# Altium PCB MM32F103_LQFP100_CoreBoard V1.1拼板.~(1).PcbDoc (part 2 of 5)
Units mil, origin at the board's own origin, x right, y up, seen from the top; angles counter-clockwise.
Board outline 7436.93 x 4329.96 mil, 2 copper layers (Top Layer, Bottom Layer); 260 components, 116 nets, 1796 pads, 448 vias.

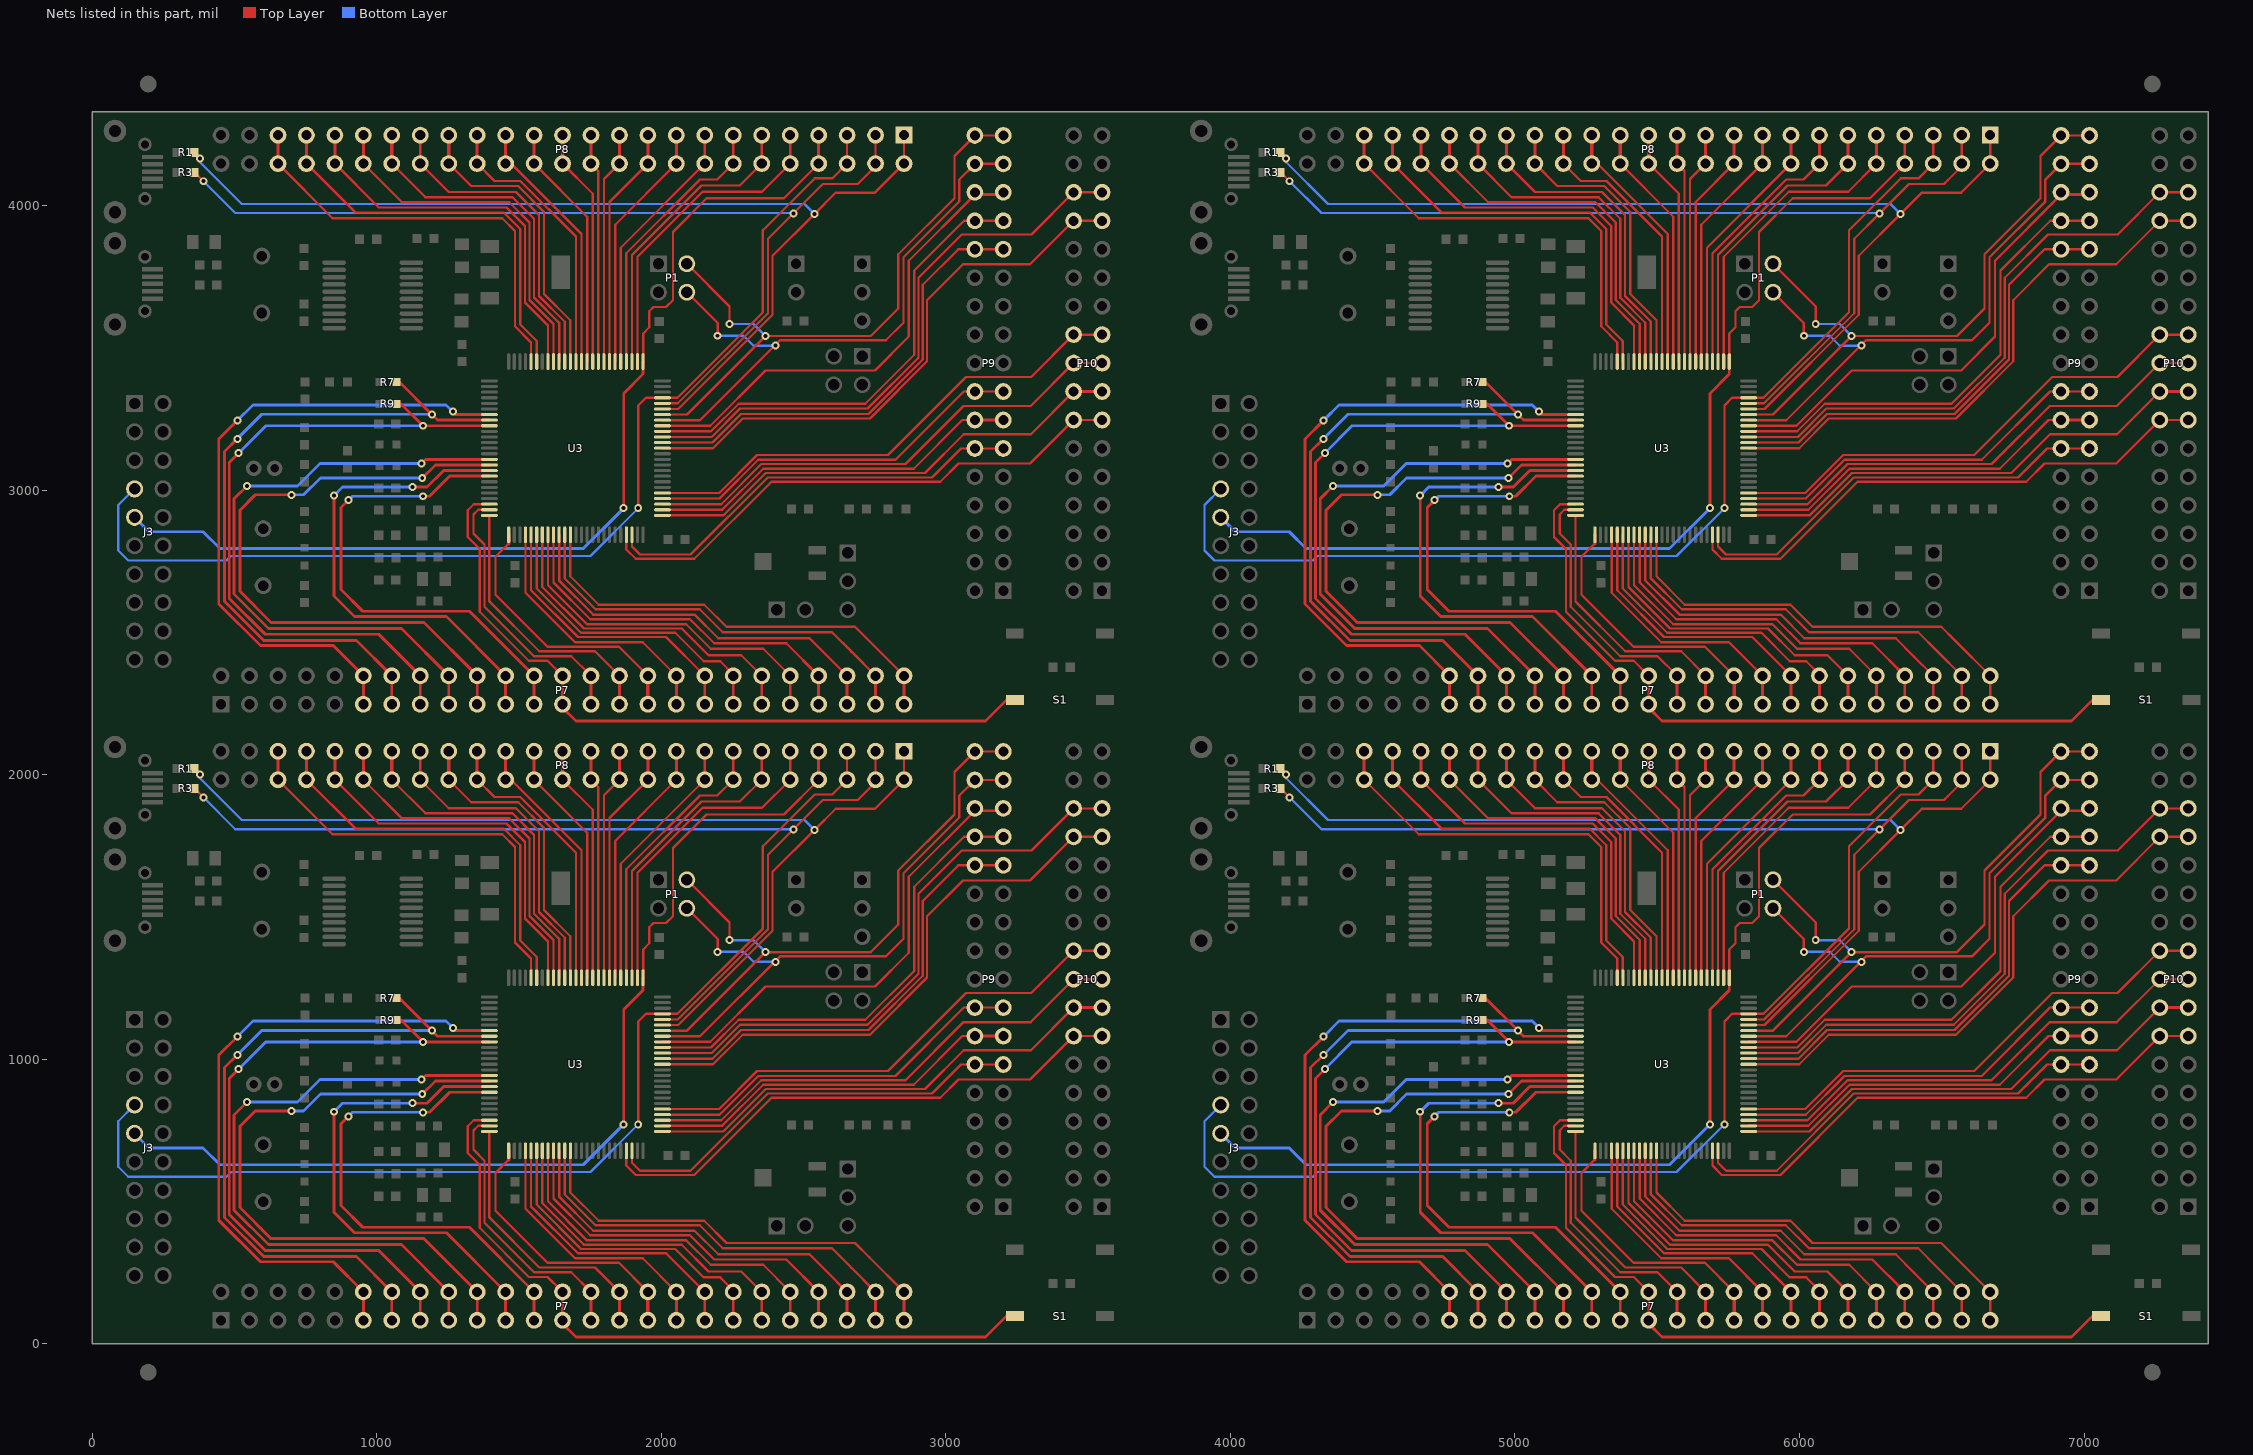
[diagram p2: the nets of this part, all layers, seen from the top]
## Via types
v1: diameter 28, hole 14, Top Layer to Bottom Layer, 228 vias
v2: diameter 24, hole 12, Top Layer to Bottom Layer, 220 vias

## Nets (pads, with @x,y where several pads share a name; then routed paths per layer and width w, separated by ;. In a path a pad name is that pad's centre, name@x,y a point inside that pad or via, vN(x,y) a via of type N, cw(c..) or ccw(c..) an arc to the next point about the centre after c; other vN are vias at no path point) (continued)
PA0: P7.25 P7.26 S1.1 U3.23 | length 10381.6
  Top Layer w8: U3.23@1395.87,786.15 1341.15,786.15 1320,765 1320,671 1362,629 1362,408 1534.5,235.5 1600.5,235.5 P7.26@1647.38,188.62 ; U3.23@1395.87,2951.15 1341.15,2951.15 1320,2930 1320,2836 1362,2794 1362,2573 1534.5,2400.5 1600.5,2400.5 P7.26@1647.38,2353.62 ; U3.23@5212.79,786.15 5158.08,786.15 5136.93,765 5136.93,671 5178.93,629 5178.93,408 5351.43,235.5 5417.43,235.5 P7.26@5464.31,188.62 ; U3.23@5212.79,2951.15 5158.08,2951.15 5136.93,2930 5136.93,2836 5178.93,2794 5178.93,2573 5351.43,2400.5 5417.43,2400.5 P7.26@5464.31,2353.62
  Top Layer w10: P7.26@1647.38,188.62 P7.26@1653,183 P7.25@1653,83 1653,71 1700,24 3139,24 3213.17,98.17 S1.1@3243,98.17 ; P7.26@1647.38,2353.62 P7.26@1653,2348 P7.25@1653,2248 1653,2236 1700,2189 3139,2189 3213.17,2263.17 S1.1@3243,2263.17 ; P7.26@5464.31,188.62 P7.26@5469.93,183 P7.25@5469.93,83 5469.93,71 5516.93,24 6955.93,24 7030.09,98.17 S1.1@7059.93,98.17 ; P7.26@5464.31,2353.62 P7.26@5469.93,2348 P7.25@5469.93,2248 5469.93,2236 5516.93,2189 6955.93,2189 7030.09,2263.17 S1.1@7059.93,2263.17
PA1: P7.27 P7.28 U3.24 | length 3910
  Top Layer w8: U3.24@1395.87,766.47 1356.47,766.47 1340,750 1340,683 1379,644 1379,426 1553,252 1684,252 P7.28@1753,183 ; U3.24@1395.87,2931.47 1356.47,2931.47 1340,2915 1340,2848 1379,2809 1379,2591 1553,2417 1684,2417 P7.28@1753,2348 ; U3.24@5212.79,766.47 5173.39,766.47 5156.93,750 5156.93,683 5195.93,644 5195.93,426 5369.93,252 5500.93,252 P7.28@5569.93,183 ; U3.24@5212.79,2931.47 5173.39,2931.47 5156.93,2915 5156.93,2848 5195.93,2809 5195.93,2591 5369.93,2417 5500.93,2417 P7.28@5569.93,2348
  Top Layer w10: P7.27@1753,83 P7.28@1753,183 ; P7.27@1753,2248 P7.28@1753,2348 ; P7.27@5569.93,83 P7.28@5569.93,183 ; P7.27@5569.93,2248 P7.28@5569.93,2348
PA2: P7.29 P7.30 U3.25 | length 3871.8
  Top Layer w8: U3.25@1395.87,746.78 1395.87,444.13 1571,269 1767,269 P7.30@1853,183 ; U3.25@1395.87,2911.78 1395.87,2609.13 1571,2434 1767,2434 P7.30@1853,2348 ; U3.25@5212.79,746.78 5212.79,444.13 5387.93,269 5583.93,269 P7.30@5669.93,183 ; U3.25@5212.79,2911.78 5212.79,2609.13 5387.93,2434 5583.93,2434 P7.30@5669.93,2348
  Top Layer w10: P7.29@1853,83 P7.30@1853,183 ; P7.29@1853,2248 P7.30@1853,2348 ; P7.29@5669.93,83 P7.30@5669.93,183 ; P7.29@5669.93,2248 P7.30@5669.93,2348
PA3: P7.31 P7.32 U3.26 | length 3996.2
  Top Layer w8: 1463.78,421.22 1474.21,410.79 ; 1463.78,647.78 1417,601 1417,468 1474.21,410.79 ; 1463.78,2586.22 1474.21,2575.79 ; 1463.78,2812.78 1417,2766 1417,2633 1474.21,2575.79 ; P7.32@1953,183 1851,285 1600,285 1474.21,410.79 ; P7.32@1953,2348 1851,2450 1600,2450 1474.21,2575.79 ; 5280.71,421.22 5291.14,410.79 ; 5280.71,647.78 5233.93,601 5233.93,468 5291.14,410.79 ; 5280.71,2586.22 5291.14,2575.79 ; 5280.71,2812.78 5233.93,2766 5233.93,2633 5291.14,2575.79 ; P7.32@5769.93,183 5667.93,285 5416.93,285 5291.14,410.79 ; P7.32@5769.93,2348 5667.93,2450 5416.93,2450 5291.14,2575.79
  Top Layer w12: 1463.78,647.78 U3.26@1463.78,678.87 ; 1463.78,2812.78 U3.26@1463.78,2843.87 ; P7.31@1953,83 P7.32@1953,183 ; P7.31@1953,2248 P7.32@1953,2348 ; 5280.71,647.78 U3.26@5280.71,678.87 ; 5280.71,2812.78 U3.26@5280.71,2843.87 ; P7.31@5769.93,83 P7.32@5769.93,183 ; P7.31@5769.93,2248 P7.32@5769.93,2348
PA4: P7.33 P7.34 U3.29 | length 3819.5
  Top Layer w8: U3.29@1522.83,678.87 1522.83,475.17 1697,301 1935,301 P7.34@2053,183 ; U3.29@1522.83,2843.87 1522.83,2640.17 1697,2466 1935,2466 P7.34@2053,2348 ; U3.29@5339.76,678.87 5339.76,475.17 5513.93,301 5751.93,301 P7.34@5869.93,183 ; U3.29@5339.76,2843.87 5339.76,2640.17 5513.93,2466 5751.93,2466 P7.34@5869.93,2348
  Top Layer w10: P7.33@2053,83 P7.34@2053,183 ; P7.33@2053,2248 P7.34@2053,2348 ; P7.33@5869.93,83 P7.34@5869.93,183 ; P7.33@5869.93,2248 P7.34@5869.93,2348
PA5: P7.35 P7.36 U3.30 | length 4121.3
  Top Layer w8: U3.30@1542.52,678.87 1542.52,483.48 1707,319 1894,319 2017,319 P7.36@2153,183 ; U3.30@1542.52,2843.87 1542.52,2648.48 1707,2484 1894,2484 2017,2484 P7.36@2153,2348 ; U3.30@5359.45,678.87 5359.45,483.48 5523.93,319 5710.93,319 5833.93,319 P7.36@5969.93,183 ; U3.30@5359.45,2843.87 5359.45,2648.48 5523.93,2484 5710.93,2484 5833.93,2484 P7.36@5969.93,2348
  Top Layer w10: P7.35@2153,83 P7.36@2153,183 ; P7.35@2153,2248 P7.36@2153,2348 ; P7.35@5969.93,83 P7.36@5969.93,183 ; P7.35@5969.93,2248 P7.36@5969.93,2348
PA6: P7.37 P7.38 U3.31 | length 4439.5
  Top Layer w8: U3.31@1562.2,678.86 1562.2,489.79 1717.99,334 2049,334 2149,234 2207,234 P7.38@2253,188 ; U3.31@1562.2,2843.86 1562.2,2654.79 1717.99,2499 2049,2499 2149,2399 2207,2399 P7.38@2253,2353 ; U3.31@5379.13,678.86 5379.13,489.79 5534.92,334 5865.93,334 5965.93,234 6023.93,234 P7.38@6069.93,188 ; U3.31@5379.13,2843.86 5379.13,2654.79 5534.92,2499 5865.93,2499 5965.93,2399 6023.93,2399 P7.38@6069.93,2353
  Top Layer w10: P7.37@2253,83 2253,176 P7.38@2253,183 P7.38@2253,188 ; P7.37@2253,2248 2253,2341 P7.38@2253,2348 P7.38@2253,2353 ; P7.37@6069.93,83 6069.93,176 P7.38@6069.93,183 P7.38@6069.93,188 ; P7.37@6069.93,2248 6069.93,2341 P7.38@6069.93,2348 P7.38@6069.93,2353
PA7: P7.39 P7.40 U3.32 | length 4736.6
  Top Layer w8: U3.32@1581.89,678.87 1581.89,495.11 1728,349 2072,349 2166,255 2281,255 P7.40@2353,183 ; U3.32@1581.89,2843.87 1581.89,2660.11 1728,2514 2072,2514 2166,2420 2281,2420 P7.40@2353,2348 ; U3.32@5398.82,678.87 5398.82,495.11 5544.93,349 5888.93,349 5982.93,255 6097.93,255 P7.40@6169.93,183 ; U3.32@5398.82,2843.87 5398.82,2660.11 5544.93,2514 5888.93,2514 5982.93,2420 6097.93,2420 P7.40@6169.93,2348
  Top Layer w10: P7.39@2353,83 P7.40@2353,183 ; P7.39@2353,2248 P7.40@2353,2348 ; P7.39@6169.93,83 P7.40@6169.93,183 ; P7.39@6169.93,2248 P7.40@6169.93,2348
PA8: P9.29 P9.30 U3.67 | length 6776.1
  Top Layer w8: U3.67@2004.13,1061.74 2172.11,1061.74 2366.37,1256 2751,1256 2870,1375 2870,1642 P9.30@3102,1874 ; U3.67@2004.13,3226.74 2172.11,3226.74 2366.37,3421 2751,3421 2870,3540 2870,3807 P9.30@3102,4039 ; U3.67@5821.06,1061.74 5989.04,1061.74 6183.3,1256 6567.93,1256 6686.93,1375 6686.93,1642 P9.30@6918.93,1874 ; U3.67@5821.06,3226.74 5989.04,3226.74 6183.3,3421 6567.93,3421 6686.93,3540 6686.93,3807 P9.30@6918.93,4039
  Top Layer w10: P9.30@3102,1874 3194,1874 P9.29@3202,1882 ; P9.30@3102,4039 3194,4039 P9.29@3202,4047 ; P9.30@6918.93,1874 7010.93,1874 P9.29@7018.93,1882 ; P9.30@6918.93,4039 7010.93,4039 P9.29@7018.93,4047
PA9: P1.4 P9.31 P9.32 U3.68 | length 8663.9
  Top Layer w8: U3.68@2004.13,1081.43 2136.43,1081.43 2417,1362 2789,1362 2851,1424 2851,1654 3047,1850 3047,1927 P9.32@3102,1982 P9.31@3202,1982 ; U3.68@2004.13,3246.43 2136.43,3246.43 2417,3527 2789,3527 2851,3589 2851,3819 3047,4015 3047,4092 P9.32@3102,4147 P9.31@3202,4147 ; P1.4@2090,1531 2198,1423 v1(2198,1378) ; P1.4@2090,3696 2198,3588 v1(2198,3543) ; U3.68@5821.06,1081.43 5953.35,1081.43 6233.93,1362 6605.93,1362 6667.93,1424 6667.93,1654 6863.93,1850 6863.93,1927 P9.32@6918.93,1982 P9.31@7018.93,1982 ; U3.68@5821.06,3246.43 5953.35,3246.43 6233.93,3527 6605.93,3527 6667.93,3589 6667.93,3819 6863.93,4015 6863.93,4092 P9.32@6918.93,4147 P9.31@7018.93,4147 ; P1.4@5906.93,1531 6014.93,1423 v1(6014.93,1378) ; P1.4@5906.93,3696 6014.93,3588 v1(6014.93,3543)
  Bottom Layer w8: v1(2198,1378) 2289,1378 2324,1343 v1(2401,1343) ; v1(2198,3543) 2289,3543 2324,3508 v1(2401,3508) ; v1(6014.93,1378) 6105.93,1378 6140.93,1343 v1(6217.93,1343) ; v1(6014.93,3543) 6105.93,3543 6140.93,3508 v1(6217.93,3508)
PA10: P1.2 P9.33 P9.34 U3.69 | length 8881.1
  Top Layer w8: U3.69@2004.13,1101.11 2090.11,1101.11 v1(2366,1377) 2736,1377 2833,1474 2833,1664 3030,1861 3030,2010 P9.34@3102,2082 P9.33@3202,2082 ; U3.69@2004.13,3266.11 2090.11,3266.11 v1(2366,3542) 2736,3542 2833,3639 2833,3829 3030,4026 3030,4175 P9.34@3102,4247 P9.33@3202,4247 ; P1.2@2090,1631 2240,1481 v1(2240,1419) ; P1.2@2090,3796 2240,3646 v1(2240,3584) ; U3.69@5821.06,1101.11 5907.04,1101.11 v1(6182.93,1377) 6552.93,1377 6649.93,1474 6649.93,1664 6846.93,1861 6846.93,2010 P9.34@6918.93,2082 P9.33@7018.93,2082 ; U3.69@5821.06,3266.11 5907.04,3266.11 v1(6182.93,3542) 6552.93,3542 6649.93,3639 6649.93,3829 6846.93,4026 6846.93,4175 P9.34@6918.93,4247 P9.33@7018.93,4247 ; P1.2@5906.93,1631 6056.93,1481 v1(6056.93,1419) ; P1.2@5906.93,3796 6056.93,3646 v1(6056.93,3584)
  Bottom Layer w8: v1(2240,1419) 2324,1419 v1(2366,1377) ; v1(2240,3584) 2324,3584 v1(2366,3542) ; v1(6056.93,1419) 6140.93,1419 v1(6182.93,1377) ; v1(6056.93,3584) 6140.93,3584 v1(6182.93,3542)
PA11: P8.1 P8.2 R1.2 U3.70 | length 14765.4
  Top Layer w8: R1.2@358,2022 v1(379,2001) ; R1.2@358,4187 v1(379,4166) ; U3.70@2004.13,1120.79 2059.79,1120.79 2391,1452 2391,1659 v1(2538,1806) 2613,1881 2648,1881 2751,1881 P8.2@2853,1983 P8.1@2853,2083 ; U3.70@2004.13,3285.79 2059.79,3285.79 2391,3617 2391,3824 v1(2538,3971) 2613,4046 2648,4046 2751,4046 P8.2@2853,4148 P8.1@2853,4248 ; R1.2@4174.93,2022 v1(4195.93,2001) ; R1.2@4174.93,4187 v1(4195.93,4166) ; U3.70@5821.06,1120.79 5876.72,1120.79 6207.93,1452 6207.93,1659 v1(6354.93,1806) 6429.93,1881 6464.93,1881 6567.93,1881 P8.2@6669.93,1983 P8.1@6669.93,2083 ; U3.70@5821.06,3285.79 5876.72,3285.79 6207.93,3617 6207.93,3824 v1(6354.93,3971) 6429.93,4046 6464.93,4046 6567.93,4046 P8.2@6669.93,4148 P8.1@6669.93,4248
  Bottom Layer w8: v1@379,1988 526,1841 2503,1841 v1(2538,1806) ; v1@379,4153 526,4006 2503,4006 v1(2538,3971) ; v1@4195.93,1988 4342.93,1841 6319.93,1841 v1(6354.93,1806) ; v1@4195.93,4153 4342.93,4006 6319.93,4006 v1(6354.93,3971)
PA12: P8.3 P8.4 R3.2 U3.71 | length 14090.1
  Top Layer w8: R3.2@358,1954 v1(391,1921) ; R3.2@358,4119 v1(391,4086) ; U3.71@2004.13,1140.48 2058.27,1140.48 2375,1457.21 2375,1719 v1(2464,1808) 2567.5,1911.5 2690.5,1911.5 2703.56,1924.56 2753,1974 P8.4@2753,1983 P8.3@2753,2083 ; U3.71@2004.13,3305.48 2058.27,3305.48 2375,3622.21 2375,3884 v1(2464,3973) 2567.5,4076.5 2690.5,4076.5 2703.56,4089.56 2753,4139 P8.4@2753,4148 P8.3@2753,4248 ; R3.2@4174.93,1954 v1(4207.93,1921) ; R3.2@4174.93,4119 v1(4207.93,4086) ; U3.71@5821.06,1140.48 5875.2,1140.48 6191.93,1457.21 6191.93,1719 v1(6280.93,1808) 6384.43,1911.5 6507.43,1911.5 6520.49,1924.56 6569.93,1974 P8.4@6569.93,1983 P8.3@6569.93,2083 ; U3.71@5821.06,3305.48 5875.2,3305.48 6191.93,3622.21 6191.93,3884 v1(6280.93,3973) 6384.43,4076.5 6507.43,4076.5 6520.49,4089.56 6569.93,4139 P8.4@6569.93,4148 P8.3@6569.93,4248
  Bottom Layer w8: v1(391,1921) 503,1809 v1@2464,1809 ; v1(391,4086) 503,3974 v1@2464,3974 ; v1(4207.93,1921) 4319.93,1809 v1@6280.93,1809 ; v1(4207.93,4086) 4319.93,3974 v1@6280.93,3974
PA13: J3.7 P8.5 P8.6 U3.72 | length 15497.8
  Top Layer w8: v1(1919,772) 1919,1133 1946.17,1160.17 U3.72@2004.13,1160.17 2056.74,1160.17 2357,1460.43 2357,1668 2357,1749 2539.07,1931.07 2601.07,1931.07 P8.6@2653,1983 P8.5@2653,2083 ; v1(1919,2937) 1919,3298 1946.17,3325.17 U3.72@2004.13,3325.17 2056.74,3325.17 2357,3625.43 2357,3833 2357,3914 2539.07,4096.07 2601.07,4096.07 P8.6@2653,4148 P8.5@2653,4248 ; v1(5735.93,772) 5735.93,1133 5763.09,1160.17 U3.72@5821.06,1160.17 5873.67,1160.17 6173.93,1460.43 6173.93,1668 6173.93,1749 6356,1931.07 6418,1931.07 P8.6@6469.93,1983 P8.5@6469.93,2083 ; v1(5735.93,2937) 5735.93,3298 5763.09,3325.17 U3.72@5821.06,3325.17 5873.67,3325.17 6173.93,3625.43 6173.93,3833 6173.93,3914 6356,4096.07 6418,4096.07 P8.6@6469.93,4148 P8.5@6469.93,4248
  Bottom Layer w8: J3.7@149,840 92,783 92,623 127,588 472,588 488,604 1751,604 v1(1919,772) ; J3.7@149,3005 92,2948 92,2788 127,2753 472,2753 488,2769 1751,2769 v1(1919,2937) ; J3.7@3965.93,840 3908.93,783 3908.93,623 3943.93,588 4288.93,588 4304.93,604 5567.93,604 v1(5735.93,772) ; J3.7@3965.93,3005 3908.93,2948 3908.93,2788 3943.93,2753 4288.93,2753 4304.93,2769 5567.93,2769 v1(5735.93,2937)
PA14: J3.9 P8.7 P8.8 U3.76 | length 14417.3
  Top Layer w8: U3.76@1936.22,1287.13 1936.22,1386.22 1958,1408 1958,1464 1973,1479 2017,1479 2041,1503 2041,1743 2159,1861 2431,1861 P8.8@2553,1983 ; U3.76@1936.22,3452.13 1936.22,3551.22 1958,3573 1958,3629 1973,3644 2017,3644 2041,3668 2041,3908 2159,4026 2431,4026 P8.8@2553,4148 ; U3.76@5753.15,1287.13 5753.15,1386.22 5774.93,1408 5774.93,1464 5789.93,1479 5833.93,1479 5857.93,1503 5857.93,1743 5975.93,1861 6247.93,1861 P8.8@6369.93,1983 ; U3.76@5753.15,3452.13 5753.15,3551.22 5774.93,3573 5774.93,3629 5789.93,3644 5833.93,3644 5857.93,3668 5857.93,3908 5975.93,4026 6247.93,4026 P8.8@6369.93,4148
  Top Layer w10: v1(1868,772) 1868,1175 1936.22,1243.22 U3.76@1936.22,1287.13 U3.76@1937,1286.35 ; v1(1868,2937) 1868,3340 1936.22,3408.22 U3.76@1936.22,3452.13 U3.76@1937,3451.35 ; P8.8@2553,1983 P8.7@2553,2083 ; P8.8@2553,4148 P8.7@2553,4248 ; v1(5684.93,772) 5684.93,1175 5753.15,1243.22 U3.76@5753.15,1287.13 U3.76@5753.93,1286.35 ; v1(5684.93,2937) 5684.93,3340 5753.15,3408.22 U3.76@5753.15,3452.13 U3.76@5753.93,3451.35 ; P8.8@6369.93,1983 P8.7@6369.93,2083 ; P8.8@6369.93,4148 P8.7@6369.93,4248
  Bottom Layer w10: J3.9@149,740 200,689 390,689 449,630 1726,630 v1(1868,772) ; J3.9@149,2905 200,2854 390,2854 449,2795 1726,2795 v1(1868,2937) ; J3.9@3965.93,740 4016.93,689 4206.93,689 4265.93,630 5542.93,630 v1(5684.93,772) ; J3.9@3965.93,2905 4016.93,2854 4206.93,2854 4265.93,2795 5542.93,2795 v1(5684.93,2937)
PA15: P8.9 P8.10 U3.77 | length 4562
  Top Layer w8: U3.77@1916.53,1287.13 1916.53,1395.53 1916.53,1655.53 2145,1884 2354,1884 P8.10@2453,1983 ; U3.77@1916.53,3452.13 1916.53,3560.53 1916.53,3820.53 2145,4049 2354,4049 P8.10@2453,4148 ; U3.77@5733.46,1287.13 5733.46,1395.53 5733.46,1655.53 5961.93,1884 6170.93,1884 P8.10@6269.93,1983 ; U3.77@5733.46,3452.13 5733.46,3560.53 5733.46,3820.53 5961.93,4049 6170.93,4049 P8.10@6269.93,4148
  Top Layer w10: P8.10@2453,1983 P8.9@2453,2083 ; P8.10@2453,4148 P8.9@2453,4248 ; P8.10@6269.93,1983 P8.9@6269.93,2083 ; P8.10@6269.93,4148 P8.9@6269.93,4248
PB0: P7.45 P7.46 U3.35 | length 5701.7
  Top Layer w8: U3.35@1640.94,678.87 1640.94,518.06 1761,398 2117,398 2200,315 2521,315 2585.74,250.26 ; U3.35@1640.94,2843.87 1640.94,2683.06 1761,2563 2117,2563 2200,2480 2521,2480 2585.74,2415.26 ; 2576,260 2585.74,250.26 ; 2576,2425 2585.74,2415.26 ; P7.46@2653,183 2585.74,250.26 ; P7.46@2653,2348 2585.74,2415.26 ; U3.35@5457.87,678.87 5457.87,518.06 5577.93,398 5933.93,398 6016.93,315 6337.93,315 6402.67,250.26 ; U3.35@5457.87,2843.87 5457.87,2683.06 5577.93,2563 5933.93,2563 6016.93,2480 6337.93,2480 6402.67,2415.26 ; 6392.93,260 6402.67,250.26 ; 6392.93,2425 6402.67,2415.26 ; P7.46@6469.93,183 6402.67,250.26 ; P7.46@6469.93,2348 6402.67,2415.26
  Top Layer w10: P7.45@2653,83 P7.46@2653,183 ; P7.45@2653,2248 P7.46@2653,2348 ; P7.45@6469.93,83 P7.46@6469.93,183 ; P7.45@6469.93,2248 P7.46@6469.93,2348
PB1: P7.47 P7.48 U3.36 | length 6029.9
  Top Layer w8: U3.36@1660.63,678.87 1660.63,525.37 1769,417 1995,417 2135,417 2216,336 2600,336 2668,268 ; U3.36@1660.63,2843.87 1660.63,2690.37 1769,2582 1995,2582 2135,2582 2216,2501 2600,2501 2668,2433 ; 2654,282 2668,268 ; 2654,2447 2668,2433 ; P7.48@2753,183 2668,268 ; P7.48@2753,2348 2668,2433 ; U3.36@5477.56,678.87 5477.56,525.37 5585.93,417 5811.93,417 5951.93,417 6032.93,336 6416.93,336 6484.93,268 ; U3.36@5477.56,2843.87 5477.56,2690.37 5585.93,2582 5811.93,2582 5951.93,2582 6032.93,2501 6416.93,2501 6484.93,2433 ; 6470.93,282 6484.93,268 ; 6470.93,2447 6484.93,2433 ; P7.48@6569.93,183 6484.93,268 ; P7.48@6569.93,2348 6484.93,2433
  Top Layer w10: P7.47@2753,83 P7.48@2753,183 ; P7.47@2753,2248 P7.48@2753,2348 ; P7.47@6569.93,83 P7.48@6569.93,183 ; P7.47@6569.93,2248 P7.48@6569.93,2348
PB2: P7.49 P7.50 U3.37 | length 6254.8
  Top Layer w8: U3.37@1680.32,678.87 1680.32,532.68 1780,433 2151,433 2229,355 2681,355 2731,305 P7.50@2853,183 ; U3.37@1680.32,2843.87 1680.32,2697.68 1780,2598 2151,2598 2229,2520 2681,2520 2731,2470 P7.50@2853,2348 ; U3.37@5497.24,678.87 5497.24,532.68 5596.93,433 5967.93,433 6045.93,355 6497.93,355 6547.93,305 P7.50@6669.93,183 ; U3.37@5497.24,2843.87 5497.24,2697.68 5596.93,2598 5967.93,2598 6045.93,2520 6497.93,2520 6547.93,2470 P7.50@6669.93,2348
  Top Layer w10: P7.49@2853,83 P7.50@2853,183 ; P7.49@2853,2248 P7.50@2853,2348 ; P7.49@6669.93,83 P7.50@6669.93,183 ; P7.49@6669.93,2248 P7.50@6669.93,2348
PB3: P8.33 P8.34 U3.89 | length 4278.1
  Top Layer w8: P8.34@1253,1983 1332,1904 1497,1904 1588,1813 1588,1525 1680.32,1432.68 U3.89@1680.32,1287.13 ; P8.34@1253,4148 1332,4069 1497,4069 1588,3978 1588,3690 1680.32,3597.68 U3.89@1680.32,3452.13 ; P8.34@5069.93,1983 5148.93,1904 5313.93,1904 5404.93,1813 5404.93,1525 5497.24,1432.68 U3.89@5497.24,1287.13 ; P8.34@5069.93,4148 5148.93,4069 5313.93,4069 5404.93,3978 5404.93,3690 5497.24,3597.68 U3.89@5497.24,3452.13
  Top Layer w11: P8.34@1253,1983 P8.33@1253,2083 ; P8.34@1253,4148 P8.33@1253,4248 ; P8.34@5069.93,1983 P8.33@5069.93,2083 ; P8.34@5069.93,4148 P8.33@5069.93,4248
PB4: P8.35 P8.36 U3.90 | length 4577.5
  Top Layer w8: P8.36@1153,1983 1253,1883 1489,1883 1570,1802 1570,1518 1660.63,1427.37 U3.90@1660.63,1287.13 ; P8.36@1153,4148 1253,4048 1489,4048 1570,3967 1570,3683 1660.63,3592.37 U3.90@1660.63,3452.13 ; P8.36@4969.93,1983 5069.93,1883 5305.93,1883 5386.93,1802 5386.93,1518 5477.56,1427.37 U3.90@5477.56,1287.13 ; P8.36@4969.93,4148 5069.93,4048 5305.93,4048 5386.93,3967 5386.93,3683 5477.56,3592.37 U3.90@5477.56,3452.13
  Top Layer w10: P8.36@1153,1983 P8.35@1153,2083 ; P8.36@1153,4148 P8.35@1153,4248 ; P8.36@4969.93,1983 P8.35@4969.93,2083 ; P8.36@4969.93,4148 P8.35@4969.93,4248
PB5: P8.37 P8.38 U3.91 | length 4874.6
  Top Layer w8: P8.38@1053,1983 1171,1865 1477,1865 1553,1789 1553,1512 1640.94,1424.06 U3.91@1640.94,1287.13 ; P8.38@1053,4148 1171,4030 1477,4030 1553,3954 1553,3677 1640.94,3589.06 U3.91@1640.94,3452.13 ; P8.38@4869.93,1983 4987.93,1865 5293.93,1865 5369.93,1789 5369.93,1512 5457.87,1424.06 U3.91@5457.87,1287.13 ; P8.38@4869.93,4148 4987.93,4030 5293.93,4030 5369.93,3954 5369.93,3677 5457.87,3589.06 U3.91@5457.87,3452.13
  Top Layer w11: P8.38@1053,1983 P8.37@1053,2083 ; P8.38@1053,4148 P8.37@1053,4248 ; P8.38@4869.93,1983 P8.37@4869.93,2083 ; P8.38@4869.93,4148 P8.37@4869.93,4248
PB6: P8.39 P8.40 U3.92 | length 5174
  Top Layer w8: P8.40@953,1983 1089,1847 1466,1847 1537,1776 1537,1504 1621.26,1419.74 U3.92@1621.26,1287.13 ; P8.40@953,4148 1089,4012 1466,4012 1537,3941 1537,3669 1621.26,3584.74 U3.92@1621.26,3452.13 ; P8.40@4769.93,1983 4905.93,1847 5282.93,1847 5353.93,1776 5353.93,1504 5438.19,1419.74 U3.92@5438.19,1287.13 ; P8.40@4769.93,4148 4905.93,4012 5282.93,4012 5353.93,3941 5353.93,3669 5438.19,3584.74 U3.92@5438.19,3452.13
  Top Layer w11: P8.40@953,1983 P8.39@953,2083 ; P8.40@953,4148 P8.39@953,4248 ; P8.40@4769.93,1983 P8.39@4769.93,2083 ; P8.40@4769.93,4148 P8.39@4769.93,4248
PB7: P8.41 P8.42 U3.93 | length 5475.8
  Top Layer w8: P8.42@853,1983 1007,1829 1456,1829 1521,1764 1521,1495 1601.58,1414.42 U3.93@1601.58,1287.13 ; P8.42@853,4148 1007,3994 1456,3994 1521,3929 1521,3660 1601.58,3579.42 U3.93@1601.58,3452.13 ; P8.42@4669.93,1983 4823.93,1829 5272.93,1829 5337.93,1764 5337.93,1495 5418.5,1414.42 U3.93@5418.5,1287.13 ; P8.42@4669.93,4148 4823.93,3994 5272.93,3994 5337.93,3929 5337.93,3660 5418.5,3579.42 U3.93@5418.5,3452.13
  Top Layer w11: P8.42@853,1983 P8.41@853,2083 ; P8.42@853,4148 P8.41@853,4248 ; P8.42@4669.93,1983 P8.41@4669.93,2083 ; P8.42@4669.93,4148 P8.41@4669.93,4248
PB8: P8.43 P8.44 U3.95 | length 5744.9
  Top Layer w8: P8.44@753,1983 925,1811 1445.95,1811 1504,1752.95 1504,1417.95 1562.2,1359.75 U3.95@1562.2,1287.14 ; P8.44@753,4148 925,3976 1445.95,3976 1504,3917.95 1504,3582.95 1562.2,3524.75 U3.95@1562.2,3452.14 ; P8.44@4569.93,1983 4741.93,1811 5262.88,1811 5320.93,1752.95 5320.93,1417.95 5379.13,1359.75 U3.95@5379.13,1287.14 ; P8.44@4569.93,4148 4741.93,3976 5262.88,3976 5320.93,3917.95 5320.93,3582.95 5379.13,3524.75 U3.95@5379.13,3452.14
  Top Layer w11: P8.44@753,1983 P8.43@753,2083 ; P8.44@753,4148 P8.43@753,4248 ; P8.44@4569.93,1983 P8.43@4569.93,2083 ; P8.44@4569.93,4148 P8.43@4569.93,4248
PB9: P8.45 P8.46 U3.96 | length 6054.3
  Top Layer w8: P8.46@653,1983 845,1791 1441.2,1791 1486,1746.2 1486,1411.2 1542.52,1354.68 U3.96@1542.52,1287.13 ; P8.46@653,4148 845,3956 1441.2,3956 1486,3911.2 1486,3576.2 1542.52,3519.68 U3.96@1542.52,3452.13 ; P8.46@4469.93,1983 4661.93,1791 5258.13,1791 5302.93,1746.2 5302.93,1411.2 5359.45,1354.68 U3.96@5359.45,1287.13 ; P8.46@4469.93,4148 4661.93,3956 5258.13,3956 5302.93,3911.2 5302.93,3576.2 5359.45,3519.68 U3.96@5359.45,3452.13
  Top Layer w10: P8.46@653,1983 P8.45@653,2083 ; P8.46@653,4148 P8.45@653,4248 ; P8.46@4469.93,1983 P8.45@4469.93,2083 ; P8.46@4469.93,4148 P8.45@4469.93,4248
PB10: P10.13 P10.14 U3.47 | length 7758.4
  Top Layer w8: U3.47@1877.17,678.87 1877.17,626.83 1910,594 2097.79,594 2116,594 2387,865 2980,865 3044,929 3296,929 P10.14@3449,1082 P10.13@3549,1082 ; U3.47@1877.17,2843.87 1877.17,2791.83 1910,2759 2097.79,2759 2116,2759 2387,3030 2980,3030 3044,3094 3296,3094 P10.14@3449,3247 P10.13@3549,3247 ; U3.47@5694.09,678.87 5694.09,626.83 5726.93,594 5914.72,594 5932.93,594 6203.93,865 6796.93,865 6860.93,929 7112.93,929 P10.14@7265.93,1082 P10.13@7365.93,1082 ; U3.47@5694.09,2843.87 5694.09,2791.83 5726.93,2759 5914.72,2759 5932.93,2759 6203.93,3030 6796.93,3030 6860.93,3094 7112.93,3094 P10.14@7265.93,3247 P10.13@7365.93,3247
PB11: P9.11 P9.12 U3.48 | length 6052.1
  Top Layer w8: U3.48@1896.85,678.87 1896.85,637.15 1925,609 2091,609 2103,609 2374,880 2951,880 3053,982 P9.12@3102,982 P9.11@3202,982 ; U3.48@1896.85,2843.87 1896.85,2802.15 1925,2774 2091,2774 2103,2774 2374,3045 2951,3045 3053,3147 P9.12@3102,3147 P9.11@3202,3147 ; U3.48@5713.78,678.87 5713.78,637.15 5741.93,609 5907.93,609 5919.93,609 6190.93,880 6767.93,880 6869.93,982 P9.12@6918.93,982 P9.11@7018.93,982 ; U3.48@5713.78,2843.87 5713.78,2802.15 5741.93,2774 5907.93,2774 5919.93,2774 6190.93,3045 6767.93,3045 6869.93,3147 P9.12@6918.93,3147 P9.11@7018.93,3147
PB12: P10.15 P10.16 U3.51 | length 6900.6
  Top Layer w8: U3.51@2004.13,746.78 2218.15,746.78 2367.37,896 2927,896 3063,1032 3299,1032 P10.16@3449,1182 ; U3.51@2004.13,2911.78 2218.15,2911.78 2367.37,3061 2927,3061 3063,3197 3299,3197 P10.16@3449,3347 ; U3.51@5821.06,746.78 6035.08,746.78 6184.3,896 6743.93,896 6879.93,1032 7115.93,1032 P10.16@7265.93,1182 ; U3.51@5821.06,2911.78 6035.08,2911.78 6184.3,3061 6743.93,3061 6879.93,3197 7115.93,3197 P10.16@7265.93,3347
  Top Layer w10: P10.16@3449,1182 P10.15@3549,1182 ; P10.16@3449,3347 P10.15@3549,3347 ; P10.16@7265.93,1182 P10.15@7365.93,1182 ; P10.16@7265.93,3347 P10.15@7365.93,3347
PB13: P9.13 P9.14 U3.52 | length 5314.3
  Top Layer w8: U3.52@2004.13,766.47 2213.8,766.47 2358.33,911 2887,911 3058,1082 P9.14@3102,1082 ; U3.52@2004.13,2931.47 2213.8,2931.47 2358.33,3076 2887,3076 3058,3247 P9.14@3102,3247 ; U3.52@5821.06,766.47 6030.73,766.47 6175.26,911 6703.93,911 6874.93,1082 P9.14@6918.93,1082 ; U3.52@5821.06,2931.47 6030.73,2931.47 6175.26,3076 6703.93,3076 6874.93,3247 P9.14@6918.93,3247
  Top Layer w10: P9.14@3102,1082 P9.13@3202,1082 ; P9.14@3102,3247 P9.13@3202,3247 ; P9.14@6918.93,1082 P9.13@7018.93,1082 ; P9.14@6918.93,3247 P9.13@7018.93,3247
PB14: P10.17 P10.18 U3.53 | length 7001
  Top Layer w8: U3.53@2004.13,786.15 2210.85,786.15 2351.7,927 2858,927 3062,1131 3298,1131 P10.18@3449,1282 P10.17@3549,1282 ; U3.53@2004.13,2951.15 2210.85,2951.15 2351.7,3092 2858,3092 3062,3296 3298,3296 P10.18@3449,3447 P10.17@3549,3447 ; U3.53@5821.06,786.15 6027.78,786.15 6168.63,927 6674.93,927 6878.93,1131 7114.93,1131 P10.18@7265.93,1282 P10.17@7365.93,1282 ; U3.53@5821.06,2951.15 6027.78,2951.15 6168.63,3092 6674.93,3092 6878.93,3296 7114.93,3296 P10.18@7265.93,3447 P10.17@7365.93,3447
PB15: P9.15 P9.16 U3.54 | length 5414.7
  Top Layer w8: U3.54@2004.13,805.83 2204.83,805.83 2341,942 2823,942 3063,1182 P9.16@3102,1182 P9.15@3202,1182 ; U3.54@2004.13,2970.83 2204.83,2970.83 2341,3107 2823,3107 3063,3347 P9.16@3102,3347 P9.15@3202,3347 ; U3.54@5821.06,805.83 6021.76,805.83 6157.93,942 6639.93,942 6879.93,1182 P9.16@6918.93,1182 P9.15@7018.93,1182 ; U3.54@5821.06,2970.83 6021.76,2970.83 6157.93,3107 6639.93,3107 6879.93,3347 P9.16@6918.93,3347 P9.15@7018.93,3347
PC0: P7.17 P7.18 U3.15 | length 9048.7
  Top Layer w10: v1(544,850) 499,805 499,470 620,349 1087,349 P7.18@1253,183 P7.17@1253,83 ; v1(544,3015) 499,2970 499,2635 620,2514 1087,2514 P7.18@1253,2348 P7.17@1253,2248 ; v1(1157,929) 1171.63,943.63 U3.15@1395.87,943.63 ; v1(1157,3094) 1171.63,3108.63 U3.15@1395.87,3108.63 ; v1(4360.93,850) 4315.93,805 4315.93,470 4436.93,349 4903.93,349 P7.18@5069.93,183 P7.17@5069.93,83 ; v1(4360.93,3015) 4315.93,2970 4315.93,2635 4436.93,2514 4903.93,2514 P7.18@5069.93,2348 P7.17@5069.93,2248 ; v1(4973.93,929) 4988.56,943.63 U3.15@5212.79,943.63 ; v1(4973.93,3094) 4988.56,3108.63 U3.15@5212.79,3108.63
  Bottom Layer w10: v1(544,850) 722,850 801,929 v1(1157,929) ; v1(544,3015) 722,3015 801,3094 v1(1157,3094) ; v1(4360.93,850) 4538.93,850 4617.93,929 v1(4973.93,929) ; v1(4360.93,3015) 4538.93,3015 4617.93,3094 v1(4973.93,3094)
PC1: P7.19 P7.20 U3.16 | length 9138.9
  Top Layer w10: v1(700,819) 573,819 519,765 519,480 629,370 1166,370 P7.20@1353,183 P7.19@1353,83 ; v1(700,2984) 573,2984 519,2930 519,2645 629,2535 1166,2535 P7.20@1353,2348 P7.19@1353,2248 ; v1(1160,878) 1205.94,923.94 U3.16@1395.87,923.94 ; v1(1160,3043) 1205.94,3088.94 U3.16@1395.87,3088.94 ; v1(4516.93,819) 4389.93,819 4335.93,765 4335.93,480 4445.93,370 4982.93,370 P7.20@5169.93,183 P7.19@5169.93,83 ; v1(4516.93,2984) 4389.93,2984 4335.93,2930 4335.93,2645 4445.93,2535 4982.93,2535 P7.20@5169.93,2348 P7.19@5169.93,2248 ; v1(4976.93,878) 5022.87,923.94 U3.16@5212.79,923.94 ; v1(4976.93,3043) 5022.87,3088.94 U3.16@5212.79,3088.94
  Bottom Layer w10: v1(700,819) 743,819 802,878 v1(1160,878) ; v1(700,2984) 743,2984 802,3043 v1(1160,3043) ; v1(4516.93,819) 4559.93,819 4618.93,878 v1(4976.93,878) ; v1(4516.93,2984) 4559.93,2984 4618.93,3043 v1(4976.93,3043)
PC2: P7.21 P7.22 U3.17 | length 7017.6
  Top Layer w10: v1(850,816) 850,463 922,391 1245,391 P7.22@1453,183 P7.21@1453,83 ; v1(850,2981) 850,2628 922,2556 1245,2556 P7.22@1453,2348 P7.21@1453,2248 ; v1(1125,846) 1177,846 1235.26,904.26 U3.17@1395.87,904.26 ; v1(1125,3011) 1177,3011 1235.26,3069.26 U3.17@1395.87,3069.26 ; v1(4666.93,816) 4666.93,463 4738.93,391 5061.93,391 P7.22@5269.93,183 P7.21@5269.93,83 ; v1(4666.93,2981) 4666.93,2628 4738.93,2556 5061.93,2556 P7.22@5269.93,2348 P7.21@5269.93,2248 ; v1(4941.93,846) 4993.93,846 5052.19,904.26 U3.17@5212.79,904.26 ; v1(4941.93,3011) 4993.93,3011 5052.19,3069.26 U3.17@5212.79,3069.26
  Bottom Layer w10: v1(850,816) 880,846 v1(1125,846) ; v1(850,2981) 880,3011 v1(1125,3011) ; v1(4666.93,816) 4696.93,846 v1(4941.93,846) ; v1(4666.93,2981) 4696.93,3011 v1(4941.93,3011)
PC3: P7.23 P7.24 U3.18 | length 7032.7
  Top Layer w10: v1(901,800) 875,774 875,486 951,410 1326,410 P7.24@1553,183 P7.23@1553,83 ; v1(901,2965) 875,2939 875,2651 951,2575 1326,2575 P7.24@1553,2348 P7.23@1553,2248 ; v1(1163,814) 1186,814 1256.58,884.58 U3.18@1395.87,884.58 ; v1(1163,2979) 1186,2979 1256.58,3049.58 U3.18@1395.87,3049.58 ; v1(4717.93,800) 4691.93,774 4691.93,486 4767.93,410 5142.93,410 P7.24@5369.93,183 P7.23@5369.93,83 ; v1(4717.93,2965) 4691.93,2939 4691.93,2651 4767.93,2575 5142.93,2575 P7.24@5369.93,2348 P7.23@5369.93,2248 ; v1(4979.93,814) 5002.93,814 5073.5,884.58 U3.18@5212.79,884.58 ; v1(4979.93,2979) 5002.93,2979 5073.5,3049.58 U3.18@5212.79,3049.58
  Bottom Layer w10: v1(901,800) 915,814 v1(1163,814) ; v1(901,2965) 915,2979 v1(1163,2979) ; v1(4717.93,800) 4731.93,814 v1(4979.93,814) ; v1(4717.93,2965) 4731.93,2979 v1(4979.93,2979)
PC4: P7.41 P7.42 U3.33 | length 5043
  Top Layer w8: U3.33@1601.58,678.87 1601.58,501.42 1739,364 2088,364 2174,278 2358,278 P7.42@2453,183 ; U3.33@1601.58,2843.87 1601.58,2666.42 1739,2529 2088,2529 2174,2443 2358,2443 P7.42@2453,2348 ; U3.33@5418.5,678.87 5418.5,501.42 5555.93,364 5904.93,364 5990.93,278 6174.93,278 P7.42@6269.93,183 ; U3.33@5418.5,2843.87 5418.5,2666.42 5555.93,2529 5904.93,2529 5990.93,2443 6174.93,2443 P7.42@6269.93,2348
  Top Layer w10: P7.41@2453,83 P7.42@2453,183 ; P7.41@2453,2248 P7.42@2453,2348 ; P7.41@6269.93,83 P7.42@6269.93,183 ; P7.41@6269.93,2248 P7.42@6269.93,2348
PC5: P7.43 P7.44 U3.34 | length 5648
  Top Layer w8: U3.34@1621.26,678.87 1621.26,510.74 1750,382 2101,382 2186,297 2439,297 P7.44@2553,183 ; U3.34@1621.26,2843.87 1621.26,2675.74 1750,2547 2101,2547 2186,2462 2439,2462 P7.44@2553,2348 ; U3.34@5438.19,678.87 5438.19,510.74 5566.93,382 5917.93,382 6002.93,297 6255.93,297 P7.44@6369.93,183 ; U3.34@5438.19,2843.87 5438.19,2675.74 5566.93,2547 5917.93,2547 6002.93,2462 6255.93,2462 P7.44@6369.93,2348
  Top Layer w10: 2499,237 P7.44@2553,183 P7.43@2553,83 ; 2499,2402 P7.44@2553,2348 P7.43@2553,2248 ; 6315.93,237 P7.44@6369.93,183 P7.43@6369.93,83 ; 6315.93,2402 P7.44@6369.93,2348 P7.43@6369.93,2248
PC6: P10.27 P10.28 U3.63 | length 8007.1
  Top Layer w8: U3.63@2004.14,983 2182,983 2286,1087 2733,1087 2934,1288 2934,1503 3060,1629 3296,1629 P10.28@3449,1782 P10.27@3549,1782 ; U3.63@2004.14,3148 2182,3148 2286,3252 2733,3252 2934,3453 2934,3668 3060,3794 3296,3794 P10.28@3449,3947 P10.27@3549,3947 ; U3.63@5821.06,983 5998.93,983 6102.93,1087 6549.93,1087 6750.93,1288 6750.93,1503 6876.93,1629 7112.93,1629 P10.28@7265.93,1782 P10.27@7365.93,1782 ; U3.63@5821.06,3148 5998.93,3148 6102.93,3252 6549.93,3252 6750.93,3453 6750.93,3668 6876.93,3794 7112.93,3794 P10.28@7265.93,3947 P10.27@7365.93,3947
PC7: P9.25 P9.26 U3.64 | length 6532.7
  Top Layer w8: U3.64@2004.13,1002.68 2179.68,1002.68 2280,1103 2727.79,1103 2919,1294.21 2919,1557 3044,1682 P9.26@3102,1682 P9.25@3202,1682 ; U3.64@2004.13,3167.68 2179.68,3167.68 2280,3268 2727.79,3268 2919,3459.21 2919,3722 3044,3847 P9.26@3102,3847 P9.25@3202,3847 ; U3.64@5821.06,1002.68 5996.61,1002.68 6096.93,1103 6544.72,1103 6735.93,1294.21 6735.93,1557 6860.93,1682 P9.26@6918.93,1682 P9.25@7018.93,1682 ; U3.64@5821.06,3167.68 5996.61,3167.68 6096.93,3268 6544.72,3268 6735.93,3459.21 6735.93,3722 6860.93,3847 P9.26@6918.93,3847 P9.25@7018.93,3847
PC8: P10.29 P10.30 U3.65 | length 8262.2
  Top Layer w8: U3.65@2004.13,1022.37 2177.37,1022.37 2277,1122 2725,1122 2904,1301 2904,1582 3056,1734 3301,1734 P10.30@3449,1882 P10.29@3549,1882 ; U3.65@2004.13,3187.37 2177.37,3187.37 2277,3287 2725,3287 2904,3466 2904,3747 3056,3899 3301,3899 P10.30@3449,4047 P10.29@3549,4047 ; U3.65@5821.06,1022.37 5994.3,1022.37 6093.93,1122 6541.93,1122 6720.93,1301 6720.93,1582 6872.93,1734 7117.93,1734 P10.30@7265.93,1882 P10.29@7365.93,1882 ; U3.65@5821.06,3187.37 5994.3,3187.37 6093.93,3287 6541.93,3287 6720.93,3466 6720.93,3747 6872.93,3899 7117.93,3899 P10.30@7265.93,4047 P10.29@7365.93,4047
PC9: P9.27 P9.28 U3.66 | length 6711
  Top Layer w8: U3.66@2004.13,1042.06 2175.06,1042.06 2272,1139 2717,1139 2889,1311 2889,1607 3064,1782 P9.28@3102,1782 P9.27@3202,1782 ; U3.66@2004.13,3207.06 2175.06,3207.06 2272,3304 2717,3304 2889,3476 2889,3772 3064,3947 P9.28@3102,3947 P9.27@3202,3947 ; U3.66@5821.06,1042.06 5991.98,1042.06 6088.93,1139 6533.93,1139 6705.93,1311 6705.93,1607 6880.93,1782 P9.28@6918.93,1782 P9.27@7018.93,1782 ; U3.66@5821.06,3207.06 5991.98,3207.06 6088.93,3304 6533.93,3304 6705.93,3476 6705.93,3772 6880.93,3947 P9.28@6918.93,3947 P9.27@7018.93,3947
PC10: P8.11 P8.12 U3.78 | length 4255.6
  Top Layer w8: U3.78@1896.85,1287.13 1896.85,1400.85 1896.85,1661.85 2141,1906 2276,1906 P8.12@2353,1983 ; U3.78@1896.85,3452.13 1896.85,3565.85 1896.85,3826.85 2141,4071 2276,4071 P8.12@2353,4148 ; U3.78@5713.78,1287.13 5713.78,1400.85 5713.78,1661.85 5957.93,1906 6092.93,1906 P8.12@6169.93,1983 ; U3.78@5713.78,3452.13 5713.78,3565.85 5713.78,3826.85 5957.93,4071 6092.93,4071 P8.12@6169.93,4148
  Top Layer w10: P8.12@2353,1983 P8.11@2353,2083 ; P8.12@2353,4148 P8.11@2353,4248 ; P8.12@6169.93,1983 P8.11@6169.93,2083 ; P8.12@6169.93,4148 P8.11@6169.93,4248
PC11: P8.13 P8.14 U3.79 | length 3949.1
  Top Layer w8: U3.79@1877.17,1287.13 1877.17,1410.17 1877.17,1668.17 2136,1927 2197,1927 P8.14@2253,1983 ; U3.79@1877.17,3452.13 1877.17,3575.17 1877.17,3833.17 2136,4092 2197,4092 P8.14@2253,4148 ; U3.79@5694.09,1287.13 5694.09,1410.17 5694.09,1668.17 5952.93,1927 6013.93,1927 P8.14@6069.93,1983 ; U3.79@5694.09,3452.13 5694.09,3575.17 5694.09,3833.17 5952.93,4092 6013.93,4092 P8.14@6069.93,4148
  Top Layer w10: P8.14@2253,1983 P8.13@2253,2083 ; P8.14@2253,4148 P8.13@2253,4248 ; P8.14@6069.93,1983 P8.13@6069.93,2083 ; P8.14@6069.93,4148 P8.13@6069.93,4248
PC12: P8.15 P8.16 U3.80 | length 3673.1
  Top Layer w8: U3.80@1857.48,1287.13 1857.48,1419.44 1857.48,1687.48 P8.16@2153,1983 ; U3.80@1857.48,3452.13 1857.48,3584.44 1857.48,3852.48 P8.16@2153,4148 ; U3.80@5674.41,1287.13 5674.41,1419.44 5674.41,1687.48 P8.16@5969.93,1983 ; U3.80@5674.41,3452.13 5674.41,3584.44 5674.41,3852.48 P8.16@5969.93,4148
  Top Layer w10: P8.16@2153,1983 P8.15@2153,2083 ; P8.16@2153,4148 P8.15@2153,4248 ; P8.16@5969.93,1983 P8.15@5969.93,2083 ; P8.16@5969.93,4148 P8.15@5969.93,4248
PC13: P7.11 P7.12 U3.7 | length 9228
  Top Layer w10: v1(511,1081) 445,1015 445,435 591,289 847,289 P7.12@953,183 P7.11@953,83 ; v1(511,3246) 445,3180 445,2600 591,2454 847,2454 P7.12@953,2348 P7.11@953,2248 ; v1(1268,1111) 1277.89,1101.11 U3.7@1395.87,1101.11 ; v1(1268,3276) 1277.89,3266.11 U3.7@1395.87,3266.11 ; v1(4327.93,1081) 4261.93,1015 4261.93,435 4407.93,289 4663.93,289 P7.12@4769.93,183 P7.11@4769.93,83 ; v1(4327.93,3246) 4261.93,3180 4261.93,2600 4407.93,2454 4663.93,2454 P7.12@4769.93,2348 P7.11@4769.93,2248 ; v1(5084.93,1111) 5094.82,1101.11 U3.7@5212.79,1101.11 ; v1(5084.93,3276) 5094.82,3266.11 U3.7@5212.79,3266.11
  Bottom Layer w10: v1(511,1081) 565,1135 1244,1135 v1(1268,1111) ; v1(511,3246) 565,3300 1244,3300 v1(1268,3276) ; v1(4327.93,1081) 4381.93,1135 5060.93,1135 v1(5084.93,1111) ; v1(4327.93,3246) 4381.93,3300 5060.93,3300 v1(5084.93,3276)
PC14: P7.13 P7.14 R7.2 U3.8 | length 10015
  Top Layer w10: v1(510,1016) 465,971 465,445 603,307 929,307 P7.14@1053,183 P7.13@1053,83 ; v1(510,3181) 465,3136 465,2610 603,2472 929,2472 P7.14@1053,2348 P7.13@1053,2248 ; R7.2@1069,1215.14 1079.86,1215.14 v1@1193.5,1101.5 ; R7.2@1069,3380.14 1079.86,3380.14 v1@1193.5,3266.5 ; v1(1194,1102) v1@1193.5,1101.5 ; v1(1194,3267) v1@1193.5,3266.5 ; U3.8@1395.87,1081.43 1213.57,1081.43 v1@1193.5,1101.5 ; U3.8@1395.87,3246.43 1213.57,3246.43 v1@1193.5,3266.5 ; v1(4326.93,1016) 4281.93,971 4281.93,445 4419.93,307 4745.93,307 P7.14@4869.93,183 P7.13@4869.93,83 ; v1(4326.93,3181) 4281.93,3136 4281.93,2610 4419.93,2472 4745.93,2472 P7.14@4869.93,2348 P7.13@4869.93,2248 ; R7.2@4885.93,1215.14 4896.79,1215.14 v1@5010.43,1101.5 ; R7.2@4885.93,3380.14 4896.79,3380.14 v1@5010.43,3266.5 ; v1(5010.93,1102) v1@5010.43,1101.5 ; v1(5010.93,3267) v1@5010.43,3266.5 ; U3.8@5212.79,1081.43 5030.5,1081.43 v1@5010.43,1101.5 ; U3.8@5212.79,3246.43 5030.5,3246.43 v1@5010.43,3266.5
  Bottom Layer w10: v1(510,1016) 596,1102 674,1102 ; v1(510,3181) 596,3267 674,3267 ; 659,1102 674,1102 ; 659,3267 674,3267 ; v1(1194,1102) 674,1102 ; v1(1194,3267) 674,3267 ; v1(4326.93,1016) 4412.93,1102 4490.93,1102 ; v1(4326.93,3181) 4412.93,3267 4490.93,3267 ; 4475.93,1102 4490.93,1102 ; 4475.93,3267 4490.93,3267 ; v1(5010.93,1102) 4490.93,1102 ; v1(5010.93,3267) 4490.93,3267
PC15: P7.15 P7.16 R9.2 U3.9 | length 9831.3
  Top Layer w10: v1@515,962 v1(515,966) 482,933 482,455 608,329 1007,329 P7.16@1153,183 P7.15@1153,83 ; v1@515,3127 v1(515,3131) 482,3098 482,2620 608,2494 1007,2494 P7.16@1153,2348 P7.15@1153,2248 ; R9.2@1069,1138.29 1085.71,1138.29 v1(1162.26,1061.74) U3.9@1395.87,1061.74 ; R9.2@1069,3303.29 1085.71,3303.29 v1(1162.26,3226.74) U3.9@1395.87,3226.74 ; v1@4331.93,962 v1(4331.93,966) 4298.93,933 4298.93,455 4424.93,329 4823.93,329 P7.16@4969.93,183 P7.15@4969.93,83 ; v1@4331.93,3127 v1(4331.93,3131) 4298.93,3098 4298.93,2620 4424.93,2494 4823.93,2494 P7.16@4969.93,2348 P7.15@4969.93,2248 ; R9.2@4885.93,1138.29 4902.64,1138.29 v1(4979.19,1061.74) U3.9@5212.79,1061.74 ; R9.2@4885.93,3303.29 4902.64,3303.29 v1(4979.19,3226.74) U3.9@5212.79,3226.74
  Bottom Layer w10: v1(515,966) 610.74,1061.74 v1(1162.26,1061.74) ; v1(515,3131) 610.74,3226.74 v1(1162.26,3226.74) ; v1(4331.93,966) 4427.67,1061.74 v1(4979.19,1061.74) ; v1(4331.93,3131) 4427.67,3226.74 v1(4979.19,3226.74)
PD0: P8.17 P8.18 U3.81 | length 3540
  Top Layer w8: U3.81@1837.8,1287.14 1837.8,1423.8 1837.8,1767.8 P8.18@2053,1983 ; U3.81@1837.8,3452.14 1837.8,3588.8 1837.8,3932.8 P8.18@2053,4148 ; U3.81@5654.72,1287.14 5654.72,1423.8 5654.72,1767.8 P8.18@5869.93,1983 ; U3.81@5654.72,3452.14 5654.72,3588.8 5654.72,3932.8 P8.18@5869.93,4148
  Top Layer w10: P8.18@2053,1983 P8.17@2053,2083 ; P8.18@2053,4148 P8.17@2053,4248 ; P8.18@5869.93,1983 P8.17@5869.93,2083 ; P8.18@5869.93,4148 P8.17@5869.93,4248
PD1: P8.19 P8.20 U3.82 | length 3407
  Top Layer w8: U3.82@1818.11,1287.13 1818.11,1431.11 1818.11,1848.11 P8.20@1953,1983 ; U3.82@1818.11,3452.13 1818.11,3596.11 1818.11,4013.11 P8.20@1953,4148 ; U3.82@5635.04,1287.13 5635.04,1431.11 5635.04,1848.11 P8.20@5769.93,1983 ; U3.82@5635.04,3452.13 5635.04,3596.11 5635.04,4013.11 P8.20@5769.93,4148
  Top Layer w10: P8.20@1953,1983 P8.19@1953,2083 ; P8.20@1953,4148 P8.19@1953,4248 ; P8.20@5769.93,1983 P8.19@5769.93,2083 ; P8.20@5769.93,4148 P8.19@5769.93,4248
PD2: P8.21 P8.22 U3.83 | length 3273.9
  Top Layer w8: U3.83@1798.43,1287.13 1798.43,1440.43 1798.43,1928.43 P8.22@1853,1983 ; U3.83@1798.43,3452.13 1798.43,3605.43 1798.43,4093.43 P8.22@1853,4148 ; U3.83@5615.35,1287.13 5615.35,1440.43 5615.35,1928.43 P8.22@5669.93,1983 ; U3.83@5615.35,3452.13 5615.35,3605.43 5615.35,4093.43 P8.22@5669.93,4148
  Top Layer w10: P8.22@1853,1983 P8.21@1853,2083 ; P8.22@1853,4148 P8.21@1853,4248 ; P8.22@5669.93,1983 P8.21@5669.93,2083 ; P8.22@5669.93,4148 P8.21@5669.93,4248
PD3: P8.23 P8.24 U3.84 | length 3226.1
  Top Layer w8: P8.24@1753,1983 1778.74,1957.26 1778.74,1448.74 U3.84@1778.74,1287.13 ; P8.24@1753,4148 1778.74,4122.26 1778.74,3613.74 U3.84@1778.74,3452.13 ; P8.24@5569.93,1983 5595.67,1957.26 5595.67,1448.74 U3.84@5595.67,1287.13 ; P8.24@5569.93,4148 5595.67,4122.26 5595.67,3613.74 U3.84@5595.67,3452.13
  Top Layer w11: P8.24@1753,1983 P8.23@1753,2083 ; P8.24@1753,4148 P8.23@1753,4248 ; P8.24@5569.93,1983 P8.23@5569.93,2083 ; P8.24@5569.93,4148 P8.23@5569.93,4248
PD4: P8.25 P8.26 U3.85 | length 3359.2
  Top Layer w8: P8.26@1653,1983 1759.05,1876.95 1759.05,1462.05 U3.85@1759.05,1287.14 ; P8.26@1653,4148 1759.05,4041.95 1759.05,3627.05 U3.85@1759.05,3452.14 ; P8.26@5469.93,1983 5575.98,1876.95 5575.98,1462.05 U3.85@5575.98,1287.14 ; P8.26@5469.93,4148 5575.98,4041.95 5575.98,3627.05 U3.85@5575.98,3452.14
  Top Layer w11: P8.26@1653,1983 P8.25@1653,2083 ; P8.26@1653,4148 P8.25@1653,4248 ; P8.26@5469.93,1983 P8.25@5469.93,2083 ; P8.26@5469.93,4148 P8.25@5469.93,4248
PD5: P8.27 P8.28 U3.86 | length 3492.3
  Top Layer w8: P8.28@1553,1983 1739.37,1796.63 1739.37,1476.37 U3.86@1739.37,1287.13 ; P8.28@1553,4148 1739.37,3961.63 1739.37,3641.37 U3.86@1739.37,3452.13 ; P8.28@5369.93,1983 5556.3,1796.63 5556.3,1476.37 U3.86@5556.3,1287.13 ; P8.28@5369.93,4148 5556.3,3961.63 5556.3,3641.37 U3.86@5556.3,3452.13
  Top Layer w11: P8.28@1553,1983 P8.27@1553,2083 ; P8.28@1553,4148 P8.27@1553,4248 ; P8.28@5369.93,1983 P8.27@5369.93,2083 ; P8.28@5369.93,4148 P8.27@5369.93,4248
PD6: P8.29 P8.30 U3.87 | length 3669.8
  Top Layer w8: P8.30@1472,1983 1719.68,1735.32 1719.68,1483.68 U3.87@1719.68,1287.13 ; P8.30@1472,4148 1719.68,3900.32 1719.68,3648.68 U3.87@1719.68,3452.13 ; P8.30@5288.93,1983 5536.61,1735.32 5536.61,1483.68 U3.87@5536.61,1287.13 ; P8.30@5288.93,4148 5536.61,3900.32 5536.61,3648.68 U3.87@5536.61,3452.13
  Top Layer w11: P8.29@1453,2083 P8.30@1453,1983 P8.30@1472,1983 ; P8.29@1453,4248 P8.30@1453,4148 P8.30@1472,4148 ; P8.29@5269.93,2083 P8.30@5269.93,1983 P8.30@5288.93,1983 ; P8.29@5269.93,4248 P8.30@5269.93,4148 P8.30@5288.93,4148
PD7: P8.31 P8.32 U3.88 | length 3970.3
  Top Layer w8: P8.32@1353,1983 1414,1922 1504.46,1922 1700,1726.46 1700,1491 U3.88@1700,1287.14 ; P8.32@1353,4148 1414,4087 1504.46,4087 1700,3891.46 1700,3656 U3.88@1700,3452.14 ; P8.32@5169.93,1983 5230.93,1922 5321.38,1922 5516.93,1726.46 5516.93,1491 U3.88@5516.93,1287.14 ; P8.32@5169.93,4148 5230.93,4087 5321.38,4087 5516.93,3891.46 5516.93,3656 U3.88@5516.93,3452.14
  Top Layer w11: P8.32@1353,1983 P8.31@1353,2083 ; P8.32@1353,4148 P8.31@1353,4248 ; P8.32@5169.93,1983 P8.31@5169.93,2083 ; P8.32@5169.93,4148 P8.31@5169.93,4248
PD8: P10.19 P10.20 U3.55 | length 7101.5
  Top Layer w8: U3.55@2004.13,825.52 2203.31,825.52 2336.79,959 2797,959 3071,1233 3300,1233 P10.20@3449,1382 P10.19@3549,1382 ; U3.55@2004.13,2990.52 2203.31,2990.52 2336.79,3124 2797,3124 3071,3398 3300,3398 P10.20@3449,3547 P10.19@3549,3547 ; U3.55@5821.06,825.52 6020.24,825.52 6153.72,959 6613.93,959 6887.93,1233 7116.93,1233 P10.20@7265.93,1382 P10.19@7365.93,1382 ; U3.55@5821.06,2990.52 6020.24,2990.52 6153.72,3124 6613.93,3124 6887.93,3398 7116.93,3398 P10.20@7265.93,3547 P10.19@7365.93,3547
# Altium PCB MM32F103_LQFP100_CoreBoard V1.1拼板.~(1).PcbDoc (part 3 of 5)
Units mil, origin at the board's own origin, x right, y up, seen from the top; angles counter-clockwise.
Board outline 7436.93 x 4329.96 mil, 2 copper layers (Top Layer, Bottom Layer); 260 components, 116 nets, 1796 pads, 448 vias.

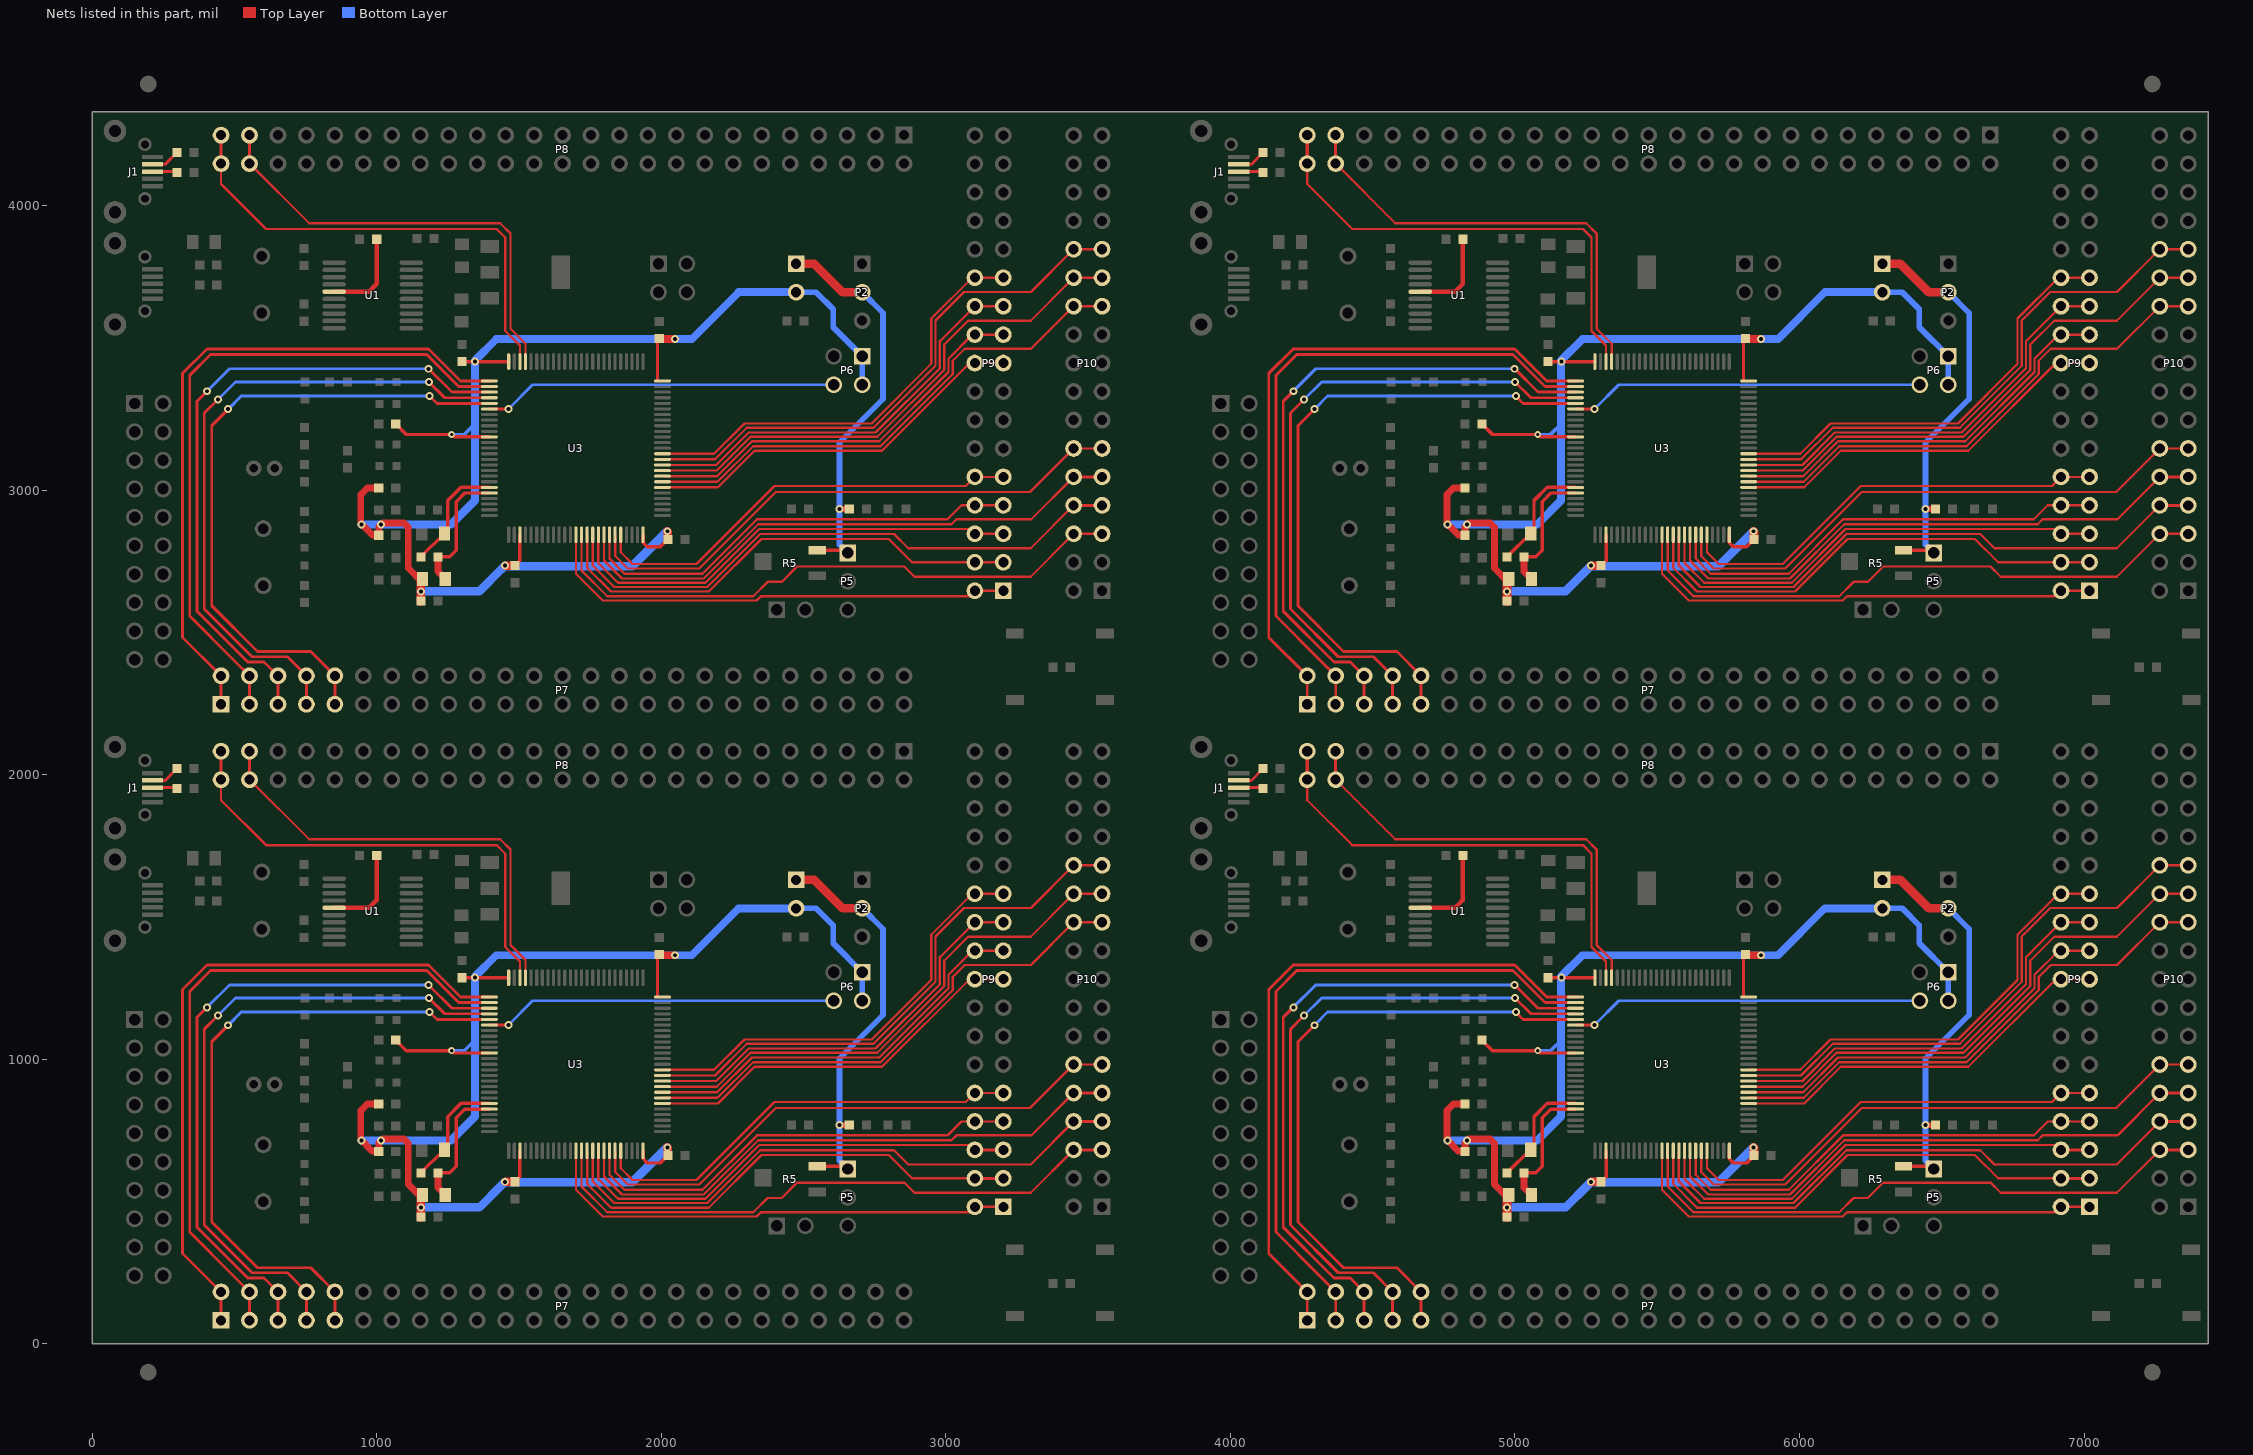
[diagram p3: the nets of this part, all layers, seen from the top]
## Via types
v1: diameter 28, hole 14, Top Layer to Bottom Layer, 228 vias
v2: diameter 24, hole 12, Top Layer to Bottom Layer, 220 vias

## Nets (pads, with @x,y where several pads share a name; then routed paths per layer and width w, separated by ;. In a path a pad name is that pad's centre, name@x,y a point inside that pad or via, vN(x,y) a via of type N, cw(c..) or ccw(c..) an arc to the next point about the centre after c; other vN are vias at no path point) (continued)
PD9: P9.17 P9.18 U3.56 | length 5515.2
  Top Layer w8: U3.56@2004.14,845.2 2199.2,845.2 2328,974 2776,974 3084,1282 P9.18@3102,1282 P9.17@3202,1282 ; U3.56@2004.14,3010.2 2199.2,3010.2 2328,3139 2776,3139 3084,3447 P9.18@3102,3447 P9.17@3202,3447 ; U3.56@5821.06,845.2 6016.13,845.2 6144.93,974 6592.93,974 6900.93,1282 P9.18@6918.93,1282 P9.17@7018.93,1282 ; U3.56@5821.06,3010.2 6016.13,3010.2 6144.93,3139 6592.93,3139 6900.93,3447 P9.18@6918.93,3447 P9.17@7018.93,3447
PD10: P10.21 P10.22 U3.57 | length 7309.7
  Top Layer w8: U3.57@2004.13,864.89 2197.68,864.89 2322.79,990 2770,990 3024,1244 3024,1290 3066,1332 3299,1332 P10.22@3449,1482 P10.21@3549,1482 ; U3.57@2004.13,3029.89 2197.68,3029.89 2322.79,3155 2770,3155 3024,3409 3024,3455 3066,3497 3299,3497 P10.22@3449,3647 P10.21@3549,3647 ; U3.57@5821.06,864.89 6014.61,864.89 6139.72,990 6586.93,990 6840.93,1244 6840.93,1290 6882.93,1332 7115.93,1332 P10.22@7265.93,1482 P10.21@7365.93,1482 ; U3.57@5821.06,3029.89 6014.61,3029.89 6139.72,3155 6586.93,3155 6840.93,3409 6840.93,3455 6882.93,3497 7115.93,3497 P10.22@7265.93,3647 P10.21@7365.93,3647
PD11: P9.19 P9.20 U3.58 | length 5725.8
  Top Layer w8: U3.58@2004.13,884.58 2196.15,884.58 2318.57,1007 2765.79,1007 3009,1250.21 3009,1297.21 3093.79,1382 P9.20@3102,1382 P9.19@3202,1382 ; U3.58@2004.13,3049.58 2196.15,3049.58 2318.57,3172 2765.79,3172 3009,3415.21 3009,3462.21 3093.79,3547 P9.20@3102,3547 P9.19@3202,3547 ; U3.58@5821.06,884.58 6013.08,884.58 6135.5,1007 6582.72,1007 6825.93,1250.21 6825.93,1297.21 6910.72,1382 P9.20@6918.93,1382 P9.19@7018.93,1382 ; U3.58@5821.06,3049.58 6013.08,3049.58 6135.5,3172 6582.72,3172 6825.93,3415.21 6825.93,3462.21 6910.72,3547 P9.20@6918.93,3547 P9.19@7018.93,3547
PD12: P10.23 P10.24 U3.59 | length 7510.9
  Top Layer w8: U3.59@2004.13,904.26 2194.62,904.26 2313.36,1023 2759,1023 2994,1258 2994,1347 3078,1431 3298,1431 P10.24@3449,1582 P10.23@3549,1582 ; U3.59@2004.13,3069.26 2194.62,3069.26 2313.36,3188 2759,3188 2994,3423 2994,3512 3078,3596 3298,3596 P10.24@3449,3747 P10.23@3549,3747 ; U3.59@5821.06,904.26 6011.55,904.26 6130.29,1023 6575.93,1023 6810.93,1258 6810.93,1347 6894.93,1431 7114.93,1431 P10.24@7265.93,1582 P10.23@7365.93,1582 ; U3.59@5821.06,3069.26 6011.55,3069.26 6130.29,3188 6575.93,3188 6810.93,3423 6810.93,3512 6894.93,3596 7114.93,3596 P10.24@7265.93,3747 P10.23@7365.93,3747
PD13: P9.21 P9.22 U3.60 | length 5938.2
  Top Layer w8: U3.60@2004.13,923.94 2193.09,923.94 2307.15,1038 2752.79,1038 2979,1264.21 2979,1359 P9.22@3102,1482 P9.21@3202,1482 ; U3.60@2004.13,3088.94 2193.09,3088.94 2307.15,3203 2752.79,3203 2979,3429.21 2979,3524 P9.22@3102,3647 P9.21@3202,3647 ; U3.60@5821.06,923.94 6010.02,923.94 6124.08,1038 6569.72,1038 6795.93,1264.21 6795.93,1359 P9.22@6918.93,1482 P9.21@7018.93,1482 ; U3.60@5821.06,3088.94 6010.02,3088.94 6124.08,3203 6569.72,3203 6795.93,3429.21 6795.93,3524 P9.22@6918.93,3647 P9.21@7018.93,3647
PD14: P10.25 P10.26 U3.61 | length 7775.4
  Top Layer w8: U3.61@2004.13,943.63 2188.63,943.63 2300,1055 2746,1055 2964,1273 2964,1432 3064,1532 3299,1532 P10.26@3449,1682 P10.25@3549,1682 ; U3.61@2004.13,3108.63 2188.63,3108.63 2300,3220 2746,3220 2964,3438 2964,3597 3064,3697 3299,3697 P10.26@3449,3847 P10.25@3549,3847 ; U3.61@5821.06,943.63 6005.56,943.63 6116.93,1055 6562.93,1055 6780.93,1273 6780.93,1432 6880.93,1532 7115.93,1532 P10.26@7265.93,1682 P10.25@7365.93,1682 ; U3.61@5821.06,3108.63 6005.56,3108.63 6116.93,3220 6562.93,3220 6780.93,3438 6780.93,3597 6880.93,3697 7115.93,3697 P10.26@7265.93,3847 P10.25@7365.93,3847
PD15: P9.23 P9.24 U3.62 | length 6189.1
  Top Layer w8: U3.62@2004.13,963.32 2185.32,963.32 2292,1070 2739.79,1070 2949,1279.21 2949,1438.21 3092.79,1582 P9.24@3102,1582 P9.23@3202,1582 ; U3.62@2004.13,3128.32 2185.32,3128.32 2292,3235 2739.79,3235 2949,3444.21 2949,3603.21 3092.79,3747 P9.24@3102,3747 P9.23@3202,3747 ; U3.62@5821.06,963.32 6002.24,963.32 6108.93,1070 6556.72,1070 6765.93,1279.21 6765.93,1438.21 6909.72,1582 P9.24@6918.93,1582 P9.23@7018.93,1582 ; U3.62@5821.06,3128.32 6002.24,3128.32 6108.93,3235 6556.72,3235 6765.93,3444.21 6765.93,3603.21 6909.72,3747 P9.24@6918.93,3747 P9.23@7018.93,3747
PE0: P8.47 P8.48 U3.97 | length 6363.7
  Top Layer w8: P8.48@553,1983 762.5,1773.5 1433.96,1773.5 1470,1737.46 1470,1402.46 1522.83,1349.62 U3.97@1522.83,1287.13 ; P8.48@553,4148 762.5,3938.5 1433.96,3938.5 1470,3902.46 1470,3567.46 1522.83,3514.62 U3.97@1522.83,3452.13 ; P8.48@4369.93,1983 4579.43,1773.5 5250.88,1773.5 5286.93,1737.46 5286.93,1402.46 5339.76,1349.62 U3.97@5339.76,1287.13 ; P8.48@4369.93,4148 4579.43,3938.5 5250.88,3938.5 5286.93,3902.46 5286.93,3567.46 5339.76,3514.62 U3.97@5339.76,3452.13
  Top Layer w11: P8.48@553,1983 P8.47@553,2083 ; P8.48@553,4148 P8.47@553,4248 ; P8.48@4369.93,1983 P8.47@4369.93,2083 ; P8.48@4369.93,4148 P8.47@4369.93,4248
PE1: P8.49 P8.50 U3.98 | length 6823.7
  Top Layer w8: P8.50@453,1983 453,1911 611,1753 1422,1753 1452,1723 1452,1395 1503.15,1343.85 U3.98@1503.15,1287.13 ; P8.50@453,4148 453,4076 611,3918 1422,3918 1452,3888 1452,3560 1503.15,3508.85 U3.98@1503.15,3452.13 ; P8.50@4269.93,1983 4269.93,1911 4427.93,1753 5238.93,1753 5268.93,1723 5268.93,1395 5320.08,1343.85 U3.98@5320.08,1287.13 ; P8.50@4269.93,4148 4269.93,4076 4427.93,3918 5238.93,3918 5268.93,3888 5268.93,3560 5320.08,3508.85 U3.98@5320.08,3452.13
  Top Layer w11: P8.50@453,1983 P8.49@453,2083 ; P8.50@453,4148 P8.49@453,4248 ; P8.50@4269.93,1983 P8.49@4269.93,2083 ; P8.50@4269.93,4148 P8.49@4269.93,4248
PE2: P7.1 P7.2 U3.1 | length 9553
  Top Layer w10: P7.1@453,83 P7.2@453,183 318,318 318,1246 404,1332 1182,1332 1294.78,1219.22 U3.1@1405,1219.22 ; P7.1@453,2248 P7.2@453,2348 318,2483 318,3411 404,3497 1182,3497 1294.78,3384.22 U3.1@1405,3384.22 ; P7.1@4269.93,83 P7.2@4269.93,183 4134.93,318 4134.93,1246 4220.93,1332 4998.93,1332 5111.71,1219.22 U3.1@5221.93,1219.22 ; P7.1@4269.93,2248 P7.2@4269.93,2348 4134.93,2483 4134.93,3411 4220.93,3497 4998.93,3497 5111.71,3384.22 U3.1@5221.93,3384.22
PE3: P7.3 P7.4 U3.2 | length 9490.7
  Top Layer w10: P7.3@553,83 P7.4@553,183 497,239 343,393 343,1239 416,1312 1176,1312 1288.47,1199.53 U3.2@1395.87,1199.53 ; P7.3@553,2248 P7.4@553,2348 497,2404 343,2558 343,3404 416,3477 1176,3477 1288.47,3364.53 U3.2@1395.87,3364.53 ; P7.3@4369.93,83 P7.4@4369.93,183 4313.93,239 4159.93,393 4159.93,1239 4232.93,1312 4992.93,1312 5105.39,1199.53 U3.2@5212.79,1199.53 ; P7.3@4369.93,2248 P7.4@4369.93,2348 4313.93,2404 4159.93,2558 4159.93,3404 4232.93,3477 4992.93,3477 5105.39,3364.53 U3.2@5212.79,3364.53
PE4: P7.5 P7.6 U3.3 | length 9296.6
  Top Layer w10: v1(404,1183) 369,1148 369,410 547,232 604,232 P7.6@653,183 P7.5@653,83 ; v1(404,3348) 369,3313 369,2575 547,2397 604,2397 P7.6@653,2348 P7.5@653,2248 ; v1(1182,1262) 1264.15,1179.85 U3.3@1395.87,1179.85 ; v1(1182,3427) 1264.15,3344.85 U3.3@1395.87,3344.85 ; v1(4220.93,1183) 4185.93,1148 4185.93,410 4363.93,232 4420.93,232 P7.6@4469.93,183 P7.5@4469.93,83 ; v1(4220.93,3348) 4185.93,3313 4185.93,2575 4363.93,2397 4420.93,2397 P7.6@4469.93,2348 P7.5@4469.93,2248 ; v1(4998.93,1262) 5081.08,1179.85 U3.3@5212.79,1179.85 ; v1(4998.93,3427) 5081.08,3344.85 U3.3@5212.79,3344.85
  Bottom Layer w10: v1(404,1183) 483,1262 v1(1182,1262) ; v1(404,3348) 483,3427 v1(1182,3427) ; v1(4220.93,1183) 4299.93,1262 v1(4998.93,1262) ; v1(4220.93,3348) 4299.93,3427 v1(4998.93,3427)
PE5: P7.7 P7.8 U3.4 | length 9259.6
  Top Layer w10: v1(442,1154) 394,1106 394,418 562,250 686,250 P7.8@753,183 P7.7@753,83 ; v1(442,3319) 394,3271 394,2583 562,2415 686,2415 P7.8@753,2348 P7.7@753,2248 ; v1(1183,1216) 1238.83,1160.17 U3.4@1395.87,1160.17 ; v1(1183,3381) 1238.83,3325.17 U3.4@1395.87,3325.17 ; v1(4258.93,1154) 4210.93,1106 4210.93,418 4378.93,250 4502.93,250 P7.8@4569.93,183 P7.7@4569.93,83 ; v1(4258.93,3319) 4210.93,3271 4210.93,2583 4378.93,2415 4502.93,2415 P7.8@4569.93,2348 P7.7@4569.93,2248 ; v1(4999.93,1216) 5055.76,1160.17 U3.4@5212.79,1160.17 ; v1(4999.93,3381) 5055.76,3325.17 U3.4@5212.79,3325.17
  Bottom Layer w10: v1(442,1154) 504,1216 v1(1183,1216) ; v1(442,3319) 504,3381 v1(1183,3381) ; v1(4258.93,1154) 4320.93,1216 v1(4999.93,1216) ; v1(4258.93,3319) 4320.93,3381 v1(4999.93,3381)
PE6: P7.9 P7.10 U3.5 | length 9189.6
  Top Layer w10: v1(478,1120) 420,1062 420,429 581,268 768,268 P7.10@853,183 P7.9@853,83 ; v1(478,3285) 420,3227 420,2594 581,2433 768,2433 P7.10@853,2348 P7.9@853,2248 ; v1(1186,1166) 1211.52,1140.48 U3.5@1395.87,1140.48 ; v1(1186,3331) 1211.52,3305.48 U3.5@1395.87,3305.48 ; v1(4294.93,1120) 4236.93,1062 4236.93,429 4397.93,268 4584.93,268 P7.10@4669.93,183 P7.9@4669.93,83 ; v1(4294.93,3285) 4236.93,3227 4236.93,2594 4397.93,2433 4584.93,2433 P7.10@4669.93,2348 P7.9@4669.93,2248 ; v1(5002.93,1166) 5028.45,1140.48 U3.5@5212.79,1140.48 ; v1(5002.93,3331) 5028.45,3305.48 U3.5@5212.79,3305.48
  Bottom Layer w10: v1(478,1120) 524,1166 v1(1186,1166) ; v1(478,3285) 524,3331 v1(1186,3331) ; v1(4294.93,1120) 4340.93,1166 v1(5002.93,1166) ; v1(4294.93,3285) 4340.93,3331 v1(5002.93,3331)
PE7: P9.1 P9.2 U3.38 | length 6767.5
  Top Layer w8: U3.38@1700,678.86 1700,542 1794,448 2335,448 2350,463 P9.2@3083,463 ; U3.38@1700,2843.86 1700,2707 1794,2613 2335,2613 2350,2628 P9.2@3083,2628 ; U3.38@5516.93,678.86 5516.93,542 5610.93,448 6151.93,448 6166.93,463 P9.2@6899.93,463 ; U3.38@5516.93,2843.86 5516.93,2707 5610.93,2613 6151.93,2613 6166.93,2628 P9.2@6899.93,2628
  Top Layer w10: P9.2@3083,463 P9.2@3102,482 P9.1@3202,482 ; P9.2@3083,2628 P9.2@3102,2647 P9.1@3202,2647 ; P9.2@6899.93,463 P9.2@6918.93,482 P9.1@7018.93,482 ; P9.2@6899.93,2628 P9.2@6918.93,2647 P9.1@7018.93,2647
PE8: P10.5 P10.6 U3.39 | length 8451.2
  Top Layer w8: U3.39@1719.68,678.87 1719.68,553.32 1810,463 2323,463 2373.08,513.08 2423.08,513.08 2477,567 2854,567 2890,531 3298,531 P10.6@3449,682 ; U3.39@1719.68,2843.87 1719.68,2718.32 1810,2628 2323,2628 2373.08,2678.08 2423.08,2678.08 2477,2732 2854,2732 2890,2696 3298,2696 P10.6@3449,2847 ; U3.39@5536.61,678.87 5536.61,553.32 5626.93,463 6139.93,463 6190,513.08 6240,513.08 6293.93,567 6670.93,567 6706.93,531 7114.93,531 P10.6@7265.93,682 ; U3.39@5536.61,2843.87 5536.61,2718.32 5626.93,2628 6139.93,2628 6190,2678.08 6240,2678.08 6293.93,2732 6670.93,2732 6706.93,2696 7114.93,2696 P10.6@7265.93,2847
  Top Layer w10: P10.6@3449,682 P10.5@3549,682 ; P10.6@3449,2847 P10.5@3549,2847 ; P10.6@7265.93,682 P10.5@7365.93,682 ; P10.6@7265.93,2847 P10.5@7365.93,2847
PE9: P9.3 P9.4 U3.40 | length 6896.4
  Top Layer w8: U3.40@1739.37,678.87 1739.37,562.63 1823,479 2167,479 2352,664 2799,664 2881,582 P9.4@3102,582 ; U3.40@1739.37,2843.87 1739.37,2727.63 1823,2644 2167,2644 2352,2829 2799,2829 2881,2747 P9.4@3102,2747 ; U3.40@5556.3,678.87 5556.3,562.63 5639.93,479 5983.93,479 6168.93,664 6615.93,664 6697.93,582 P9.4@6918.93,582 ; U3.40@5556.3,2843.87 5556.3,2727.63 5639.93,2644 5983.93,2644 6168.93,2829 6615.93,2829 6697.93,2747 P9.4@6918.93,2747
  Top Layer w10: P9.4@3102,582 P9.3@3202,582 ; P9.4@3102,2747 P9.3@3202,2747 ; P9.4@6918.93,582 P9.3@7018.93,582 ; P9.4@6918.93,2747 P9.3@7018.93,2747
PE10: P10.7 P10.8 U3.41 | length 8358.5
  Top Layer w8: U3.41@1759.05,678.86 1759.05,570.95 1835,495 2161.79,495 2347.79,681 2818,681 2868,631 3298,631 P10.8@3449,782 ; U3.41@1759.05,2843.86 1759.05,2735.95 1835,2660 2161.79,2660 2347.79,2846 2818,2846 2868,2796 3298,2796 P10.8@3449,2947 ; U3.41@5575.98,678.86 5575.98,570.95 5651.93,495 5978.72,495 6164.72,681 6634.93,681 6684.93,631 7114.93,631 P10.8@7265.93,782 ; U3.41@5575.98,2843.86 5575.98,2735.95 5651.93,2660 5978.72,2660 6164.72,2846 6634.93,2846 6684.93,2796 7114.93,2796 P10.8@7265.93,2947
  Top Layer w10: P10.8@3449,782 P10.7@3549,782 ; P10.8@3449,2947 P10.7@3549,2947 ; P10.8@7265.93,782 P10.7@7365.93,782 ; P10.8@7265.93,2947 P10.7@7365.93,2947
PE11: P9.5 P9.6 U3.42 | length 6547.5
  Top Layer w8: U3.42@1778.74,678.87 1778.74,579.26 1848,510 2155.57,510 2344.57,699 P9.6@3085,699 ; U3.42@1778.74,2843.87 1778.74,2744.26 1848,2675 2155.57,2675 2344.57,2864 P9.6@3085,2864 ; U3.42@5595.67,678.87 5595.67,579.26 5664.93,510 5972.5,510 6161.5,699 P9.6@6901.93,699 ; U3.42@5595.67,2843.87 5595.67,2744.26 5664.93,2675 5972.5,2675 6161.5,2864 P9.6@6901.93,2864
  Top Layer w10: P9.6@3085,699 P9.6@3102,682 P9.5@3202,682 ; P9.6@3085,2864 P9.6@3102,2847 P9.5@3202,2847 ; P9.6@6901.93,699 P9.6@6918.93,682 P9.5@7018.93,682 ; P9.6@6901.93,2864 P9.6@6918.93,2847 P9.5@7018.93,2847
PE12: P10.9 P10.10 U3.43 | length 8060.3
  Top Layer w8: U3.43@1798.43,678.87 1798.43,588.57 1862,525 2149.36,525 2340.36,716 3020,716 3037,733 3300,733 P10.10@3449,882 ; U3.43@1798.43,2843.87 1798.43,2753.57 1862,2690 2149.36,2690 2340.36,2881 3020,2881 3037,2898 3300,2898 P10.10@3449,3047 ; U3.43@5615.35,678.87 5615.35,588.57 5678.93,525 5966.29,525 6157.29,716 6836.93,716 6853.93,733 7116.93,733 P10.10@7265.93,882 ; U3.43@5615.35,2843.87 5615.35,2753.57 5678.93,2690 5966.29,2690 6157.29,2881 6836.93,2881 6853.93,2898 7116.93,2898 P10.10@7265.93,3047
  Top Layer w10: P10.10@3449,882 P10.9@3549,882 ; P10.10@3449,3047 P10.9@3549,3047 ; P10.10@7265.93,882 P10.9@7365.93,882 ; P10.10@7265.93,3047 P10.9@7365.93,3047
PE13: P9.7 P9.8 U3.44 | length 6356.7
  Top Layer w8: U3.44@1818.11,678.87 1818.11,594.89 1871,542 2145.15,542 2336.15,733 3006,733 3055,782 P9.8@3102,782 P9.7@3202,782 ; U3.44@1818.11,2843.87 1818.11,2759.89 1871,2707 2145.15,2707 2336.15,2898 3006,2898 3055,2947 P9.8@3102,2947 P9.7@3202,2947 ; U3.44@5635.04,678.87 5635.04,594.89 5687.93,542 5962.08,542 6153.08,733 6822.93,733 6871.93,782 P9.8@6918.93,782 P9.7@7018.93,782 ; U3.44@5635.04,2843.87 5635.04,2759.89 5687.93,2707 5962.08,2707 6153.08,2898 6822.93,2898 6871.93,2947 P9.8@6918.93,2947 P9.7@7018.93,2947
PE14: P10.11 P10.12 U3.45 | length 7915.9
  Top Layer w8: U3.45@1837.8,678.86 1837.8,604.2 1882,560 2107,560 2133,560 2402,829 3009,829 3296,829 P10.12@3449,982 P10.11@3549,982 ; U3.45@1837.8,2843.86 1837.8,2769.2 1882,2725 2107,2725 2133,2725 2402,2994 3009,2994 3296,2994 P10.12@3449,3147 P10.11@3549,3147 ; U3.45@5654.72,678.86 5654.72,604.2 5698.93,560 5923.93,560 5949.93,560 6218.93,829 6825.93,829 7112.93,829 P10.12@7265.93,982 P10.11@7365.93,982 ; U3.45@5654.72,2843.86 5654.72,2769.2 5698.93,2725 5923.93,2725 5949.93,2725 6218.93,2994 6825.93,2994 7112.93,2994 P10.12@7265.93,3147 P10.11@7365.93,3147
PE15: P9.9 P9.10 U3.46 | length 6199.3
  Top Layer w8: U3.46@1857.48,678.87 1857.48,617.52 1899,576 2101,576 2124,576 2398,850 3070,850 P9.10@3102,882 P9.9@3202,882 ; U3.46@1857.48,2843.87 1857.48,2782.52 1899,2741 2101,2741 2124,2741 2398,3015 3070,3015 P9.10@3102,3047 P9.9@3202,3047 ; U3.46@5674.41,678.87 5674.41,617.52 5715.93,576 5917.93,576 5940.93,576 6214.93,850 6886.93,850 P9.10@6918.93,882 P9.9@7018.93,882 ; U3.46@5674.41,2843.87 5674.41,2782.52 5715.93,2741 5917.93,2741 5940.93,2741 6214.93,3015 6886.93,3015 P9.10@6918.93,3047 P9.9@7018.93,3047
USB_DN: J1.2 R1.1 | length 412.6
  Top Layer w10: J1.2@212,1980.59 256.59,1980.59 R1.1@298,2022 ; J1.2@212,4145.59 256.59,4145.59 R1.1@298,4187 ; J1.2@4028.93,1980.59 4073.52,1980.59 R1.1@4114.93,2022 ; J1.2@4028.93,4145.59 4073.52,4145.59 R1.1@4114.93,4187
USB_DP: J1.3 R3.1 | length 345.6
  Top Layer w10: J1.3@212,1955 297,1955 R3.1@298,1954 ; J1.3@212,4120 297,4120 R3.1@298,4119 ; J1.3@4028.93,1955 4113.93,1955 R3.1@4114.93,1954 ; J1.3@4028.93,4120 4113.93,4120 R3.1@4114.93,4119
VBAT: P6.4 U3.6 | length 4981.6
  Top Layer w10: U3.6@1395.86,1120.8 1396.07,1121 v1(1463,1121) ; U3.6@1395.86,3285.8 1396.07,3286 v1(1463,3286) ; U3.6@5212.79,1120.8 5213,1121 v1(5279.93,1121) ; U3.6@5212.79,3285.8 5213,3286 v1(5279.93,3286)
  Bottom Layer w10: v1(1463,1121) 1547.94,1205.94 P6.4@2606,1205.94 ; v1(1463,3286) 1547.94,3370.94 P6.4@2606,3370.94 ; v1(5279.93,1121) 5364.87,1205.94 P6.4@6422.93,1205.94 ; v1(5279.93,3286) 5364.87,3370.94 P6.4@6422.93,3370.94
VCC_MCU: C6.1 C16.2 C18.1 C19.1 C20.1 C21.1 L1.1 P4.2 P6.1 P6.2 R17.2 R19.2 U3.11 U3.28 U3.50 U3.75 U3.100 | length 21564.9
  Top Layer w11: C6.1@1299,1287 C6.1@1299.13,1287.13 ; C6.1@1299,3452 C6.1@1299.13,3452.13 ; U3.75@1986.13,1219.22 1986.13,1361.13 C18.1@1993,1368 ; U3.75@1986.13,3384.22 1986.13,3526.13 C18.1@1993,3533 ; C6.1@5115.93,1287 C6.1@5116.06,1287.13 ; C6.1@5115.93,3452 C6.1@5116.06,3452.13 ; U3.75@5803.06,1219.22 5803.06,1361.13 C18.1@5809.93,1368 ; U3.75@5803.06,3384.22 5803.06,3526.13 C18.1@5809.93,3533
  Top Layer w12: C20.1@1067,1068 1104,1031 v2(1263,1031) 1271.63,1022.37 U3.11@1395.87,1022.37 ; C20.1@1067,3233 1104,3196 v2(1263,3196) 1271.63,3187.37 U3.11@1395.87,3187.37 ; C6.1@1299.13,1287.13 v1(1346,1287.13) U3.100@1463.78,1287.13 ; C6.1@1299.13,3452.13 v1(1346,3452.13) U3.100@1463.78,3452.13 ; C19.1@1486,570 1503.15,587.15 U3.28@1503.15,678.87 ; C19.1@1486,2735 1503.15,2752.15 U3.28@1503.15,2843.87 ; U3.50@1936.22,678.87 1936.22,650.78 1951,636 1997,636 C16.2@2023,662 ; U3.50@1936.22,2843.87 1936.22,2815.78 1951,2801 1997,2801 C16.2@2023,2827 ; C20.1@4883.93,1068 4920.93,1031 v2(5079.93,1031) 5088.56,1022.37 U3.11@5212.79,1022.37 ; C20.1@4883.93,3233 4920.93,3196 v2(5079.93,3196) 5088.56,3187.37 U3.11@5212.79,3187.37 ; C6.1@5116.06,1287.13 v1(5162.93,1287.13) U3.100@5280.71,1287.13 ; C6.1@5116.06,3452.13 v1(5162.93,3452.13) U3.100@5280.71,3452.13 ; C19.1@5302.93,570 5320.08,587.15 U3.28@5320.08,678.87 ; C19.1@5302.93,2735 5320.08,2752.15 U3.28@5320.08,2843.87 ; U3.50@5753.15,678.87 5753.15,650.78 5767.93,636 5813.93,636 C16.2@5839.93,662 ; U3.50@5753.15,2843.87 5753.15,2815.78 5767.93,2801 5813.93,2801 C16.2@5839.93,2827
  Top Layer w24: R17.2@1007,842.71 966.71,842.71 944,820 944,718 985,677 R19.2@1007,677 1007,707 v1(1014.28,714.28) 1020,720 1096,720 1111,705 1111,561 L1.1@1155,517 ; R17.2@1007,3007.71 966.71,3007.71 944,2985 944,2883 985,2842 R19.2@1007,2842 1007,2872 v1(1014.28,2879.28) 1020,2885 1096,2885 1111,2870 1111,2726 L1.1@1155,2682 ; C18.1@1993,1368 C18.1@1995,1366 ; C18.1@1993,3533 C18.1@1995,3531 ; R17.2@4823.93,842.71 4783.64,842.71 4760.93,820 4760.93,718 4801.93,677 R19.2@4823.93,677 4823.93,707 v1(4831.21,714.28) 4836.93,720 4912.93,720 4927.93,705 4927.93,561 L1.1@4971.93,517 ; R17.2@4823.93,3007.71 4783.64,3007.71 4760.93,2985 4760.93,2883 4801.93,2842 R19.2@4823.93,2842 4823.93,2872 v1(4831.21,2879.28) 4836.93,2885 4912.93,2885 4927.93,2870 4927.93,2726 L1.1@4971.93,2682 ; C18.1@5809.93,1368 C18.1@5811.93,1366 ; C18.1@5809.93,3533 C18.1@5811.93,3531
  Top Layer w28: C18.1@1995,1366 v1(2048,1366) ; C18.1@1995,3531 v1(2048,3531) ; C18.1@5811.93,1366 v1(5864.93,1366) ; C18.1@5811.93,3531 v1(5864.93,3531)
  Top Layer w30: C21.1@1155,443 C21.1@1155,446 v1(1155,480) 1155,517 L1.1@1161,523 ; C21.1@1155,2608 C21.1@1155,2611 v1(1155,2645) 1155,2682 L1.1@1161,2688 ; v1(1451,570) C19.1@1486,570 ; v1(1451,2735) C19.1@1486,2735 ; v1(2021,691) 2023,689 C16.2@2023,662 ; v1(2021,2856) 2023,2854 C16.2@2023,2827 ; C21.1@4971.93,443 C21.1@4971.93,446 v1(4971.93,480) 4971.93,517 L1.1@4977.93,523 ; C21.1@4971.93,2608 C21.1@4971.93,2611 v1(4971.93,2645) 4971.93,2682 L1.1@4977.93,2688 ; v1(5267.93,570) C19.1@5302.93,570 ; v1(5267.93,2735) C19.1@5302.93,2735 ; v1(5837.93,691) 5839.93,689 C16.2@5839.93,662 ; v1(5837.93,2856) 5839.93,2854 C16.2@5839.93,2827
  Bottom Layer w12: v2(1263,1031) 1308,1031 1345,1068 ; v2(1263,3196) 1308,3196 1345,3233 ; v2(5079.93,1031) 5124.93,1031 5161.93,1068 ; v2(5079.93,3196) 5124.93,3196 5161.93,3233
  Bottom Layer w20: P4.2@2474,1531 2544,1531 2604,1471 2604,1407.94 P6.1@2706,1305.94 P6.2@2706,1205.94 ; P4.2@2474,3696 2544,3696 2604,3636 2604,3572.94 P6.1@2706,3470.94 P6.2@2706,3370.94 ; P4.2@6290.93,1531 6360.93,1531 6420.93,1471 6420.93,1407.94 P6.1@6522.93,1305.94 P6.2@6522.93,1205.94 ; P4.2@6290.93,3696 6360.93,3696 6420.93,3636 6420.93,3572.94 P6.1@6522.93,3470.94 P6.2@6522.93,3370.94
  Bottom Layer w28: v1(946,715) 1261,715 1345,799 1345,1068 1345,1291 1420,1366 v1(2048,1366) 2107,1366 2272,1531 P4.2@2474,1531 ; v1(946,2880) 1261,2880 1345,2964 1345,3233 1345,3456 1420,3531 v1(2048,3531) 2107,3531 2272,3696 P4.2@2474,3696 ; v1(4762.93,715) 5077.93,715 5161.93,799 5161.93,1068 5161.93,1291 5236.93,1366 v1(5864.93,1366) 5923.93,1366 6088.93,1531 P4.2@6290.93,1531 ; v1(4762.93,2880) 5077.93,2880 5161.93,2964 5161.93,3233 5161.93,3456 5236.93,3531 v1(5864.93,3531) 5923.93,3531 6088.93,3696 P4.2@6290.93,3696
  Bottom Layer w30: v1(1155,480) 1361,480 1439,558 v1@1449,568 ; v1(1155,2645) 1361,2645 1439,2723 v1@1449,2733 ; v1(1451,570) v1@1449,568 ; v1(1451,2735) v1@1449,2733 ; v1(2021,691) 1898,568 v1@1449,568 ; v1(2021,2856) 1898,2733 v1@1449,2733 ; v1(4971.93,480) 5177.93,480 5255.93,558 v1@5265.93,568 ; v1(4971.93,2645) 5177.93,2645 5255.93,2723 v1@5265.93,2733 ; v1(5267.93,570) v1@5265.93,568 ; v1(5267.93,2735) v1@5265.93,2733 ; v1(5837.93,691) 5714.93,568 v1@5265.93,568 ; v1(5837.93,2856) 5714.93,2733 v1@5265.93,2733
VCC_UART: C2.2 U1.5 | length 1280.4
  Top Layer w16: U1.5@850.17,1532.8 950,1532.8 972.8,1532.8 995,1555 1000,1560 C2.2@1000,1719 ; U1.5@850.17,3697.8 950,3697.8 972.8,3697.8 995,3720 1000,3725 C2.2@1000,3884 ; U1.5@4667.1,1532.8 4766.93,1532.8 4789.72,1532.8 4811.93,1555 4816.93,1560 C2.2@4816.93,1719 ; U1.5@4667.1,3697.8 4766.93,3697.8 4789.72,3697.8 4811.93,3720 4816.93,3725 C2.2@4816.93,3884
VDD: P2.2 P4.1 P5.1 R5.3 R12.2 | length 5761.9
  Top Layer w12: R5.3@2548,624 2646,624 P5.1@2655,615 ; R5.3@2548,2789 2646,2789 P5.1@2655,2780 ; R5.3@6364.93,624 6462.93,624 P5.1@6471.93,615 ; R5.3@6364.93,2789 6462.93,2789 P5.1@6471.93,2780
  Top Layer w20: v1(2626,769) R12.2@2660.7,769 ; v1(2626,2934) R12.2@2660.7,2934 ; v1(6442.93,769) R12.2@6477.63,769 ; v1(6442.93,2934) R12.2@6477.63,2934
  Top Layer w30: P4.1@2474,1631 2537,1631 2637,1531 P2.2@2706,1531 ; P4.1@2474,3796 2537,3796 2637,3696 P2.2@2706,3696 ; P4.1@6290.93,1631 6353.93,1631 6453.93,1531 P2.2@6522.93,1531 ; P4.1@6290.93,3796 6353.93,3796 6453.93,3696 P2.2@6522.93,3696
  Bottom Layer w20: P5.1@2655,615 2626,644 v1(2626,769) 2626,1003 2779,1156 2779,1458 P2.2@2706,1531 ; P5.1@2655,2780 2626,2809 v1(2626,2934) 2626,3168 2779,3321 2779,3623 P2.2@2706,3696 ; P5.1@6471.93,615 6442.93,644 v1(6442.93,769) 6442.93,1003 6595.93,1156 6595.93,1458 P2.2@6522.93,1531 ; P5.1@6471.93,2780 6442.93,2809 v1(6442.93,2934) 6442.93,3168 6595.93,3321 6595.93,3623 P2.2@6522.93,3696
VREF+: C22.1 L1.2 U3.21 | length 1851.2
  Top Layer w12: C22.1@1215,601 1256,601 1279,624 1279,795 1309.52,825.52 U3.21@1395.87,825.52 ; C22.1@1215,2766 1256,2766 1279,2789 1279,2960 1309.52,2990.52 U3.21@1395.87,2990.52 ; C22.1@5031.93,601 5072.93,601 5095.93,624 5095.93,795 5126.45,825.52 U3.21@5212.79,825.52 ; C22.1@5031.93,2766 5072.93,2766 5095.93,2789 5095.93,2960 5126.45,2990.52 U3.21@5212.79,2990.52
  Top Layer w24: C22.1@1215,601 1215,549 L1.2@1241,523 ; C22.1@1215,2766 1215,2714 L1.2@1241,2688 ; C22.1@5031.93,601 5031.93,549 L1.2@5057.93,523 ; C22.1@5031.93,2766 5031.93,2714 L1.2@5057.93,2688
VREF-: C22.2 L2.2 U3.20 | length 1612.1
  Top Layer w12: C22.2@1155,601 1236.86,682.86 L2.2@1238,682.86 1250,694.86 1250,799 1296.2,845.2 U3.20@1395.86,845.2 ; C22.2@1155,2766 1236.86,2847.86 L2.2@1238,2847.86 1250,2859.86 1250,2964 1296.2,3010.2 U3.20@1395.86,3010.2 ; C22.2@4971.93,601 5053.79,682.86 L2.2@5054.93,682.86 5066.93,694.86 5066.93,799 5113.13,845.2 U3.20@5212.79,845.2 ; C22.2@4971.93,2766 5053.79,2847.86 L2.2@5054.93,2847.86 5066.93,2859.86 5066.93,2964 5113.13,3010.2 U3.20@5212.79,3010.2
pads on no net: J3.3 J3.5 J3.11 J3.13 J3.17 U1.1 U1.2 U1.11 U1.12 U1.13 U1.14 U1.15 U1.16 U1.17 U1.18 U1.20 U2.4 U3.73

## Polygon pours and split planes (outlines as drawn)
GND on Top Layer "Top Layer-No Net" (solid, pour order 1000): 5131.93,2796 5131.93,2744.1 5131.18,2743.35 5143.93,2730.61 5143.93,2716 5143.93,2706 5133.93,2696 5142.93,2687 5142.93,2587.24 5164.16,2587.24 5166.93,2590 5167.93,2591 5167.93,2602 5167.93,2792 5163.93,2796 5158.93,2801 5145.93,2801 5136.93,2801 5131.93,2796
GND on Top Layer "Top Layer-No Net" (solid, remove dead copper, pour order 1000): 3816.93,4330 3816.93,2165 7436.93,2165 7436.93,4330
GND on Top Layer "Top Layer-No Net" (solid, pour order 1000): 1315,2796 1315,2744.1 1314.25,2743.35 1327,2730.61 1327,2716 1327,2706 1317,2696 1326,2687 1326,2587.24 1347.24,2587.24 1350,2590 1351,2591 1351,2602 1351,2792 1347,2796 1342,2801 1329,2801 1320,2801 1315,2796
GND on Top Layer "Top Layer-No Net" (solid, remove dead copper, pour order 1000): 0,4330 0,2165 3620,2165 3620,4330
GND on Top Layer "Top Layer-No Net" (solid, pour order 1000): 5131.93,631 5131.93,579.1 5131.18,578.35 5143.93,565.61 5143.93,551 5143.93,541 5133.93,531 5142.93,522 5142.93,422.24 5164.16,422.24 5166.93,425 5167.93,426 5167.93,437 5167.93,627 5163.93,631 5158.93,636 5145.93,636 5136.93,636 5131.93,631
GND on Top Layer "Top Layer-No Net" (solid, remove dead copper, pour order 1000): 3816.93,2165 3816.93,0 7436.93,0 7436.93,2165
GND on Top Layer "Top Layer-No Net" (solid, pour order 1000): 1315,631 1315,579.1 1314.25,578.35 1327,565.61 1327,551 1327,541 1317,531 1326,522 1326,422.24 1347.24,422.24 1350,425 1351,426 1351,437 1351,627 1347,631 1342,636 1329,636 1320,636 1315,631
GND on Top Layer "Top Layer-No Net" (solid, remove dead copper, pour order 1000): 0,2165 0,0 3620,0 3620,2165
GND on Bottom Layer "Top Layer-No Net" (solid, remove dead copper, pour order 1001): 3816.93,4330 3816.93,2165 7436.93,2165 7436.93,4330
GND on Bottom Layer "Top Layer-No Net" (solid, remove dead copper, pour order 1001): 0,4330 0,2165 3620,2165 3620,4330
GND on Bottom Layer "Top Layer-No Net" (solid, remove dead copper, pour order 1001): 3816.93,2165 3816.93,0 7436.93,0 7436.93,2165
GND on Bottom Layer "Top Layer-No Net" (solid, remove dead copper, pour order 1001): 0,2165 0,0 3620,0 3620,2165

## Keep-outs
Keep-Out Layer:
  lines w5: 0,66 ccw(c66.03,65.55) 66,-0.48 ; 0,2231 ccw(c66.03,2230.55) 66,2164.52 ; 0.52,2098.5 cw(c66.55,2098.48) 67,2164.5 ; 0.52,4263.5 cw(c66.55,4263.48) 67,4329.5 ; 3553,0 ccw(c3553.45,66.03) 3619.48,66 ; 3553,2165 ccw(c3553.45,2231.03) 3619.48,2231 ; 3554,2165 cw(c3553.97,2098.97) 3620,2098.52 ; 3554,4330 cw(c3553.97,4263.97) 3620,4263.52 ; 3816.93,66 ccw(c3882.95,65.55) 3882.93,-0.48 ; 3816.93,2231 ccw(c3882.95,2230.55) 3882.93,2164.52 ; 3817.45,2098.5 cw(c3883.48,2098.48) 3883.93,2164.5 ; 3817.45,4263.5 cw(c3883.48,4263.48) 3883.93,4329.5 ; 7369.93,0 ccw(c7370.38,66.03) 7436.41,66 ; 7369.93,2165 ccw(c7370.38,2231.03) 7436.41,2231 ; 7370.93,2165 cw(c7370.9,2098.97) 7436.93,2098.52 ; 7370.93,4330 cw(c7370.9,4263.97) 7436.93,4263.52 ; 0,2165 3620,2165 ; 0,2165 0,4330 3620,4330 3620,2165 ; 0,2165 3620,2165 ; 0,2165 0,0 3620,0 3620,2165 ; 3816.93,2165 7436.93,2165 ; 3816.93,2165 3816.93,4330 7436.93,4330 7436.93,2165 ; 3816.93,2165 7436.93,2165 ; 3816.93,2165 3816.93,0 7436.93,0 7436.93,2165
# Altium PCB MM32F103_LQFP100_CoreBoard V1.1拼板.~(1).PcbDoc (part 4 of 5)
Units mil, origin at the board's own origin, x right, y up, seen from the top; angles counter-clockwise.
Board outline 7436.93 x 4329.96 mil, 2 copper layers (Top Layer, Bottom Layer); 260 components, 116 nets, 1796 pads, 448 vias.

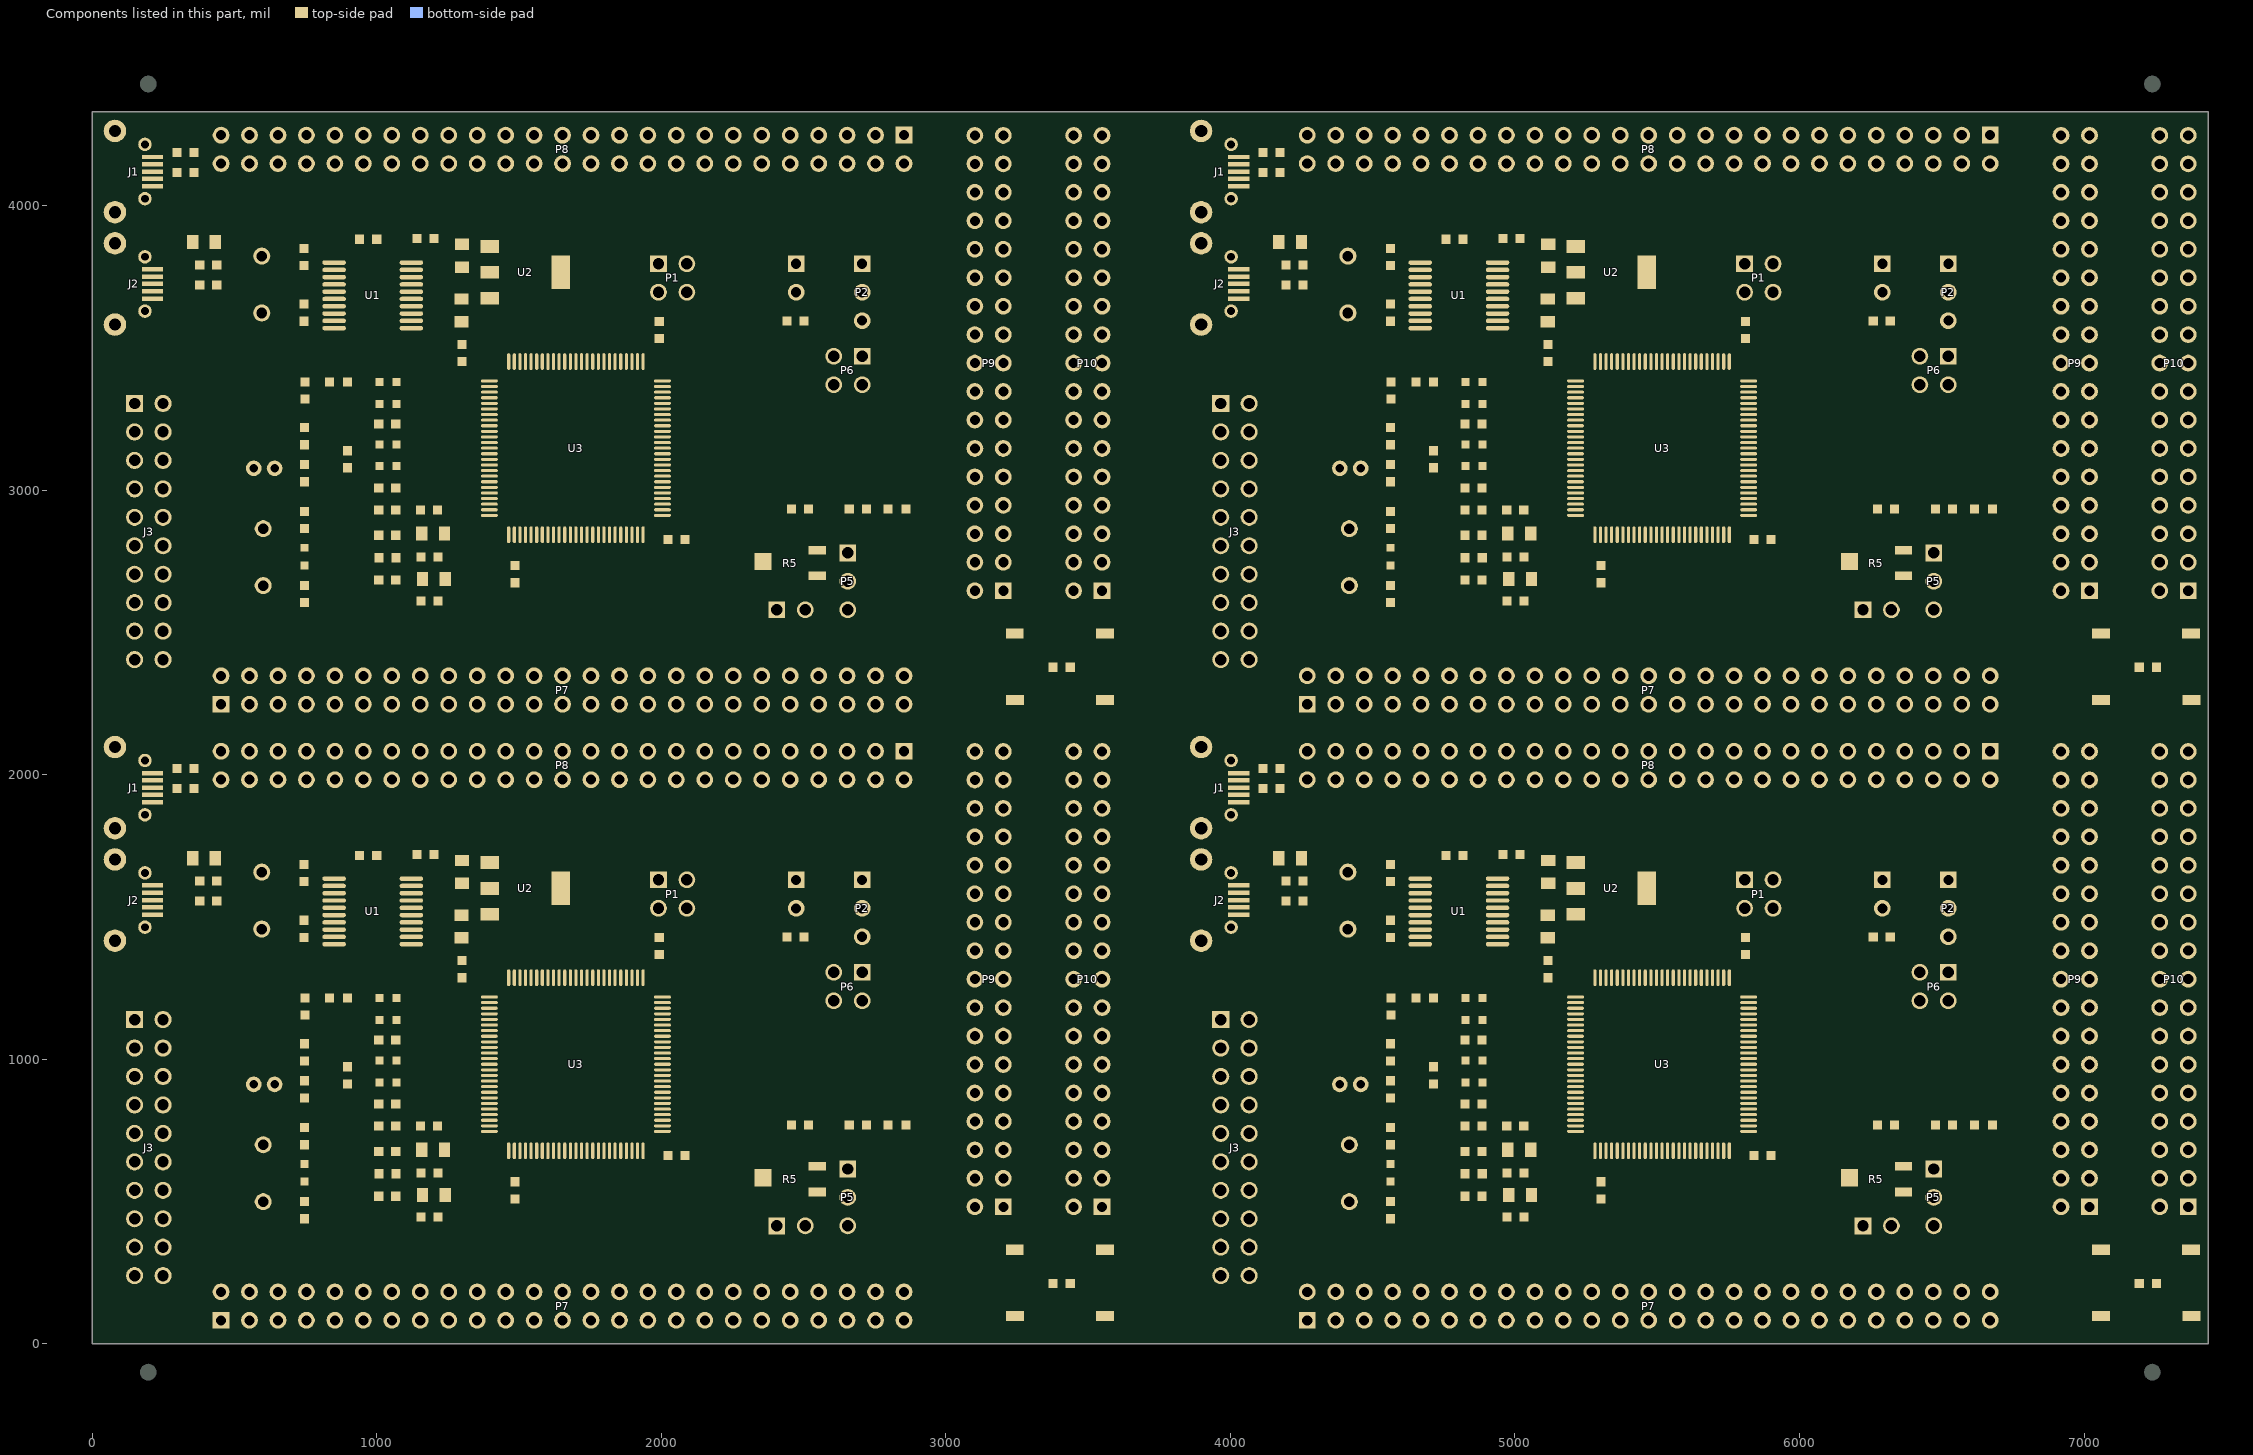
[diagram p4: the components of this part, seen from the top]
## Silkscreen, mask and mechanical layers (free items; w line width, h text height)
Top Overlay:
  lines w8: 403,233 403,349 402,350 2902,350 2903,349 2903,233 ; 403,1933 403,1814 2903,1814 2903,1933 ; 403,2398 403,2514 402,2515 2902,2515 2903,2514 2903,2398 ; 403,4098 403,3979 2903,3979 2903,4098 ; 1700,1481 1940,1481 ; 1700,1681 1940,1681 ; 1700,3646 1940,3646 ; 1700,3846 1940,3846 ; 1701,1481 1701,1681 ; 1701,3646 1701,3846 ; 2424,1481 2166,1481 2166,1681 2424,1681 ; 2424,3646 2166,3646 2166,3846 2424,3846 ; 2562,1156 2112,1156 2112,1356 2562,1356 ; 2562,3321 2112,3321 2112,3521 2562,3521 ; 2656,1381 2550,1381 2550,1681 2656,1681 ; 2656,3546 2550,3546 2550,3846 2656,3846 ; 2706,365 2901,365 2901,665 2706,665 ; 2706,2530 2901,2530 2901,2830 2706,2830 ; 3052,432 2934,432 2934,2132 3052,2132 ; 3052,2597 2934,2597 2934,4297 3052,4297 ; 3399,432 3281,432 3281,2132 3405,2132 ; 3399,2597 3281,2597 3281,4297 3405,4297 ; 4219.93,233 4219.93,349 4218.93,350 6718.93,350 6719.93,349 6719.93,233 ; 4219.93,1933 4219.93,1814 6719.93,1814 6719.93,1933 ; 4219.93,2398 4219.93,2514 4218.93,2515 6718.93,2515 6719.93,2514 6719.93,2398 ; 4219.93,4098 4219.93,3979 6719.93,3979 6719.93,4098 ; 5516.93,1481 5756.93,1481 ; 5516.93,1681 5756.93,1681 ; 5516.93,3646 5756.93,3646 ; 5516.93,3846 5756.93,3846 ; 5517.93,1481 5517.93,1681 ; 5517.93,3646 5517.93,3846 ; 6240.93,1481 5982.93,1481 5982.93,1681 6240.93,1681 ; 6240.93,3646 5982.93,3646 5982.93,3846 6240.93,3846 ; 6378.93,1156 5928.93,1156 5928.93,1356 6378.93,1356 ; 6378.93,3321 5928.93,3321 5928.93,3521 6378.93,3521 ; 6472.93,1381 6366.93,1381 6366.93,1681 6472.93,1681 ; 6472.93,3546 6366.93,3546 6366.93,3846 6472.93,3846 ; 6522.93,365 6717.93,365 6717.93,665 6522.93,665 ; 6522.93,2530 6717.93,2530 6717.93,2830 6522.93,2830 ; 6868.93,432 6750.93,432 6750.93,2132 6868.93,2132 ; 6868.93,2597 6750.93,2597 6750.93,4297 6868.93,4297 ; 7215.93,432 7097.93,432 7097.93,2132 7221.93,2132 ; 7215.93,2597 7097.93,2597 7097.93,4297 7221.93,4297
  text "A10" at 2986,4204 h35 r90
  text "A10" at 3035,4204 h35 r90
  text "A10" at 6802.93,4204 h35 r90
  text "A10" at 6851.93,4204 h35 r90
  text "3V3" at 3335,4200 h35 r90
  text "3V3" at 3384,4200 h35 r90
  text "3V3" at 7151.93,4200 h35 r90
  text "3V3" at 7200.93,4200 h35 r90
  text "A9" at 2986,4117 h35 r90
  text "A9" at 3035,4117 h35 r90
  text "A9" at 6802.93,4117 h35 r90
  text "A9" at 6851.93,4117 h35 r90
  text "5V" at 3335,4116 h35 r90
  text "5V" at 3384,4116 h35 r90
  text "5V" at 7151.93,4116 h35 r90
  text "5V" at 7200.93,4116 h35 r90
  text "E1" at 437,4046 h35
  text "E0" at 529,4046 h35
  text "B9" at 632,4046 h35
  text "B8" at 729,4046 h35
  text "B7" at 834,4046 h35
  text "B6" at 934,4046 h35
  text "B5" at 1029,4046 h35
  text "B4" at 1129,4046 h35
  text "B3" at 1227,4046 h35
  text "D7" at 1326,4046 h35
  text "D6" at 1426,4046 h35
  text "D5" at 1527,4046 h35
  text "D4" at 1628,4046 h35
  text "D3" at 1727,4046 h35
  text "D2" at 1827,4046 h35
  text "D1" at 1933,4046 h35
  text "D0" at 2024,4046 h35
  text "C12" at 2110,4046 h35
  text "C11" at 2216,4046 h35
  text "C10" at 2313,4046 h35
  text "A15" at 2416,4046 h35
  text "A14" at 2514,4046 h35
  text "A13" at 2614,4046 h35
  text "A12" at 2716,4046 h35
  text "A11" at 2817,4046 h35
  text "E1" at 4253.93,4046 h35
  text "E0" at 4345.93,4046 h35
  text "B9" at 4448.93,4046 h35
  text "B8" at 4545.93,4046 h35
  text "B7" at 4650.93,4046 h35
  text "B6" at 4750.93,4046 h35
  text "B5" at 4845.93,4046 h35
  text "B4" at 4945.93,4046 h35
  text "B3" at 5043.93,4046 h35
  text "D7" at 5142.93,4046 h35
  text "D6" at 5242.93,4046 h35
  text "D5" at 5343.93,4046 h35
  text "D4" at 5444.93,4046 h35
  text "D3" at 5543.93,4046 h35
  text "D2" at 5643.93,4046 h35
  text "D1" at 5749.93,4046 h35
  text "D0" at 5840.93,4046 h35
  text "C12" at 5926.93,4046 h35
  text "C11" at 6032.93,4046 h35
  text "C10" at 6129.93,4046 h35
  text "A15" at 6232.93,4046 h35
  text "A14" at 6330.93,4046 h35
  text "A13" at 6430.93,4046 h35
  text "A12" at 6532.93,4046 h35
  text "A11" at 6633.93,4046 h35
  text "A8" at 2986,4020 h35 r90
  text "A8" at 3035,4020 h35 r90
  text "A8" at 6802.93,4020 h35 r90
  text "A8" at 6851.93,4020 h35 r90
  text "C8" at 3335,4019 h35 r90
  text "C8" at 3384,4019 h35 r90
  text "C8" at 7151.93,4019 h35 r90
  text "C8" at 7200.93,4019 h35 r90
  text "E1" at 437,3997 h35
  text "E0" at 529,3997 h35
  text "B9" at 632,3997 h35
  text "B8" at 729,3997 h35
  text "B7" at 834,3997 h35
  text "B6" at 934,3997 h35
  text "B5" at 1029,3997 h35
  text "B4" at 1129,3997 h35
  text "B3" at 1227,3997 h35
  text "D7" at 1326,3997 h35
  text "D6" at 1426,3997 h35
  text "D5" at 1527,3997 h35
  text "D4" at 1628,3997 h35
  text "D3" at 1727,3997 h35
  text "D2" at 1827,3997 h35
  text "D1" at 1933,3997 h35
  text "D0" at 2024,3997 h35
  text "C12" at 2110,3997 h35
  text "C11" at 2216,3997 h35
  text "C10" at 2313,3997 h35
  text "A15" at 2416,3997 h35
  text "A14" at 2514,3997 h35
  text "A13" at 2614,3997 h35
  text "A12" at 2716,3997 h35
  text "A11" at 2817,3997 h35
  text "E1" at 4253.93,3997 h35
  text "E0" at 4345.93,3997 h35
  text "B9" at 4448.93,3997 h35
  text "B8" at 4545.93,3997 h35
  text "B7" at 4650.93,3997 h35
  text "B6" at 4750.93,3997 h35
  text "B5" at 4845.93,3997 h35
  text "B4" at 4945.93,3997 h35
  text "B3" at 5043.93,3997 h35
  text "D7" at 5142.93,3997 h35
  text "D6" at 5242.93,3997 h35
  text "D5" at 5343.93,3997 h35
  text "D4" at 5444.93,3997 h35
  text "D3" at 5543.93,3997 h35
  text "D2" at 5643.93,3997 h35
  text "D1" at 5749.93,3997 h35
  text "D0" at 5840.93,3997 h35
  text "C12" at 5926.93,3997 h35
  text "C11" at 6032.93,3997 h35
  text "C10" at 6129.93,3997 h35
  text "A15" at 6232.93,3997 h35
  text "A14" at 6330.93,3997 h35
  text "A13" at 6430.93,3997 h35
  text "A12" at 6532.93,3997 h35
  text "A11" at 6633.93,3997 h35
  text "USB" at 225,3965 h80
  text "USB" at 4041.93,3965 h80
  text "C9" at 2986,3916 h35 r90
  text "C9" at 3035,3916 h35 r90
  text "C9" at 6802.93,3916 h35 r90
  text "C9" at 6851.93,3916 h35 r90
  text "C6" at 3335,3915 h35 r90
  text "C6" at 3384,3915 h35 r90
  text "C6" at 7151.93,3915 h35 r90
  text "C6" at 7200.93,3915 h35 r90
  text "C7" at 2986,3819 h35 r90
  text "C7" at 3035,3819 h35 r90
  text "C7" at 6802.93,3819 h35 r90
  text "C7" at 6851.93,3819 h35 r90
  text "D14" at 3335,3810 h35 r90
  text "D14" at 3384,3810 h35 r90
  text "D14" at 7151.93,3810 h35 r90
  text "D14" at 7200.93,3810 h35 r90
  text "A10" at 1841,3780 h35
  text "A10" at 5657.93,3780 h35
  text "RXD" at 1716,3779 h35
  text "RXD" at 5532.93,3779 h35
  text "VDD" at 2312,3776 h35
  text "VDD" at 6128.93,3776 h35
  text "5V" at 2585,3775 h35
  text "5V" at 6401.93,3775 h35
  text "D15" at 2986,3713 h35 r90
  text "D15" at 3035,3713 h35 r90
  text "D15" at 6802.93,3713 h35 r90
  text "D15" at 6851.93,3713 h35 r90
  text "D12" at 3335,3707 h35 r90
  text "D12" at 3384,3707 h35 r90
  text "D12" at 7151.93,3707 h35 r90
  text "D12" at 7200.93,3707 h35 r90
  text "VCC_MCU" at 2180,3679 h35
  text "VCC_MCU" at 5996.93,3679 h35
  text "A9" at 1861,3678 h35
  text "A9" at 5677.93,3678 h35
  text "TXD" at 1716,3677 h35
  text "TXD" at 5532.93,3677 h35
  text "VDD" at 2560,3675 h35
  text "VDD" at 6376.93,3675 h35
  text "D13" at 2986,3613 h35 r90
  text "D13" at 3035,3613 h35 r90
  text "D13" at 6802.93,3613 h35 r90
  text "D13" at 6851.93,3613 h35 r90
  text "D10" at 3335,3606 h35 r90
  text "D10" at 3384,3606 h35 r90
  text "D10" at 7151.93,3606 h35 r90
  text "D10" at 7200.93,3606 h35 r90
  text "UART" at 225,3570 h80
  text "3V3" at 2560,3570 h35
  text "UART" at 4041.93,3570 h80
  text "3V3" at 6376.93,3570 h35
  text "D8" at 3335,3519 h35 r90
  text "D8" at 3384,3519 h35 r90
  text "D8" at 7151.93,3519 h35 r90
  text "D8" at 7200.93,3519 h35 r90
  text "D11" at 2986,3508 h35 r90
  text "D11" at 3035,3508 h35 r90
  text "D11" at 6802.93,3508 h35 r90
  text "D11" at 6851.93,3508 h35 r90
  text "BOOT0" at 2124,3450 h35
  text "VCC_MCU" at 2315,3450 h35
  text "BOOT0" at 5940.93,3450 h35
  text "VCC_MCU" at 6131.93,3450 h35
  text "D9" at 2986,3415 h35 r90
  text "D9" at 3035,3415 h35 r90
  text "D9" at 6802.93,3415 h35 r90
  text "D9" at 6851.93,3415 h35 r90
  text "B14" at 3335,3410 h35 r90
  text "B14" at 3384,3410 h35 r90
  text "B14" at 7151.93,3410 h35 r90
  text "B14" at 7200.93,3410 h35 r90
  text "VCC_MCU" at 2317,3353 h35
  text "VCC_MCU" at 6133.93,3353 h35
  text "VBAT" at 2127,3341.34 h35
  text "VBAT" at 5943.93,3341.34 h35
  text "B15" at 2986,3308 h35 r90
  text "B15" at 3035,3308 h35 r90
  text "B15" at 6802.93,3308 h35 r90
  text "B15" at 6851.93,3308 h35 r90
  text "B12" at 3335,3304 h35 r90
  text "B12" at 3384,3304 h35 r90
  text "B12" at 7151.93,3304 h35 r90
  text "B12" at 7200.93,3304 h35 r90
  text "POWER" at 799,3295 h35
  text "POWER" at 4615.93,3295 h35
  text "B13" at 2986,3207 h35 r90
  text "B13" at 3035,3207 h35 r90
  text "B13" at 6802.93,3207 h35 r90
  text "B13" at 6851.93,3207 h35 r90
  text "B10" at 3335,3206 h35 r90
  text "B10" at 3384,3206 h35 r90
  text "B10" at 7151.93,3206 h35 r90
  text "B10" at 7200.93,3206 h35 r90
  text "B11" at 2986,3110 h35 r90
  text "B11" at 3035,3110 h35 r90
  text "B11" at 6802.93,3110 h35 r90
  text "B11" at 6851.93,3110 h35 r90
  text "E14" at 3335,3104 h35 r90
  text "E14" at 3384,3104 h35 r90
  text "E14" at 7151.93,3104 h35 r90
  text "E14" at 7200.93,3104 h35 r90
  text "E15" at 2986,3009 h35 r90
  text "E15" at 3035,3009 h35 r90
  text "E15" at 6802.93,3009 h35 r90
  text "E15" at 6851.93,3009 h35 r90
  text "E12" at 3335,3004 h35 r90
  text "E12" at 3384,3004 h35 r90
  text "E12" at 7151.93,3004 h35 r90
  text "E12" at 7200.93,3004 h35 r90
  text "LD" at 2807,2968 h35
  text "LD" at 6623.93,2968 h35
  text "E13" at 2986,2906 h35 r90
  text "E13" at 3035,2906 h35 r90
  text "E13" at 6802.93,2906 h35 r90
  text "E13" at 6851.93,2906 h35 r90
  text "E10" at 3335,2905 h35 r90
  text "E10" at 3384,2905 h35 r90
  text "E10" at 7151.93,2905 h35 r90
  text "E10" at 7200.93,2905 h35 r90
  text "E8" at 3335,2822 h35 r90
  text "E8" at 3384,2822 h35 r90
  text "E8" at 7151.93,2822 h35 r90
  text "E8" at 7200.93,2822 h35 r90
  text "E11" at 2986,2816 h35 r90
  text "E11" at 3035,2816 h35 r90
  text "E11" at 6802.93,2816 h35 r90
  text "E11" at 6851.93,2816 h35 r90
  text "PUL_UP" at 2716,2760 h35
  text "PUL_UP" at 6532.93,2760 h35
  text "E9" at 2986,2716 h35 r90
  text "E9" at 3035,2716 h35 r90
  text "E9" at 6802.93,2716 h35 r90
  text "E9" at 6851.93,2716 h35 r90
  text "LD-" at 3335,2712 h35 r90
  text "GND" at 3384,2712 h35 r90
  text "LD-" at 7151.93,2712 h35 r90
  text "GND" at 7200.93,2712 h35 r90
  text "WKUP" at 2716,2660 h35
  text "WKUP" at 6532.93,2660 h35
  text "E7" at 2986,2618 h35 r90
  text "E7" at 3035,2618 h35 r90
  text "E7" at 6802.93,2618 h35 r90
  text "E7" at 6851.93,2618 h35 r90
  text "GND" at 3335,2605 h35 r90
  text "GND" at 3384,2605 h35 r90
  text "GND" at 7151.93,2605 h35 r90
  text "GND" at 7200.93,2605 h35 r90
  text "PUL_DN" at 2716,2560 h35
  text "PUL_DN" at 6532.93,2560 h35
  text "ADC" at 2193,2550 h80
  text "ADC" at 6009.93,2550 h80
  text "E2" at 430,2464 h35
  text "E3" at 525,2464 h35
  text "E4" at 625,2464 h35
  text "E5" at 725,2464 h35
  text "E6" at 830,2464 h35
  text "C13" at 910,2464 h35
  text "C14" at 1011,2464 h35
  text "C15" at 1111,2464 h35
  text "C0" at 1223,2464 h35
  text "C1" at 1325,2464 h35
  text "C2" at 1421,2464 h35
  text "C3" at 1519,2464 h35
  text "A0" at 1619,2464 h35
  text "A1" at 1726,2464 h35
  text "A2" at 1818,2464 h35
  text "A3" at 1918,2464 h35
  text "A4" at 2021,2464 h35
  text "A5" at 2119,2464 h35
  text "A6" at 2223,2464 h35
  text "A7" at 2322,2464 h35
  text "C4" at 2424,2464 h35
  text "C5" at 2521,2464 h35
  text "B0" at 2625,2464 h35
  text "B1" at 2728,2464 h35
  text "B2" at 2822,2464 h35
  text "E2" at 4246.93,2464 h35
  text "E3" at 4341.93,2464 h35
  text "E4" at 4441.93,2464 h35
  text "E5" at 4541.93,2464 h35
  text "E6" at 4646.93,2464 h35
  text "C13" at 4726.93,2464 h35
  text "C14" at 4827.93,2464 h35
  text "C15" at 4927.93,2464 h35
  text "C0" at 5039.93,2464 h35
  text "C1" at 5141.93,2464 h35
  text "C2" at 5237.93,2464 h35
  text "C3" at 5335.93,2464 h35
  text "A0" at 5435.93,2464 h35
  text "A1" at 5542.93,2464 h35
  text "A2" at 5634.93,2464 h35
  text "A3" at 5734.93,2464 h35
  text "A4" at 5837.93,2464 h35
  text "A5" at 5935.93,2464 h35
  text "A6" at 6039.93,2464 h35
  text "A7" at 6138.93,2464 h35
  text "C4" at 6240.93,2464 h35
  text "C5" at 6337.93,2464 h35
  text "B0" at 6441.93,2464 h35
  text "B1" at 6544.93,2464 h35
  text "B2" at 6638.93,2464 h35
  text "RESET" at 2959,2457 h80
  text "RESET" at 6775.93,2457 h80
  text "E2" at 430,2415 h35
  text "E3" at 525,2415 h35
  text "E4" at 625,2415 h35
  text "E5" at 725,2415 h35
  text "E6" at 830,2415 h35
  text "C13" at 910,2415 h35
  text "C14" at 1011,2415 h35
  text "C15" at 1111,2415 h35
  text "C0" at 1223,2415 h35
  text "C1" at 1325,2415 h35
  text "C2" at 1421,2415 h35
  text "C3" at 1519,2415 h35
  text "A0" at 1619,2415 h35
  text "A1" at 1726,2415 h35
  text "A2" at 1818,2415 h35
  text "A3" at 1918,2415 h35
  text "A4" at 2021,2415 h35
  text "A5" at 2119,2415 h35
  text "A6" at 2223,2415 h35
  text "A7" at 2322,2415 h35
  text "C4" at 2424,2415 h35
  text "C5" at 2521,2415 h35
  text "B0" at 2625,2415 h35
  text "B1" at 2728,2415 h35
  text "B2" at 2822,2415 h35
  text "E2" at 4246.93,2415 h35
  text "E3" at 4341.93,2415 h35
  text "E4" at 4441.93,2415 h35
  text "E5" at 4541.93,2415 h35
  text "E6" at 4646.93,2415 h35
  text "C13" at 4726.93,2415 h35
  text "C14" at 4827.93,2415 h35
  text "C15" at 4927.93,2415 h35
  text "C0" at 5039.93,2415 h35
  text "C1" at 5141.93,2415 h35
  text "C2" at 5237.93,2415 h35
  text "C3" at 5335.93,2415 h35
  text "A0" at 5435.93,2415 h35
  text "A1" at 5542.93,2415 h35
  text "A2" at 5634.93,2415 h35
  text "A3" at 5734.93,2415 h35
  text "A4" at 5837.93,2415 h35
  text "A5" at 5935.93,2415 h35
  text "A6" at 6039.93,2415 h35
  text "A7" at 6138.93,2415 h35
  text "C4" at 6240.93,2415 h35
  text "C5" at 6337.93,2415 h35
  text "B0" at 6441.93,2415 h35
  text "B1" at 6544.93,2415 h35
  text "B2" at 6638.93,2415 h35
  text "WKUP" at 2959,2242 h80
  text "WKUP" at 6775.93,2242 h80
  text "A10" at 2986,2039 h35 r90
  text "A10" at 3035,2039 h35 r90
  text "A10" at 6802.93,2039 h35 r90
  text "A10" at 6851.93,2039 h35 r90
  text "3V3" at 3335,2035 h35 r90
  text "3V3" at 3384,2035 h35 r90
  text "3V3" at 7151.93,2035 h35 r90
  text "3V3" at 7200.93,2035 h35 r90
  text "A9" at 2986,1952 h35 r90
  text "A9" at 3035,1952 h35 r90
  text "A9" at 6802.93,1952 h35 r90
  text "A9" at 6851.93,1952 h35 r90
  text "5V" at 3335,1951 h35 r90
  text "5V" at 3384,1951 h35 r90
  text "5V" at 7151.93,1951 h35 r90
  text "5V" at 7200.93,1951 h35 r90
  text "E1" at 437,1881 h35
  text "E0" at 529,1881 h35
  text "B9" at 632,1881 h35
  text "B8" at 729,1881 h35
  text "B7" at 834,1881 h35
  text "B6" at 934,1881 h35
  text "B5" at 1029,1881 h35
  text "B4" at 1129,1881 h35
  text "B3" at 1227,1881 h35
  text "D7" at 1326,1881 h35
  text "D6" at 1426,1881 h35
  text "D5" at 1527,1881 h35
  text "D4" at 1628,1881 h35
  text "D3" at 1727,1881 h35
  text "D2" at 1827,1881 h35
  text "D1" at 1933,1881 h35
  text "D0" at 2024,1881 h35
  text "C12" at 2110,1881 h35
  text "C11" at 2216,1881 h35
  text "C10" at 2313,1881 h35
  text "A15" at 2416,1881 h35
  text "A14" at 2514,1881 h35
  text "A13" at 2614,1881 h35
  text "A12" at 2716,1881 h35
  text "A11" at 2817,1881 h35
  text "E1" at 4253.93,1881 h35
  text "E0" at 4345.93,1881 h35
  text "B9" at 4448.93,1881 h35
  text "B8" at 4545.93,1881 h35
  text "B7" at 4650.93,1881 h35
  text "B6" at 4750.93,1881 h35
  text "B5" at 4845.93,1881 h35
  text "B4" at 4945.93,1881 h35
  text "B3" at 5043.93,1881 h35
  text "D7" at 5142.93,1881 h35
  text "D6" at 5242.93,1881 h35
  text "D5" at 5343.93,1881 h35
  text "D4" at 5444.93,1881 h35
  text "D3" at 5543.93,1881 h35
  text "D2" at 5643.93,1881 h35
  text "D1" at 5749.93,1881 h35
  text "D0" at 5840.93,1881 h35
  text "C12" at 5926.93,1881 h35
  text "C11" at 6032.93,1881 h35
  text "C10" at 6129.93,1881 h35
  text "A15" at 6232.93,1881 h35
  text "A14" at 6330.93,1881 h35
  text "A13" at 6430.93,1881 h35
  text "A12" at 6532.93,1881 h35
  text "A11" at 6633.93,1881 h35
  text "A8" at 2986,1855 h35 r90
  text "A8" at 3035,1855 h35 r90
  text "A8" at 6802.93,1855 h35 r90
  text "A8" at 6851.93,1855 h35 r90
  text "C8" at 3335,1854 h35 r90
  text "C8" at 3384,1854 h35 r90
  text "C8" at 7151.93,1854 h35 r90
  text "C8" at 7200.93,1854 h35 r90
  text "E1" at 437,1832 h35
  text "E0" at 529,1832 h35
  text "B9" at 632,1832 h35
  text "B8" at 729,1832 h35
  text "B7" at 834,1832 h35
  text "B6" at 934,1832 h35
  text "B5" at 1029,1832 h35
  text "B4" at 1129,1832 h35
  text "B3" at 1227,1832 h35
  text "D7" at 1326,1832 h35
  text "D6" at 1426,1832 h35
  text "D5" at 1527,1832 h35
  text "D4" at 1628,1832 h35
  text "D3" at 1727,1832 h35
  text "D2" at 1827,1832 h35
  text "D1" at 1933,1832 h35
  text "D0" at 2024,1832 h35
  text "C12" at 2110,1832 h35
  text "C11" at 2216,1832 h35
  text "C10" at 2313,1832 h35
  text "A15" at 2416,1832 h35
  text "A14" at 2514,1832 h35
  text "A13" at 2614,1832 h35
  text "A12" at 2716,1832 h35
  text "A11" at 2817,1832 h35
  text "E1" at 4253.93,1832 h35
  text "E0" at 4345.93,1832 h35
  text "B9" at 4448.93,1832 h35
  text "B8" at 4545.93,1832 h35
  text "B7" at 4650.93,1832 h35
  text "B6" at 4750.93,1832 h35
  text "B5" at 4845.93,1832 h35
  text "B4" at 4945.93,1832 h35
  text "B3" at 5043.93,1832 h35
  text "D7" at 5142.93,1832 h35
  text "D6" at 5242.93,1832 h35
  text "D5" at 5343.93,1832 h35
  text "D4" at 5444.93,1832 h35
  text "D3" at 5543.93,1832 h35
  text "D2" at 5643.93,1832 h35
  text "D1" at 5749.93,1832 h35
  text "D0" at 5840.93,1832 h35
  text "C12" at 5926.93,1832 h35
  text "C11" at 6032.93,1832 h35
  text "C10" at 6129.93,1832 h35
  text "A15" at 6232.93,1832 h35
  text "A14" at 6330.93,1832 h35
  text "A13" at 6430.93,1832 h35
  text "A12" at 6532.93,1832 h35
  text "A11" at 6633.93,1832 h35
  text "USB" at 225,1800 h80
  text "USB" at 4041.93,1800 h80
  text "C9" at 2986,1751 h35 r90
  text "C9" at 3035,1751 h35 r90
  text "C9" at 6802.93,1751 h35 r90
  text "C9" at 6851.93,1751 h35 r90
  text "C6" at 3335,1750 h35 r90
  text "C6" at 3384,1750 h35 r90
  text "C6" at 7151.93,1750 h35 r90
  text "C6" at 7200.93,1750 h35 r90
  text "C7" at 2986,1654 h35 r90
  text "C7" at 3035,1654 h35 r90
  text "C7" at 6802.93,1654 h35 r90
  text "C7" at 6851.93,1654 h35 r90
  text "D14" at 3335,1645 h35 r90
  text "D14" at 3384,1645 h35 r90
  text "D14" at 7151.93,1645 h35 r90
  text "D14" at 7200.93,1645 h35 r90
  text "A10" at 1841,1615 h35
  text "A10" at 5657.93,1615 h35
  text "RXD" at 1716,1614 h35
  text "RXD" at 5532.93,1614 h35
  text "VDD" at 2312,1611 h35
  text "VDD" at 6128.93,1611 h35
  text "5V" at 2585,1610 h35
  text "5V" at 6401.93,1610 h35
  text "D15" at 2986,1548 h35 r90
  text "D15" at 3035,1548 h35 r90
  text "D15" at 6802.93,1548 h35 r90
  text "D15" at 6851.93,1548 h35 r90
  text "D12" at 3335,1542 h35 r90
  text "D12" at 3384,1542 h35 r90
  text "D12" at 7151.93,1542 h35 r90
  text "D12" at 7200.93,1542 h35 r90
  text "VCC_MCU" at 2180,1514 h35
  text "VCC_MCU" at 5996.93,1514 h35
  text "A9" at 1861,1513 h35
  text "A9" at 5677.93,1513 h35
  text "TXD" at 1716,1512 h35
  text "TXD" at 5532.93,1512 h35
  text "VDD" at 2560,1510 h35
  text "VDD" at 6376.93,1510 h35
  text "D13" at 2986,1448 h35 r90
  text "D13" at 3035,1448 h35 r90
  text "D13" at 6802.93,1448 h35 r90
  text "D13" at 6851.93,1448 h35 r90
  text "D10" at 3335,1441 h35 r90
  text "D10" at 3384,1441 h35 r90
  text "D10" at 7151.93,1441 h35 r90
  text "D10" at 7200.93,1441 h35 r90
  text "UART" at 225,1405 h80
  text "3V3" at 2560,1405 h35
  text "UART" at 4041.93,1405 h80
  text "3V3" at 6376.93,1405 h35
  text "D8" at 3335,1354 h35 r90
  text "D8" at 3384,1354 h35 r90
  text "D8" at 7151.93,1354 h35 r90
  text "D8" at 7200.93,1354 h35 r90
  text "D11" at 2986,1343 h35 r90
  text "D11" at 3035,1343 h35 r90
  text "D11" at 6802.93,1343 h35 r90
  text "D11" at 6851.93,1343 h35 r90
  text "BOOT0" at 2124,1285 h35
  text "VCC_MCU" at 2315,1285 h35
  text "BOOT0" at 5940.93,1285 h35
  text "VCC_MCU" at 6131.93,1285 h35
  text "D9" at 2986,1250 h35 r90
  text "D9" at 3035,1250 h35 r90
  text "D9" at 6802.93,1250 h35 r90
  text "D9" at 6851.93,1250 h35 r90
  text "B14" at 3335,1245 h35 r90
  text "B14" at 3384,1245 h35 r90
  text "B14" at 7151.93,1245 h35 r90
  text "B14" at 7200.93,1245 h35 r90
  text "VCC_MCU" at 2317,1188 h35
  text "VCC_MCU" at 6133.93,1188 h35
  text "VBAT" at 2127,1176.34 h35
  text "VBAT" at 5943.93,1176.34 h35
  text "B15" at 2986,1143 h35 r90
  text "B15" at 3035,1143 h35 r90
  text "B15" at 6802.93,1143 h35 r90
  text "B15" at 6851.93,1143 h35 r90
  text "B12" at 3335,1139 h35 r90
  text "B12" at 3384,1139 h35 r90
  text "B12" at 7151.93,1139 h35 r90
  text "B12" at 7200.93,1139 h35 r90
  text "POWER" at 799,1130 h35
  text "POWER" at 4615.93,1130 h35
  text "B13" at 2986,1042 h35 r90
  text "B13" at 3035,1042 h35 r90
  text "B13" at 6802.93,1042 h35 r90
  text "B13" at 6851.93,1042 h35 r90
  text "B10" at 3335,1041 h35 r90
  text "B10" at 3384,1041 h35 r90
  text "B10" at 7151.93,1041 h35 r90
  text "B10" at 7200.93,1041 h35 r90
  text "B11" at 2986,945 h35 r90
  text "B11" at 3035,945 h35 r90
  text "B11" at 6802.93,945 h35 r90
  text "B11" at 6851.93,945 h35 r90
  text "E14" at 3335,939 h35 r90
  text "E14" at 3384,939 h35 r90
  text "E14" at 7151.93,939 h35 r90
  text "E14" at 7200.93,939 h35 r90
  text "E15" at 2986,844 h35 r90
  text "E15" at 3035,844 h35 r90
  text "E15" at 6802.93,844 h35 r90
  text "E15" at 6851.93,844 h35 r90
  text "E12" at 3335,839 h35 r90
  text "E12" at 3384,839 h35 r90
  text "E12" at 7151.93,839 h35 r90
  text "E12" at 7200.93,839 h35 r90
  text "LD" at 2807,803 h35
  text "LD" at 6623.93,803 h35
  text "E13" at 2986,741 h35 r90
  text "E13" at 3035,741 h35 r90
  text "E13" at 6802.93,741 h35 r90
  text "E13" at 6851.93,741 h35 r90
  text "E10" at 3335,740 h35 r90
  text "E10" at 3384,740 h35 r90
  text "E10" at 7151.93,740 h35 r90
  text "E10" at 7200.93,740 h35 r90
  text "E8" at 3335,657 h35 r90
  text "E8" at 3384,657 h35 r90
  text "E8" at 7151.93,657 h35 r90
  text "E8" at 7200.93,657 h35 r90
  text "E11" at 2986,651 h35 r90
  text "E11" at 3035,651 h35 r90
  text "E11" at 6802.93,651 h35 r90
  text "E11" at 6851.93,651 h35 r90
  text "PUL_UP" at 2716,595 h35
  text "PUL_UP" at 6532.93,595 h35
  text "E9" at 2986,551 h35 r90
  text "E9" at 3035,551 h35 r90
  text "E9" at 6802.93,551 h35 r90
  text "E9" at 6851.93,551 h35 r90
  text "LD-" at 3335,547 h35 r90
  text "GND" at 3384,547 h35 r90
  text "LD-" at 7151.93,547 h35 r90
  text "GND" at 7200.93,547 h35 r90
  text "WKUP" at 2716,495 h35
  text "WKUP" at 6532.93,495 h35
  text "E7" at 2986,453 h35 r90
  text "E7" at 3035,453 h35 r90
  text "E7" at 6802.93,453 h35 r90
  text "E7" at 6851.93,453 h35 r90
  text "GND" at 3335,440 h35 r90
  text "GND" at 3384,440 h35 r90
  text "GND" at 7151.93,440 h35 r90
  text "GND" at 7200.93,440 h35 r90
  text "PUL_DN" at 2716,395 h35
  text "PUL_DN" at 6532.93,395 h35
  text "ADC" at 2193,385 h80
  text "ADC" at 6009.93,385 h80
  text "E2" at 430,299 h35
  text "E3" at 525,299 h35
  text "E4" at 625,299 h35
  text "E5" at 725,299 h35
  text "E6" at 830,299 h35
  text "C13" at 910,299 h35
  text "C14" at 1011,299 h35
  text "C15" at 1111,299 h35
  text "C0" at 1223,299 h35
  text "C1" at 1325,299 h35
  text "C2" at 1421,299 h35
  text "C3" at 1519,299 h35
  text "A0" at 1619,299 h35
  text "A1" at 1726,299 h35
  text "A2" at 1818,299 h35
  text "A3" at 1918,299 h35
  text "A4" at 2021,299 h35
  text "A5" at 2119,299 h35
  text "A6" at 2223,299 h35
  text "A7" at 2322,299 h35
  text "C4" at 2424,299 h35
  text "C5" at 2521,299 h35
  text "B0" at 2625,299 h35
  text "B1" at 2728,299 h35
  text "B2" at 2822,299 h35
  text "E2" at 4246.93,299 h35
  text "E3" at 4341.93,299 h35
  text "E4" at 4441.93,299 h35
  text "E5" at 4541.93,299 h35
  text "E6" at 4646.93,299 h35
  text "C13" at 4726.93,299 h35
  text "C14" at 4827.93,299 h35
  text "C15" at 4927.93,299 h35
  text "C0" at 5039.93,299 h35
  text "C1" at 5141.93,299 h35
  text "C2" at 5237.93,299 h35
  text "C3" at 5335.93,299 h35
  text "A0" at 5435.93,299 h35
  text "A1" at 5542.93,299 h35
  text "A2" at 5634.93,299 h35
  text "A3" at 5734.93,299 h35
  text "A4" at 5837.93,299 h35
  text "A5" at 5935.93,299 h35
  text "A6" at 6039.93,299 h35
  text "A7" at 6138.93,299 h35
  text "C4" at 6240.93,299 h35
  text "C5" at 6337.93,299 h35
  text "B0" at 6441.93,299 h35
  text "B1" at 6544.93,299 h35
  text "B2" at 6638.93,299 h35
  text "RESET" at 2959,292 h80
  text "RESET" at 6775.93,292 h80
  text "E2" at 430,250 h35
  text "E3" at 525,250 h35
  text "E4" at 625,250 h35
  text "E5" at 725,250 h35
  text "E6" at 830,250 h35
  text "C13" at 910,250 h35
  text "C14" at 1011,250 h35
  text "C15" at 1111,250 h35
  text "C0" at 1223,250 h35
  text "C1" at 1325,250 h35
  text "C2" at 1421,250 h35
  text "C3" at 1519,250 h35
  text "A0" at 1619,250 h35
  text "A1" at 1726,250 h35
  text "A2" at 1818,250 h35
  text "A3" at 1918,250 h35
  text "A4" at 2021,250 h35
  text "A5" at 2119,250 h35
  text "A6" at 2223,250 h35
  text "A7" at 2322,250 h35
  text "C4" at 2424,250 h35
  text "C5" at 2521,250 h35
  text "B0" at 2625,250 h35
  text "B1" at 2728,250 h35
  text "B2" at 2822,250 h35
  text "E2" at 4246.93,250 h35
  text "E3" at 4341.93,250 h35
  text "E4" at 4441.93,250 h35
  text "E5" at 4541.93,250 h35
  text "E6" at 4646.93,250 h35
  text "C13" at 4726.93,250 h35
  text "C14" at 4827.93,250 h35
  text "C15" at 4927.93,250 h35
  text "C0" at 5039.93,250 h35
  text "C1" at 5141.93,250 h35
  text "C2" at 5237.93,250 h35
  text "C3" at 5335.93,250 h35
  text "A0" at 5435.93,250 h35
  text "A1" at 5542.93,250 h35
  text "A2" at 5634.93,250 h35
  text "A3" at 5734.93,250 h35
  text "A4" at 5837.93,250 h35
  text "A5" at 5935.93,250 h35
  text "A6" at 6039.93,250 h35
  text "A7" at 6138.93,250 h35
  text "C4" at 6240.93,250 h35
  text "C5" at 6337.93,250 h35
  text "B0" at 6441.93,250 h35
  text "B1" at 6544.93,250 h35
  text "B2" at 6638.93,250 h35
  text "WKUP" at 2959,77 h80
  text "WKUP" at 6775.93,77 h80
Bottom Overlay:
  drawing of 8048 lines, arcs and shapes, not listed
  text "A10" at 2991,4283 h35 r90
  text "A10" at 3036,4283 h35 r90
  text "3V3" at 3340,4283 h35 r90
  text "3V3" at 3385,4283 h35 r90
  text "A10" at 6807.93,4283 h35 r90
  text "A10" at 6852.93,4283 h35 r90
  text "3V3" at 7156.93,4283 h35 r90
  text "3V3" at 7201.93,4283 h35 r90
  text "A9" at 2991,4174 h35 r90
  text "A9" at 3036,4174 h35 r90
  text "A9" at 6807.93,4174 h35 r90
  text "A9" at 6852.93,4174 h35 r90
  text "5V" at 3340,4173 h35 r90
  text "5V" at 3385,4173 h35 r90
  text "5V" at 7156.93,4173 h35 r90
  text "5V" at 7201.93,4173 h35 r90
  text "A8" at 2990,4074 h35 r90
  text "A8" at 3035,4074 h35 r90
  text "A8" at 6806.93,4074 h35 r90
  text "A8" at 6851.93,4074 h35 r90
  text "C8" at 3339,4073 h35 r90
  text "C8" at 3384,4073 h35 r90
  text "C8" at 7155.93,4073 h35 r90
  text "C8" at 7200.93,4073 h35 r90
  text "E1" at 468,4046 h35
  text "E0" at 577,4046 h35
  text "B9" at 678,4046 h35
  text "B8" at 778,4046 h35
  text "B7" at 877,4046 h35
  text "B6" at 975,4046 h35
  text "B5" at 1080,4046 h35
  text "B4" at 1180,4046 h35
  text "B3" at 1278,4046 h35
  text "D7" at 1377,4046 h35
  text "D6" at 1477,4046 h35
  text "D5" at 1576,4046 h35
  text "D4" at 1681,4046 h35
  text "D3" at 1778,4046 h35
  text "D2" at 1876,4046 h35
  text "D0" at 2077,4046 h35
  text "C12" at 2193,4046 h35
  text "C11" at 2284,4046 h35
  text "C10" at 2391,4046 h35
  text "A15" at 2490,4046 h35
  text "A14" at 2591,4046 h35
  text "A13" at 2693,4046 h35
  text "E1" at 4284.93,4046 h35
  text "E0" at 4393.93,4046 h35
  text "B9" at 4494.93,4046 h35
  text "B8" at 4594.93,4046 h35
  text "B7" at 4693.93,4046 h35
  text "B6" at 4791.93,4046 h35
  text "B5" at 4896.93,4046 h35
  text "B4" at 4996.93,4046 h35
  text "B3" at 5094.93,4046 h35
  text "D7" at 5193.93,4046 h35
  text "D6" at 5293.93,4046 h35
  text "D5" at 5392.93,4046 h35
  text "D4" at 5497.93,4046 h35
  text "D3" at 5594.93,4046 h35
  text "D2" at 5692.93,4046 h35
  text "D0" at 5893.93,4046 h35
  text "C12" at 6009.93,4046 h35
  text "C11" at 6100.93,4046 h35
  text "C10" at 6207.93,4046 h35
  text "A15" at 6306.93,4046 h35
  text "A14" at 6407.93,4046 h35
  text "A13" at 6509.93,4046 h35
  text "D1" at 1973,4045 h35
  text "A12" at 2793,4045 h35
  text "A11" at 2888,4045 h35
  text "D1" at 5789.93,4045 h35
  text "A12" at 6609.93,4045 h35
  text "A11" at 6704.93,4045 h35
  text "E1" at 468,4001 h35
  text "E0" at 577,4001 h35
  text "B9" at 678,4001 h35
  text "B8" at 778,4001 h35
  text "B7" at 877,4001 h35
  text "B6" at 975,4001 h35
  text "B5" at 1080,4001 h35
  text "B4" at 1180,4001 h35
  text "B3" at 1278,4001 h35
  text "D7" at 1377,4001 h35
  text "D6" at 1477,4001 h35
  text "D5" at 1576,4001 h35
  text "D4" at 1681,4001 h35
  text "D3" at 1778,4001 h35
  text "D2" at 1876,4001 h35
  text "D0" at 2077,4001 h35
  text "C12" at 2193,4001 h35
  text "C11" at 2284,4001 h35
  text "C10" at 2391,4001 h35
  text "A15" at 2490,4001 h35
  text "A14" at 2591,4001 h35
  text "A13" at 2693,4001 h35
  text "E1" at 4284.93,4001 h35
  text "E0" at 4393.93,4001 h35
  text "B9" at 4494.93,4001 h35
  text "B8" at 4594.93,4001 h35
  text "B7" at 4693.93,4001 h35
  text "B6" at 4791.93,4001 h35
  text "B5" at 4896.93,4001 h35
  text "B4" at 4996.93,4001 h35
  text "B3" at 5094.93,4001 h35
  text "D7" at 5193.93,4001 h35
  text "D6" at 5293.93,4001 h35
  text "D5" at 5392.93,4001 h35
  text "D4" at 5497.93,4001 h35
  text "D3" at 5594.93,4001 h35
  text "D2" at 5692.93,4001 h35
  text "D0" at 5893.93,4001 h35
  text "C12" at 6009.93,4001 h35
  text "C11" at 6100.93,4001 h35
  text "C10" at 6207.93,4001 h35
  text "A15" at 6306.93,4001 h35
  text "A14" at 6407.93,4001 h35
  text "A13" at 6509.93,4001 h35
  text "D1" at 1973,4000 h35
  text "A12" at 2793,4000 h35
  text "A11" at 2888,4000 h35
  text "D1" at 5789.93,4000 h35
  text "A12" at 6609.93,4000 h35
  text "A11" at 6704.93,4000 h35
  text "C9" at 2990,3974 h35 r90
  text "C9" at 3035,3974 h35 r90
  text "C9" at 6806.93,3974 h35 r90
  text "C9" at 6851.93,3974 h35 r90
  text "C6" at 3339,3973 h35 r90
  text "C6" at 3384,3973 h35 r90
  text "C6" at 7155.93,3973 h35 r90
  text "C6" at 7200.93,3973 h35 r90
  text "SWDCLK" at 2571,3946 h35 r90
  text "SWDIO" at 2671,3946 h35 r90
  text "SWDCLK" at 6387.93,3946 h35 r90
  text "SWDIO" at 6487.93,3946 h35 r90
  text "D14" at 3339,3886 h35 r90
  text "D14" at 3384,3886 h35 r90
  text "D14" at 7155.93,3886 h35 r90
  text "D14" at 7200.93,3886 h35 r90
  text "C7" at 2990,3874 h35 r90
  text "C7" at 3035,3874 h35 r90
  text "C7" at 6806.93,3874 h35 r90
  text "C7" at 6851.93,3874 h35 r90
  text "D15" at 2990,3782 h35 r90
  text "D15" at 3035,3782 h35 r90
  text "D12" at 3339,3782 h35 r90
  text "D12" at 3384,3782 h35 r90
  text "D15" at 6806.93,3782 h35 r90
  text "D15" at 6851.93,3782 h35 r90
  text "D12" at 7155.93,3782 h35 r90
  text "D12" at 7200.93,3782 h35 r90
  text "D10" at 3339,3684 h35 r90
  text "D10" at 3384,3684 h35 r90
  text "D10" at 7155.93,3684 h35 r90
  text "D10" at 7200.93,3684 h35 r90
  text "D13" at 2990,3683 h35 r90
  text "D13" at 3035,3683 h35 r90
  text "D13" at 6806.93,3683 h35 r90
  text "D13" at 6851.93,3683 h35 r90
  text "D11" at 2990,3578 h35 r90
  text "D11" at 3035,3578 h35 r90
  text "D11" at 6806.93,3578 h35 r90
  text "D11" at 6851.93,3578 h35 r90
  text "D8" at 3339,3572 h35 r90
  text "D8" at 3384,3572 h35 r90
  text "D8" at 7155.93,3572 h35 r90
  text "D8" at 7200.93,3572 h35 r90
  text "B14" at 3339,3483 h35 r90
  text "B14" at 3384,3483 h35 r90
  text "B14" at 7155.93,3483 h35 r90
  text "B14" at 7200.93,3483 h35 r90
  text "D9" at 2990,3474 h35 r90
  text "D9" at 3035,3474 h35 r90
  text "D9" at 6806.93,3474 h35 r90
  text "D9" at 6851.93,3474 h35 r90
  text "B15" at 2991,3389 h35 r90
  text "B15" at 3036,3389 h35 r90
  text "B15" at 6807.93,3389 h35 r90
  text "B15" at 6852.93,3389 h35 r90
  text "B12" at 3340,3383 h35 r90
  text "B12" at 3385,3383 h35 r90
  text "B12" at 7156.93,3383 h35 r90
  text "B12" at 7201.93,3383 h35 r90
  text "MM32F103VxT6_CoreBoard V1.0" at 1500,3366 h60
  text "MM32F103VxT6_CoreBoard V1.0" at 5316.93,3366 h60
  text "B13" at 2990,3287 h35 r90
  text "B13" at 3035,3287 h35 r90
  text "B13" at 6806.93,3287 h35 r90
  text "B13" at 6851.93,3287 h35 r90
  text "B10" at 3339,3286 h35 r90
  text "B10" at 3384,3286 h35 r90
  text "B10" at 7155.93,3286 h35 r90
  text "B10" at 7200.93,3286 h35 r90
  text "2018-5-15" at 1151,3254 h60
  text "2018-5-15" at 4967.93,3254 h60
  text "E14" at 3339,3188 h35 r90
  text "E14" at 3384,3188 h35 r90
  text "E14" at 7155.93,3188 h35 r90
  text "E14" at 7200.93,3188 h35 r90
  text "B11" at 2990,3181 h35 r90
  text "B11" at 3035,3181 h35 r90
  text "B11" at 6806.93,3181 h35 r90
  text "B11" at 6851.93,3181 h35 r90
  text "E15" at 2990,3086 h35 r90
  text "E15" at 3035,3086 h35 r90
  text "E12" at 3339,3086 h35 r90
  text "E12" at 3384,3086 h35 r90
  text "E15" at 6806.93,3086 h35 r90
  text "E15" at 6851.93,3086 h35 r90
  text "E12" at 7155.93,3086 h35 r90
  text "E12" at 7200.93,3086 h35 r90
  text "E13" at 2990,2982 h35 r90
  text "E13" at 3035,2982 h35 r90
  text "E13" at 6806.93,2982 h35 r90
  text "E13" at 6851.93,2982 h35 r90
  text "E10" at 3339,2981 h35 r90
  text "E10" at 3384,2981 h35 r90
  text "E10" at 7155.93,2981 h35 r90
  text "E10" at 7200.93,2981 h35 r90
  text "E11" at 2990,2878 h35 r90
  text "E11" at 3035,2878 h35 r90
  text "E11" at 6806.93,2878 h35 r90
  text "E11" at 6851.93,2878 h35 r90
  text "E8" at 3339,2873 h35 r90
  text "E8" at 3384,2873 h35 r90
  text "E8" at 7155.93,2873 h35 r90
  text "E8" at 7200.93,2873 h35 r90
  text "LD-" at 3339,2797 h35 r90
  text "GND" at 3384,2797 h35 r90
  text "LD-" at 7155.93,2797 h35 r90
  text "GND" at 7200.93,2797 h35 r90
  text "E9" at 2990,2770 h35 r90
  text "E9" at 3035,2770 h35 r90
  text "E9" at 6806.93,2770 h35 r90
  text "E9" at 6851.93,2770 h35 r90
  text "GND" at 3339,2695 h35 r90
  text "GND" at 3384,2695 h35 r90
  text "GND" at 7155.93,2695 h35 r90
  text "GND" at 7200.93,2695 h35 r90
  text "E7" at 2990,2672 h35 r90
  text "E7" at 3035,2672 h35 r90
  text "E7" at 6806.93,2672 h35 r90
  text "E7" at 6851.93,2672 h35 r90
  text "E2" at 478,2460 h35
  text "E3" at 573,2460 h35
  text "E4" at 679,2460 h35
  text "E5" at 778,2460 h35
  text "E6" at 877,2460 h35
  text "C13" at 992,2460 h35
  text "C14" at 1092,2460 h35
  text "C15" at 1197,2460 h35
  text "C0" at 1281,2460 h35
  text "C1" at 1380,2460 h35
  text "C2" at 1483,2460 h35
  text "C3" at 1582,2460 h35
  text "A0" at 1682,2460 h35
  text "A1" at 1777,2460 h35
  text "A2" at 1884,2460 h35
  text "A4" at 2084,2460 h35
  text "A5" at 2183,2460 h35
  text "A6" at 2280,2460 h35
  text "A7" at 2382,2460 h35
  text "C4" at 2482,2460 h35
  text "C5" at 2579,2460 h35
  text "B0" at 2679,2460 h35
  text "E2" at 4294.93,2460 h35
  text "E3" at 4389.93,2460 h35
  text "E4" at 4495.93,2460 h35
  text "E5" at 4594.93,2460 h35
  text "E6" at 4693.93,2460 h35
  text "C13" at 4808.93,2460 h35
  text "C14" at 4908.93,2460 h35
  text "C15" at 5013.93,2460 h35
  text "C0" at 5097.93,2460 h35
  text "C1" at 5196.93,2460 h35
  text "C2" at 5299.93,2460 h35
  text "C3" at 5398.93,2460 h35
  text "A0" at 5498.93,2460 h35
  text "A1" at 5593.93,2460 h35
  text "A2" at 5700.93,2460 h35
  text "A4" at 5900.93,2460 h35
  text "A5" at 5999.93,2460 h35
  text "A6" at 6096.93,2460 h35
  text "A7" at 6198.93,2460 h35
  text "C4" at 6298.93,2460 h35
  text "C5" at 6395.93,2460 h35
  text "B0" at 6495.93,2460 h35
  text "A3" at 1983,2459 h35
  text "B1" at 2775,2459 h35
  text "B2" at 2881,2459 h35
  text "A3" at 5799.93,2459 h35
  text "B1" at 6591.93,2459 h35
  text "B2" at 6697.93,2459 h35
  text "E2" at 478,2415 h35
  text "E3" at 573,2415 h35
  text "E4" at 679,2415 h35
  text "E5" at 778,2415 h35
  text "E6" at 877,2415 h35
  text "C13" at 992,2415 h35
  text "C14" at 1092,2415 h35
  text "C15" at 1197,2415 h35
  text "C0" at 1281,2415 h35
  text "C1" at 1380,2415 h35
  text "C2" at 1483,2415 h35
  text "C3" at 1582,2415 h35
  text "A0" at 1682,2415 h35
  text "A1" at 1777,2415 h35
  text "A2" at 1884,2415 h35
  text "A4" at 2084,2415 h35
  text "A5" at 2183,2415 h35
  text "A6" at 2280,2415 h35
  text "A7" at 2382,2415 h35
  text "C4" at 2482,2415 h35
  text "C5" at 2579,2415 h35
  text "B0" at 2679,2415 h35
  text "E2" at 4294.93,2415 h35
  text "E3" at 4389.93,2415 h35
  text "E4" at 4495.93,2415 h35
  text "E5" at 4594.93,2415 h35
  text "E6" at 4693.93,2415 h35
  text "C13" at 4808.93,2415 h35
  text "C14" at 4908.93,2415 h35
  text "C15" at 5013.93,2415 h35
  text "C0" at 5097.93,2415 h35
  text "C1" at 5196.93,2415 h35
  text "C2" at 5299.93,2415 h35
  text "C3" at 5398.93,2415 h35
  text "A0" at 5498.93,2415 h35
  text "A1" at 5593.93,2415 h35
  text "A2" at 5700.93,2415 h35
  text "A4" at 5900.93,2415 h35
  text "A5" at 5999.93,2415 h35
  text "A6" at 6096.93,2415 h35
  text "A7" at 6198.93,2415 h35
  text "C4" at 6298.93,2415 h35
  text "C5" at 6395.93,2415 h35
  text "B0" at 6495.93,2415 h35
  text "A3" at 1983,2414 h35
  text "B1" at 2775,2414 h35
  text "B2" at 2881,2414 h35
  text "A3" at 5799.93,2414 h35
  text "B1" at 6591.93,2414 h35
  text "B2" at 6697.93,2414 h35
  text "A10" at 2991,2118 h35 r90
  text "A10" at 3036,2118 h35 r90
  text "3V3" at 3340,2118 h35 r90
  text "3V3" at 3385,2118 h35 r90
  text "A10" at 6807.93,2118 h35 r90
  text "A10" at 6852.93,2118 h35 r90
  text "3V3" at 7156.93,2118 h35 r90
  text "3V3" at 7201.93,2118 h35 r90
  text "A9" at 2991,2009 h35 r90
  text "A9" at 3036,2009 h35 r90
  text "A9" at 6807.93,2009 h35 r90
  text "A9" at 6852.93,2009 h35 r90
  text "5V" at 3340,2008 h35 r90
  text "5V" at 3385,2008 h35 r90
  text "5V" at 7156.93,2008 h35 r90
  text "5V" at 7201.93,2008 h35 r90
  text "A8" at 2990,1909 h35 r90
  text "A8" at 3035,1909 h35 r90
  text "A8" at 6806.93,1909 h35 r90
  text "A8" at 6851.93,1909 h35 r90
  text "C8" at 3339,1908 h35 r90
  text "C8" at 3384,1908 h35 r90
  text "C8" at 7155.93,1908 h35 r90
  text "C8" at 7200.93,1908 h35 r90
  text "E1" at 468,1881 h35
  text "E0" at 577,1881 h35
  text "B9" at 678,1881 h35
  text "B8" at 778,1881 h35
  text "B7" at 877,1881 h35
  text "B6" at 975,1881 h35
  text "B5" at 1080,1881 h35
  text "B4" at 1180,1881 h35
  text "B3" at 1278,1881 h35
  text "D7" at 1377,1881 h35
  text "D6" at 1477,1881 h35
  text "D5" at 1576,1881 h35
  text "D4" at 1681,1881 h35
  text "D3" at 1778,1881 h35
  text "D2" at 1876,1881 h35
  text "D0" at 2077,1881 h35
  text "C12" at 2193,1881 h35
  text "C11" at 2284,1881 h35
  text "C10" at 2391,1881 h35
  text "A15" at 2490,1881 h35
  text "A14" at 2591,1881 h35
  text "A13" at 2693,1881 h35
  text "E1" at 4284.93,1881 h35
  text "E0" at 4393.93,1881 h35
  text "B9" at 4494.93,1881 h35
  text "B8" at 4594.93,1881 h35
  text "B7" at 4693.93,1881 h35
  text "B6" at 4791.93,1881 h35
  text "B5" at 4896.93,1881 h35
  text "B4" at 4996.93,1881 h35
  text "B3" at 5094.93,1881 h35
  text "D7" at 5193.93,1881 h35
  text "D6" at 5293.93,1881 h35
  text "D5" at 5392.93,1881 h35
  text "D4" at 5497.93,1881 h35
  text "D3" at 5594.93,1881 h35
  text "D2" at 5692.93,1881 h35
  text "D0" at 5893.93,1881 h35
  text "C12" at 6009.93,1881 h35
  text "C11" at 6100.93,1881 h35
  text "C10" at 6207.93,1881 h35
  text "A15" at 6306.93,1881 h35
  text "A14" at 6407.93,1881 h35
  text "A13" at 6509.93,1881 h35
  text "D1" at 1973,1880 h35
  text "A12" at 2793,1880 h35
  text "A11" at 2888,1880 h35
  text "D1" at 5789.93,1880 h35
  text "A12" at 6609.93,1880 h35
  text "A11" at 6704.93,1880 h35
  text "E1" at 468,1836 h35
  text "E0" at 577,1836 h35
  text "B9" at 678,1836 h35
  text "B8" at 778,1836 h35
  text "B7" at 877,1836 h35
  text "B6" at 975,1836 h35
  text "B5" at 1080,1836 h35
  text "B4" at 1180,1836 h35
  text "B3" at 1278,1836 h35
  text "D7" at 1377,1836 h35
  text "D6" at 1477,1836 h35
  text "D5" at 1576,1836 h35
  text "D4" at 1681,1836 h35
  text "D3" at 1778,1836 h35
  text "D2" at 1876,1836 h35
  text "D0" at 2077,1836 h35
  text "C12" at 2193,1836 h35
  text "C11" at 2284,1836 h35
  text "C10" at 2391,1836 h35
  text "A15" at 2490,1836 h35
  text "A14" at 2591,1836 h35
  text "A13" at 2693,1836 h35
  text "E1" at 4284.93,1836 h35
  text "E0" at 4393.93,1836 h35
  text "B9" at 4494.93,1836 h35
  text "B8" at 4594.93,1836 h35
  text "B7" at 4693.93,1836 h35
  text "B6" at 4791.93,1836 h35
  text "B5" at 4896.93,1836 h35
  text "B4" at 4996.93,1836 h35
  text "B3" at 5094.93,1836 h35
  text "D7" at 5193.93,1836 h35
  text "D6" at 5293.93,1836 h35
  text "D5" at 5392.93,1836 h35
  text "D4" at 5497.93,1836 h35
  text "D3" at 5594.93,1836 h35
  text "D2" at 5692.93,1836 h35
  text "D0" at 5893.93,1836 h35
  text "C12" at 6009.93,1836 h35
  text "C11" at 6100.93,1836 h35
  text "C10" at 6207.93,1836 h35
  text "A15" at 6306.93,1836 h35
  text "A14" at 6407.93,1836 h35
  text "A13" at 6509.93,1836 h35
  text "D1" at 1973,1835 h35
  text "A12" at 2793,1835 h35
  text "A11" at 2888,1835 h35
  text "D1" at 5789.93,1835 h35
  text "A12" at 6609.93,1835 h35
  text "A11" at 6704.93,1835 h35
  text "C9" at 2990,1809 h35 r90
  text "C9" at 3035,1809 h35 r90
  text "C9" at 6806.93,1809 h35 r90
  text "C9" at 6851.93,1809 h35 r90
  text "C6" at 3339,1808 h35 r90
  text "C6" at 3384,1808 h35 r90
  text "C6" at 7155.93,1808 h35 r90
  text "C6" at 7200.93,1808 h35 r90
  text "SWDCLK" at 2571,1781 h35 r90
  text "SWDIO" at 2671,1781 h35 r90
  text "SWDCLK" at 6387.93,1781 h35 r90
  text "SWDIO" at 6487.93,1781 h35 r90
  text "D14" at 3339,1721 h35 r90
  text "D14" at 3384,1721 h35 r90
  text "D14" at 7155.93,1721 h35 r90
  text "D14" at 7200.93,1721 h35 r90
  text "C7" at 2990,1709 h35 r90
  text "C7" at 3035,1709 h35 r90
  text "C7" at 6806.93,1709 h35 r90
  text "C7" at 6851.93,1709 h35 r90
  text "D15" at 2990,1617 h35 r90
  text "D15" at 3035,1617 h35 r90
  text "D12" at 3339,1617 h35 r90
  text "D12" at 3384,1617 h35 r90
  text "D15" at 6806.93,1617 h35 r90
  text "D15" at 6851.93,1617 h35 r90
  text "D12" at 7155.93,1617 h35 r90
  text "D12" at 7200.93,1617 h35 r90
  text "D10" at 3339,1519 h35 r90
  text "D10" at 3384,1519 h35 r90
  text "D10" at 7155.93,1519 h35 r90
  text "D10" at 7200.93,1519 h35 r90
  text "D13" at 2990,1518 h35 r90
  text "D13" at 3035,1518 h35 r90
  text "D13" at 6806.93,1518 h35 r90
  text "D13" at 6851.93,1518 h35 r90
  text "D11" at 2990,1413 h35 r90
  text "D11" at 3035,1413 h35 r90
  text "D11" at 6806.93,1413 h35 r90
  text "D11" at 6851.93,1413 h35 r90
  text "D8" at 3339,1407 h35 r90
  text "D8" at 3384,1407 h35 r90
  text "D8" at 7155.93,1407 h35 r90
  text "D8" at 7200.93,1407 h35 r90
  text "B14" at 3339,1318 h35 r90
  text "B14" at 3384,1318 h35 r90
  text "B14" at 7155.93,1318 h35 r90
  text "B14" at 7200.93,1318 h35 r90
  text "D9" at 2990,1309 h35 r90
  text "D9" at 3035,1309 h35 r90
  text "D9" at 6806.93,1309 h35 r90
  text "D9" at 6851.93,1309 h35 r90
  text "B15" at 2991,1224 h35 r90
  text "B15" at 3036,1224 h35 r90
  text "B15" at 6807.93,1224 h35 r90
  text "B15" at 6852.93,1224 h35 r90
  text "B12" at 3340,1218 h35 r90
  text "B12" at 3385,1218 h35 r90
  text "B12" at 7156.93,1218 h35 r90
  text "B12" at 7201.93,1218 h35 r90
  text "MM32F103VxT6_CoreBoard V1.0" at 1500,1201 h60
  text "MM32F103VxT6_CoreBoard V1.0" at 5316.93,1201 h60
  text "B13" at 2990,1122 h35 r90
  text "B13" at 3035,1122 h35 r90
  text "B13" at 6806.93,1122 h35 r90
  text "B13" at 6851.93,1122 h35 r90
  text "B10" at 3339,1121 h35 r90
  text "B10" at 3384,1121 h35 r90
  text "B10" at 7155.93,1121 h35 r90
  text "B10" at 7200.93,1121 h35 r90
  text "2018-5-15" at 1151,1089 h60
  text "2018-5-15" at 4967.93,1089 h60
  text "E14" at 3339,1023 h35 r90
  text "E14" at 3384,1023 h35 r90
  text "E14" at 7155.93,1023 h35 r90
  text "E14" at 7200.93,1023 h35 r90
  text "B11" at 2990,1016 h35 r90
  text "B11" at 3035,1016 h35 r90
  text "B11" at 6806.93,1016 h35 r90
  text "B11" at 6851.93,1016 h35 r90
  text "E15" at 2990,921 h35 r90
  text "E15" at 3035,921 h35 r90
  text "E12" at 3339,921 h35 r90
  text "E12" at 3384,921 h35 r90
  text "E15" at 6806.93,921 h35 r90
  text "E15" at 6851.93,921 h35 r90
  text "E12" at 7155.93,921 h35 r90
  text "E12" at 7200.93,921 h35 r90
  text "E13" at 2990,817 h35 r90
  text "E13" at 3035,817 h35 r90
  text "E13" at 6806.93,817 h35 r90
  text "E13" at 6851.93,817 h35 r90
  text "E10" at 3339,816 h35 r90
  text "E10" at 3384,816 h35 r90
  text "E10" at 7155.93,816 h35 r90
  text "E10" at 7200.93,816 h35 r90
  text "E11" at 2990,713 h35 r90
  text "E11" at 3035,713 h35 r90
  text "E11" at 6806.93,713 h35 r90
  text "E11" at 6851.93,713 h35 r90
  text "E8" at 3339,708 h35 r90
  text "E8" at 3384,708 h35 r90
  text "E8" at 7155.93,708 h35 r90
  text "E8" at 7200.93,708 h35 r90
  text "LD-" at 3339,632 h35 r90
  text "GND" at 3384,632 h35 r90
  text "LD-" at 7155.93,632 h35 r90
  text "GND" at 7200.93,632 h35 r90
  text "E9" at 2990,605 h35 r90
  text "E9" at 3035,605 h35 r90
  text "E9" at 6806.93,605 h35 r90
  text "E9" at 6851.93,605 h35 r90
  text "GND" at 3339,530 h35 r90
  text "GND" at 3384,530 h35 r90
  text "GND" at 7155.93,530 h35 r90
  text "GND" at 7200.93,530 h35 r90
  text "E7" at 2990,507 h35 r90
  text "E7" at 3035,507 h35 r90
  text "E7" at 6806.93,507 h35 r90
  text "E7" at 6851.93,507 h35 r90
  text "E2" at 478,295 h35
  text "E3" at 573,295 h35
  text "E4" at 679,295 h35
  text "E5" at 778,295 h35
  text "E6" at 877,295 h35
  text "C13" at 992,295 h35
  text "C14" at 1092,295 h35
  text "C15" at 1197,295 h35
  text "C0" at 1281,295 h35
  text "C1" at 1380,295 h35
  text "C2" at 1483,295 h35
  text "C3" at 1582,295 h35
  text "A0" at 1682,295 h35
  text "A1" at 1777,295 h35
  text "A2" at 1884,295 h35
  text "A4" at 2084,295 h35
  text "A5" at 2183,295 h35
  text "A6" at 2280,295 h35
  text "A7" at 2382,295 h35
  text "C4" at 2482,295 h35
  text "C5" at 2579,295 h35
  text "B0" at 2679,295 h35
  text "E2" at 4294.93,295 h35
  text "E3" at 4389.93,295 h35
  text "E4" at 4495.93,295 h35
  text "E5" at 4594.93,295 h35
  text "E6" at 4693.93,295 h35
  text "C13" at 4808.93,295 h35
  text "C14" at 4908.93,295 h35
  text "C15" at 5013.93,295 h35
  text "C0" at 5097.93,295 h35
  text "C1" at 5196.93,295 h35
  text "C2" at 5299.93,295 h35
  text "C3" at 5398.93,295 h35
  text "A0" at 5498.93,295 h35
  text "A1" at 5593.93,295 h35
  text "A2" at 5700.93,295 h35
  text "A4" at 5900.93,295 h35
  text "A5" at 5999.93,295 h35
  text "A6" at 6096.93,295 h35
  text "A7" at 6198.93,295 h35
  text "C4" at 6298.93,295 h35
  text "C5" at 6395.93,295 h35
  text "B0" at 6495.93,295 h35
  text "A3" at 1983,294 h35
  text "B1" at 2775,294 h35
  text "B2" at 2881,294 h35
  text "A3" at 5799.93,294 h35
  text "B1" at 6591.93,294 h35
  text "B2" at 6697.93,294 h35
  text "E2" at 478,250 h35
  text "E3" at 573,250 h35
  text "E4" at 679,250 h35
  text "E5" at 778,250 h35
  text "E6" at 877,250 h35
  text "C13" at 992,250 h35
  text "C14" at 1092,250 h35
  text "C15" at 1197,250 h35
  text "C0" at 1281,250 h35
  text "C1" at 1380,250 h35
  text "C2" at 1483,250 h35
  text "C3" at 1582,250 h35
  text "A0" at 1682,250 h35
  text "A1" at 1777,250 h35
  text "A2" at 1884,250 h35
  text "A4" at 2084,250 h35
  text "A5" at 2183,250 h35
  text "A6" at 2280,250 h35
  text "A7" at 2382,250 h35
  text "C4" at 2482,250 h35
  text "C5" at 2579,250 h35
  text "B0" at 2679,250 h35
  text "E2" at 4294.93,250 h35
  text "E3" at 4389.93,250 h35
  text "E4" at 4495.93,250 h35
  text "E5" at 4594.93,250 h35
  text "E6" at 4693.93,250 h35
  text "C13" at 4808.93,250 h35
  text "C14" at 4908.93,250 h35
  text "C15" at 5013.93,250 h35
  text "C0" at 5097.93,250 h35
  text "C1" at 5196.93,250 h35
  text "C2" at 5299.93,250 h35
  text "C3" at 5398.93,250 h35
  text "A0" at 5498.93,250 h35
  text "A1" at 5593.93,250 h35
  text "A2" at 5700.93,250 h35
  text "A4" at 5900.93,250 h35
  text "A5" at 5999.93,250 h35
  text "A6" at 6096.93,250 h35
  text "A7" at 6198.93,250 h35
  text "C4" at 6298.93,250 h35
  text "C5" at 6395.93,250 h35
  text "B0" at 6495.93,250 h35
  text "A3" at 1983,249 h35
  text "B1" at 2775,249 h35
  text "B2" at 2881,249 h35
  text "A3" at 5799.93,249 h35
  text "B1" at 6591.93,249 h35
  text "B2" at 6697.93,249 h35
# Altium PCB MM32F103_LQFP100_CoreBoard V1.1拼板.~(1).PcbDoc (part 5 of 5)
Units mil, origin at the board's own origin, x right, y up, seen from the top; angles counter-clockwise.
Board outline 7436.93 x 4329.96 mil, 2 copper layers (Top Layer, Bottom Layer); 260 components, 116 nets, 1796 pads, 448 vias.

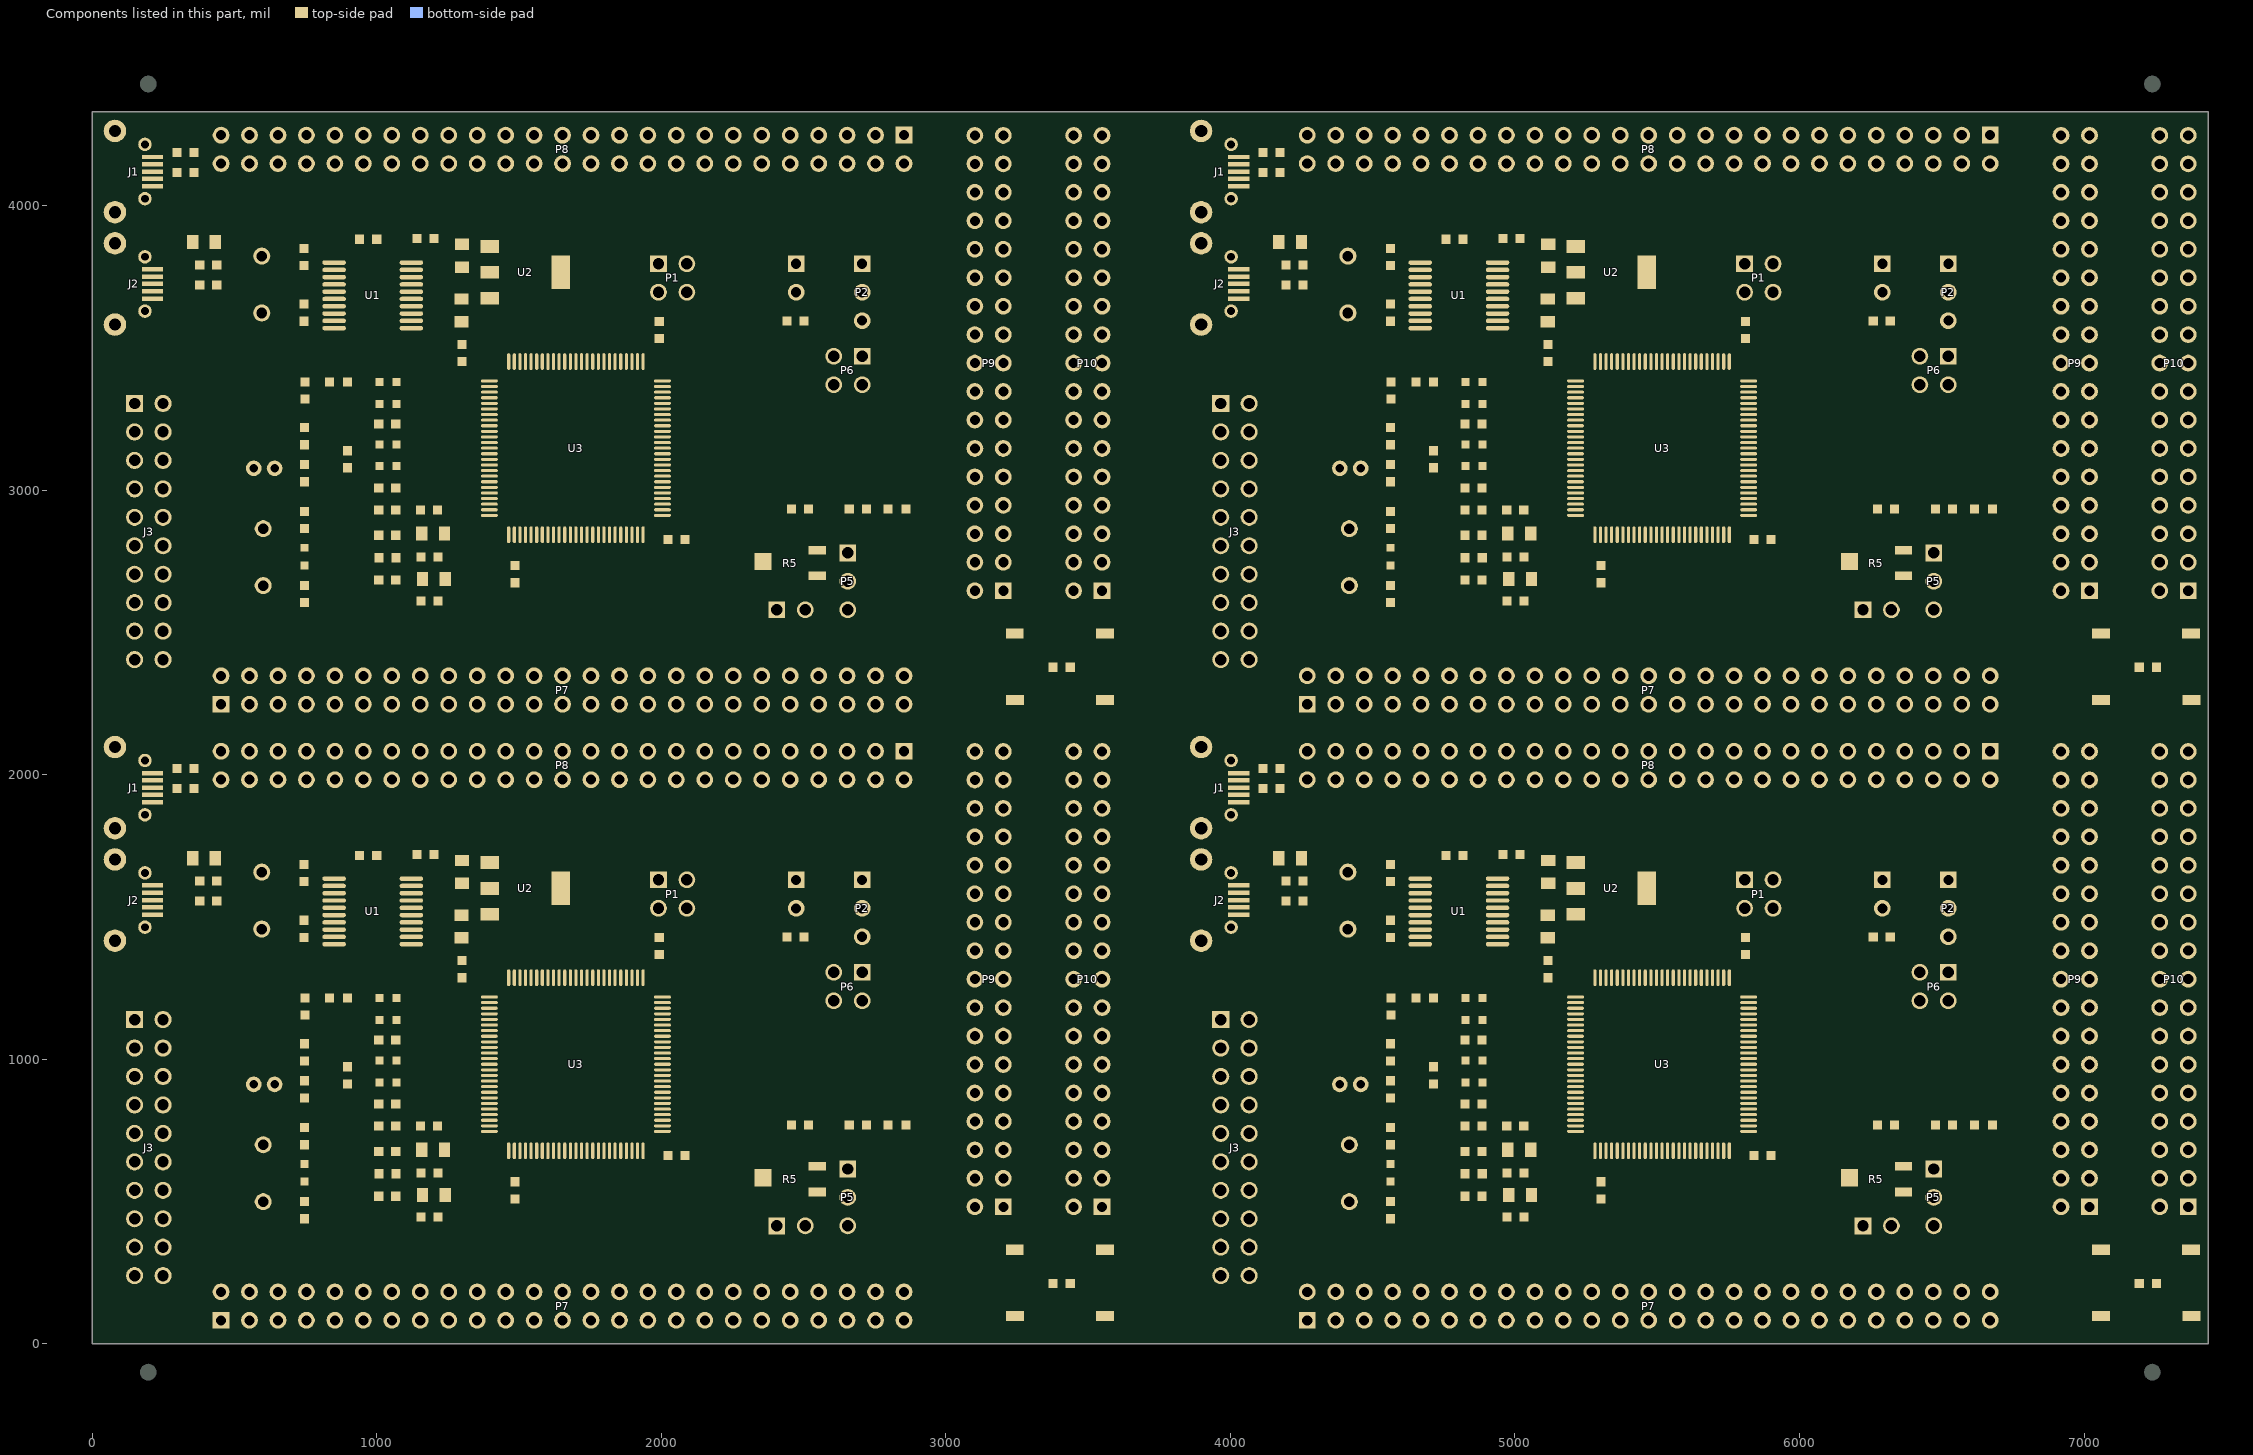
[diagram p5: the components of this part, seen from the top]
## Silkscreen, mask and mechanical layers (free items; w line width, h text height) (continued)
Top Solder:
  rectangle: 4355.93,3124 4481.93,3443
  rectangle: 539,3124 665,3443
  rectangle: 4355.93,959 4481.93,1278
  rectangle: 539,959 665,1278
Mechanical 1:
  lines w5: 0,66 ccw(c66.03,65.55) 66,-0.48 ; 0,2231 ccw(c66.03,2230.55) 66,2164.52 ; 0,4329.96 0,4526.81 7436.93,4526.81 7436.93,2164.96 ; 0.52,2098.5 cw(c66.55,2098.48) 67,2164.5 ; 0.52,4263.5 cw(c66.55,4263.48) 67,4329.5 ; 3553.52,0 ccw(c3553.97,66.03) 3620,66 ; 3553.52,2165 ccw(c3553.97,2231.03) 3620,2231 ; 3554,2164.5 cw(c3553.97,2098.48) 3620,2098.02 ; 3554,4329.5 cw(c3553.97,4263.48) 3620,4263.02 ; 3816.93,66 ccw(c3882.95,65.55) 3882.93,-0.48 ; 3816.93,2231 ccw(c3882.95,2230.55) 3882.93,2164.52 ; 3817.45,2098.5 cw(c3883.48,2098.48) 3883.93,2164.5 ; 3817.45,4263.5 cw(c3883.48,4263.48) 3883.93,4329.5 ; 7370.45,0 ccw(c7370.9,66.03) 7436.93,66 ; 7370.45,2165 ccw(c7370.9,2231.03) 7436.93,2231 ; 7370.93,2164.5 cw(c7370.9,2098.48) 7436.93,2098.02 ; 7370.93,4329.5 cw(c7370.9,4263.48) 7436.93,4263.02 ; 0,0 3620,0 ; 0,0 0,2165 ; 0,0 0,-196.85 7436.93,-196.85 7436.93,2165 ; 0,2165 3620,2165 ; 0,2165 0,4330 3620,4330 ; 0,2165 3620,2165 ; 3620,0 3816.93,0 ; 3620,0 3620,2165 ; 3620,2165 3620,4330 ; 3620,4330 3816.93,4330 ; 3816.93,0 7436.93,0 7436.93,2165 ; 3816.93,0 3816.93,2165 ; 3816.93,2165 7436.93,2165 ; 3816.93,2165 3816.93,4330 ; 3816.93,2165 7436.93,2165 ; 3816.93,4330 7436.93,4330 7436.93,2165

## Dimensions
0,4526.81 to 0,-196.85 on Mechanical 1
0,4526.81 to 7436.93,4526.81 on Mechanical 1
